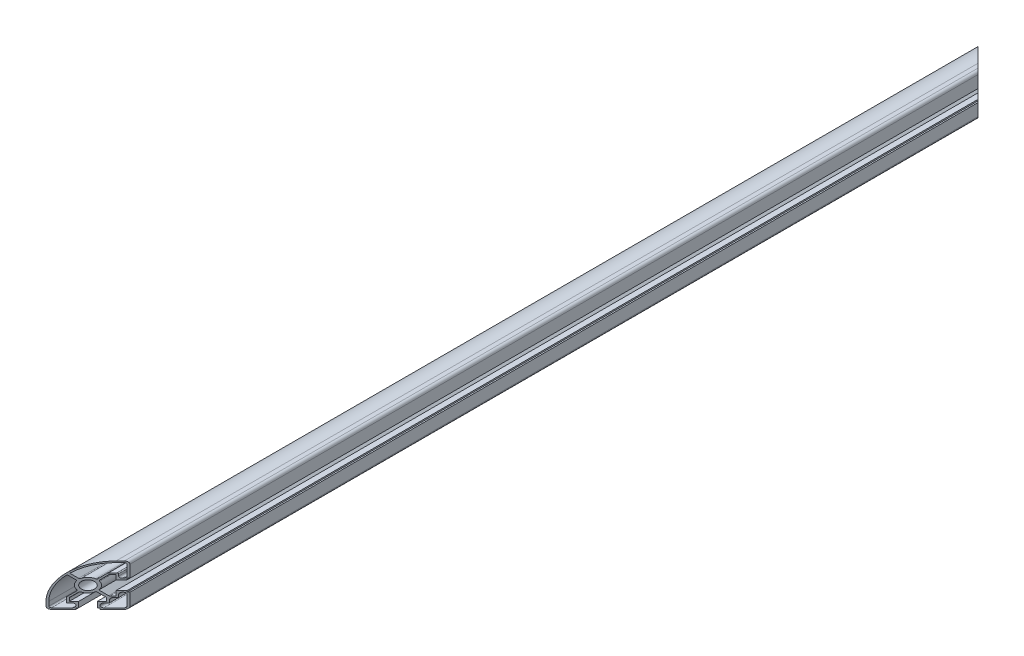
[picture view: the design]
ISO-10303-21;
HEADER;
FILE_DESCRIPTION(('STEP AP214'),'2;1');
FILE_NAME('part.step','',(''),(''),'','','');
FILE_SCHEMA(('AUTOMOTIVE_DESIGN { 1 0 10303 214 1 1 1 1 }'));
ENDSEC;
DATA;
#1=APPLICATION_CONTEXT('core data for automotive mechanical design processes');
#2=APPLICATION_PROTOCOL_DEFINITION('international standard','automotive_design',2000,#1);
#3=PRODUCT_CONTEXT('',#1,'mechanical');
#4=PRODUCT('Part','Part','',(#3));
#5=PRODUCT_RELATED_PRODUCT_CATEGORY('part','',(#4));
#6=PRODUCT_DEFINITION_FORMATION('','',#4);
#7=PRODUCT_DEFINITION_CONTEXT('part definition',#1,'design');
#8=PRODUCT_DEFINITION('design','',#6,#7);
#9=PRODUCT_DEFINITION_SHAPE('','',#8);
#10=(LENGTH_UNIT() NAMED_UNIT(*) SI_UNIT(.MILLI.,.METRE.));
#11=(NAMED_UNIT(*) PLANE_ANGLE_UNIT() SI_UNIT($,.RADIAN.));
#12=(NAMED_UNIT(*) SI_UNIT($,.STERADIAN.) SOLID_ANGLE_UNIT());
#13=UNCERTAINTY_MEASURE_WITH_UNIT(LENGTH_MEASURE(1.E-05),#10,'distance_accuracy_value','');
#14=(GEOMETRIC_REPRESENTATION_CONTEXT(3) GLOBAL_UNCERTAINTY_ASSIGNED_CONTEXT((#13)) GLOBAL_UNIT_ASSIGNED_CONTEXT((#10,
#11,#12)) REPRESENTATION_CONTEXT('',''));
#15=CARTESIAN_POINT('',(0.,0.,0.));
#16=DIRECTION('',(0.,0.,1.));
#17=DIRECTION('',(1.,0.,0.));
#18=AXIS2_PLACEMENT_3D('',#15,#16,#17);
#19=CARTESIAN_POINT('',(-11.2928932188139,32.9999999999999,-55.0352282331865));
#20=DIRECTION('',(0.,0.,-1.));
#21=DIRECTION('',(-1.,0.,0.));
#22=AXIS2_PLACEMENT_3D('',#19,#20,#21);
#23=CYLINDRICAL_SURFACE('',#22,1.);
#24=CARTESIAN_POINT('',(-11.2928932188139,32.9999999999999,-88.7423350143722));
#25=DIRECTION('',(-0.707106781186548,0.,-0.707106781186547));
#26=DIRECTION('',(0.707106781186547,0.,-0.707106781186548));
#27=AXIS2_PLACEMENT_3D('',#24,#25,#26);
#28=ELLIPSE('',#27,1.4142135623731,1.);
#29=CARTESIAN_POINT('',(-11.2928932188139,33.9999999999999,-88.7423350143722));
#30=VERTEX_POINT('',#29);
#31=CARTESIAN_POINT('',(-12.0000000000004,33.7071067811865,-88.0352282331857));
#32=VERTEX_POINT('',#31);
#33=EDGE_CURVE('E1252',#30,#32,#28,.F.);
#34=ORIENTED_EDGE('',*,*,#33,.F.);
#35=DIRECTION('',(0.,0.,-1.));
#36=VECTOR('',#35,1.);
#37=CARTESIAN_POINT('',(-11.2928932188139,33.9999999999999,-55.0352282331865));
#38=LINE('',#37,#36);
#39=CARTESIAN_POINT('',(-11.2928932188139,33.9999999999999,-1021.32812145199));
#40=VERTEX_POINT('',#39);
#41=EDGE_CURVE('E756',#30,#40,#38,.T.);
#42=ORIENTED_EDGE('',*,*,#41,.T.);
#43=CARTESIAN_POINT('',(-11.2928932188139,32.9999999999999,-1021.32812145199));
#44=DIRECTION('',(-0.707106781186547,0.,0.707106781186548));
#45=DIRECTION('',(-0.707106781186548,0.,-0.707106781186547));
#46=AXIS2_PLACEMENT_3D('',#43,#44,#45);
#47=ELLIPSE('',#46,1.41421356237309,1.);
#48=CARTESIAN_POINT('',(-12.0000000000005,33.7071067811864,-1022.03522823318));
#49=VERTEX_POINT('',#48);
#50=EDGE_CURVE('E955',#49,#40,#47,.F.);
#51=ORIENTED_EDGE('',*,*,#50,.F.);
#52=DIRECTION('',(0.,0.,-1.));
#53=VECTOR('',#52,1.);
#54=CARTESIAN_POINT('',(-12.0000000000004,33.7071067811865,-55.0352282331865));
#55=LINE('',#54,#53);
#56=EDGE_CURVE('E11',#32,#49,#55,.T.);
#57=ORIENTED_EDGE('',*,*,#56,.F.);
#58=EDGE_LOOP('',(#34,#42,#51,#57));
#59=FACE_BOUND('',#58,.T.);
#60=ADVANCED_FACE('F31',(#59),#23,.T.);
#61=CARTESIAN_POINT('',(-48.0631727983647,-2.35606601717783,-55.0352282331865));
#62=DIRECTION('',(-0.707106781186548,0.707106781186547,0.));
#63=DIRECTION('',(-0.707106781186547,-0.707106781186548,0.));
#64=AXIS2_PLACEMENT_3D('',#61,#62,#63);
#65=PLANE('',#64);
#66=DIRECTION('',(-0.577350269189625,-0.577350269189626,0.577350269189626));
#67=VECTOR('',#66,1.);
#68=CARTESIAN_POINT('',(-47.0421151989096,-1.33500841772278,-52.9931130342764));
#69=LINE('',#68,#67);
#70=CARTESIAN_POINT('',(-17.0685685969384,28.6385381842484,-82.9666596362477));
#71=VERTEX_POINT('',#70);
#72=EDGE_CURVE('E1250',#32,#71,#69,.T.);
#73=ORIENTED_EDGE('',*,*,#72,.F.);
#74=ORIENTED_EDGE('',*,*,#56,.T.);
#75=DIRECTION('',(0.577350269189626,0.577350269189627,0.577350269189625));
#76=VECTOR('',#75,1.);
#77=CARTESIAN_POINT('',(286.291218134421,331.998324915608,-723.744010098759));
#78=LINE('',#77,#76);
#79=CARTESIAN_POINT('',(-17.0685685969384,28.6385381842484,-1027.10379683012));
#80=VERTEX_POINT('',#79);
#81=EDGE_CURVE('E952',#80,#49,#78,.T.);
#82=ORIENTED_EDGE('',*,*,#81,.F.);
#83=DIRECTION('',(0.,0.,-1.));
#84=VECTOR('',#83,1.);
#85=CARTESIAN_POINT('',(-17.0685685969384,28.6385381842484,-55.0352282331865));
#86=LINE('',#85,#84);
#87=EDGE_CURVE('E40',#71,#80,#86,.T.);
#88=ORIENTED_EDGE('',*,*,#87,.F.);
#89=EDGE_LOOP('',(#73,#74,#82,#88));
#90=FACE_BOUND('',#89,.T.);
#91=ADVANCED_FACE('F1365',(#90),#65,.T.);
#92=CARTESIAN_POINT('',(-17.775675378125,29.345644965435,-55.0352282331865));
#93=DIRECTION('',(0.,0.,-1.));
#94=DIRECTION('',(-1.,0.,0.));
#95=AXIS2_PLACEMENT_3D('',#92,#93,#94);
#96=CYLINDRICAL_SURFACE('',#95,1.);
#97=CARTESIAN_POINT('',(-17.775675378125,29.345644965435,-82.2595528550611));
#98=DIRECTION('',(-0.707106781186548,0.,-0.707106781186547));
#99=DIRECTION('',(0.707106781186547,0.,-0.707106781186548));
#100=AXIS2_PLACEMENT_3D('',#97,#98,#99);
#101=ELLIPSE('',#100,1.4142135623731,1.);
#102=CARTESIAN_POINT('',(-18.3436682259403,28.5226114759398,-81.6915600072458));
#103=VERTEX_POINT('',#102);
#104=EDGE_CURVE('E1248',#71,#103,#101,.T.);
#105=ORIENTED_EDGE('',*,*,#104,.F.);
#106=ORIENTED_EDGE('',*,*,#87,.T.);
#107=CARTESIAN_POINT('',(-17.775675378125,29.345644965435,-1027.8109036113));
#108=DIRECTION('',(-0.707106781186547,0.,0.707106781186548));
#109=DIRECTION('',(-0.707106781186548,0.,-0.707106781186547));
#110=AXIS2_PLACEMENT_3D('',#107,#108,#109);
#111=ELLIPSE('',#110,1.4142135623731,1.);
#112=CARTESIAN_POINT('',(-18.3436682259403,28.5226114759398,-1028.37889645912));
#113=VERTEX_POINT('',#112);
#114=EDGE_CURVE('E949',#113,#80,#111,.T.);
#115=ORIENTED_EDGE('',*,*,#114,.F.);
#116=DIRECTION('',(0.,0.,-1.));
#117=VECTOR('',#116,1.);
#118=CARTESIAN_POINT('',(-18.3436682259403,28.5226114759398,-55.0352282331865));
#119=LINE('',#118,#117);
#120=EDGE_CURVE('E782',#103,#113,#119,.T.);
#121=ORIENTED_EDGE('',*,*,#120,.F.);
#122=EDGE_LOOP('',(#105,#106,#115,#121));
#123=FACE_BOUND('',#122,.T.);
#124=ADVANCED_FACE('F1371',(#123),#96,.F.);
#125=CARTESIAN_POINT('',(-22.5,22.5,-55.0352282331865));
#126=DIRECTION('',(0.,0.,-1.));
#127=DIRECTION('',(-1.,0.,0.));
#128=AXIS2_PLACEMENT_3D('',#125,#126,#127);
#129=CYLINDRICAL_SURFACE('',#128,7.31757765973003);
#130=DIRECTION('',(0.,0.,-1.));
#131=VECTOR('',#130,1.);
#132=CARTESIAN_POINT('',(-26.2783100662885,28.7666830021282,-55.0352282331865));
#133=LINE('',#132,#131);
#134=CARTESIAN_POINT('',(-26.2783100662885,28.7666830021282,-73.7569181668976));
#135=VERTEX_POINT('',#134);
#136=CARTESIAN_POINT('',(-26.2783100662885,28.7666830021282,-1036.31353829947));
#137=VERTEX_POINT('',#136);
#138=EDGE_CURVE('E780',#135,#137,#133,.T.);
#139=ORIENTED_EDGE('',*,*,#138,.F.);
#140=CARTESIAN_POINT('',(-22.5,22.5,-77.5352282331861));
#141=DIRECTION('',(-0.707106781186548,0.,-0.707106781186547));
#142=DIRECTION('',(0.707106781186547,0.,-0.707106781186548));
#143=AXIS2_PLACEMENT_3D('',#140,#141,#142);
#144=ELLIPSE('',#143,10.3486175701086,7.31757765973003);
#145=EDGE_CURVE('E1245',#135,#103,#144,.T.);
#146=ORIENTED_EDGE('',*,*,#145,.T.);
#147=ORIENTED_EDGE('',*,*,#120,.T.);
#148=CARTESIAN_POINT('',(-22.5,22.5,-1032.53522823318));
#149=DIRECTION('',(-0.707106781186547,0.,0.707106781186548));
#150=DIRECTION('',(-0.707106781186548,0.,-0.707106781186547));
#151=AXIS2_PLACEMENT_3D('',#148,#149,#150);
#152=ELLIPSE('',#151,10.3486175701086,7.31757765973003);
#153=EDGE_CURVE('E946',#113,#137,#152,.T.);
#154=ORIENTED_EDGE('',*,*,#153,.T.);
#155=EDGE_LOOP('',(#139,#146,#147,#154));
#156=FACE_BOUND('',#155,.T.);
#157=ADVANCED_FACE('F2133',(#156),#129,.T.);
#158=CARTESIAN_POINT('',(-26.7946435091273,29.6230706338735,-55.0352282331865));
#159=DIRECTION('',(0.,0.,-1.));
#160=DIRECTION('',(-1.,0.,0.));
#161=AXIS2_PLACEMENT_3D('',#158,#159,#160);
#162=CYLINDRICAL_SURFACE('',#161,1.);
#163=DIRECTION('',(0.,0.,-1.));
#164=VECTOR('',#163,1.);
#165=CARTESIAN_POINT('',(-27.5017502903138,28.9159638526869,-55.0352282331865));
#166=LINE('',#165,#164);
#167=CARTESIAN_POINT('',(-27.5017502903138,28.9159638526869,-72.5334779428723));
#168=VERTEX_POINT('',#167);
#169=CARTESIAN_POINT('',(-27.501750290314,28.915963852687,-1037.53697852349));
#170=VERTEX_POINT('',#169);
#171=EDGE_CURVE('E778',#168,#170,#166,.T.);
#172=ORIENTED_EDGE('',*,*,#171,.F.);
#173=CARTESIAN_POINT('',(-26.7946435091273,29.6230706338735,-73.2405847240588));
#174=DIRECTION('',(-0.707106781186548,0.,-0.707106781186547));
#175=DIRECTION('',(0.707106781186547,0.,-0.707106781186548));
#176=AXIS2_PLACEMENT_3D('',#173,#174,#175);
#177=ELLIPSE('',#176,1.4142135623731,1.);
#178=EDGE_CURVE('E1242',#168,#135,#177,.F.);
#179=ORIENTED_EDGE('',*,*,#178,.T.);
#180=ORIENTED_EDGE('',*,*,#138,.T.);
#181=CARTESIAN_POINT('',(-26.7946435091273,29.6230706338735,-1036.82987174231));
#182=DIRECTION('',(-0.707106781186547,0.,0.707106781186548));
#183=DIRECTION('',(-0.707106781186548,0.,-0.707106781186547));
#184=AXIS2_PLACEMENT_3D('',#181,#182,#183);
#185=ELLIPSE('',#184,1.41421356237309,1.);
#186=EDGE_CURVE('E943',#137,#170,#185,.F.);
#187=ORIENTED_EDGE('',*,*,#186,.T.);
#188=EDGE_LOOP('',(#172,#179,#180,#187));
#189=FACE_BOUND('',#188,.T.);
#190=ADVANCED_FACE('F2124',(#189),#162,.F.);
#191=CARTESIAN_POINT('',(3.77027957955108,-2.35606601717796,-55.0352282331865));
#192=DIRECTION('',(-0.707106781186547,-0.707106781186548,0.));
#193=DIRECTION('',(0.707106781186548,-0.707106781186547,0.));
#194=AXIS2_PLACEMENT_3D('',#191,#192,#193);
#195=PLANE('',#194);
#196=DIRECTION('',(0.,0.,-1.));
#197=VECTOR('',#196,1.);
#198=CARTESIAN_POINT('',(-32.2389145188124,33.6531280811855,-55.0352282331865));
#199=LINE('',#198,#197);
#200=CARTESIAN_POINT('',(-32.2389145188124,33.6531280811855,-67.7963137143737));
#201=VERTEX_POINT('',#200);
#202=CARTESIAN_POINT('',(-32.2389145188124,33.6531280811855,-1042.27414275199));
#203=VERTEX_POINT('',#202);
#204=EDGE_CURVE('E776',#201,#203,#199,.T.);
#205=ORIENTED_EDGE('',*,*,#204,.F.);
#206=DIRECTION('',(0.577350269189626,-0.577350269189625,-0.577350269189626));
#207=VECTOR('',#206,1.);
#208=CARTESIAN_POINT('',(-12.4864802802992,13.9006938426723,-87.5487479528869));
#209=LINE('',#208,#207);
#210=EDGE_CURVE('E1239',#201,#168,#209,.T.);
#211=ORIENTED_EDGE('',*,*,#210,.T.);
#212=ORIENTED_EDGE('',*,*,#171,.T.);
#213=DIRECTION('',(-0.577350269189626,0.577350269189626,-0.577350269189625));
#214=VECTOR('',#213,1.);
#215=CARTESIAN_POINT('',(320.846853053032,-319.432639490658,-689.188375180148));
#216=LINE('',#215,#214);
#217=EDGE_CURVE('E940',#170,#203,#216,.T.);
#218=ORIENTED_EDGE('',*,*,#217,.T.);
#219=EDGE_LOOP('',(#205,#211,#212,#218));
#220=FACE_BOUND('',#219,.T.);
#221=ADVANCED_FACE('F2115',(#220),#195,.F.);
#222=CARTESIAN_POINT('',(-7.5,7.5,-55.0352282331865));
#223=DIRECTION('',(0.,0.,-1.));
#224=DIRECTION('',(-1.,0.,0.));
#225=AXIS2_PLACEMENT_3D('',#222,#223,#224);
#226=CYLINDRICAL_SURFACE('',#225,36.);
#227=CARTESIAN_POINT('',(-7.5,7.5,-92.5352282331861));
#228=DIRECTION('',(-0.707106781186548,0.,-0.707106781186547));
#229=DIRECTION('',(0.707106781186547,0.,-0.707106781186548));
#230=AXIS2_PLACEMENT_3D('',#227,#228,#229);
#231=ELLIPSE('',#230,50.9116882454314,36.);
#232=CARTESIAN_POINT('',(-7.5,43.5,-92.5352282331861));
#233=VERTEX_POINT('',#232);
#234=EDGE_CURVE('E1237',#201,#233,#231,.T.);
#235=ORIENTED_EDGE('',*,*,#234,.F.);
#236=ORIENTED_EDGE('',*,*,#204,.T.);
#237=CARTESIAN_POINT('',(-7.5,7.5,-1017.53522823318));
#238=DIRECTION('',(-0.707106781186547,0.,0.707106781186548));
#239=DIRECTION('',(-0.707106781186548,0.,-0.707106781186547));
#240=AXIS2_PLACEMENT_3D('',#237,#238,#239);
#241=ELLIPSE('',#240,50.9116882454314,36.);
#242=CARTESIAN_POINT('',(-7.49999999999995,43.5,-1017.53522823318));
#243=VERTEX_POINT('',#242);
#244=EDGE_CURVE('E937',#243,#203,#241,.T.);
#245=ORIENTED_EDGE('',*,*,#244,.F.);
#246=DIRECTION('',(0.,0.,-1.));
#247=VECTOR('',#246,1.);
#248=CARTESIAN_POINT('',(-7.5,43.5,-55.0352282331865));
#249=LINE('',#248,#247);
#250=EDGE_CURVE('E774',#233,#243,#249,.T.);
#251=ORIENTED_EDGE('',*,*,#250,.F.);
#252=EDGE_LOOP('',(#235,#236,#245,#251));
#253=FACE_BOUND('',#252,.T.);
#254=ADVANCED_FACE('F2106',(#253),#226,.F.);
#255=CARTESIAN_POINT('',(-22.1464466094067,43.5,-55.0352282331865));
#256=DIRECTION('',(0.,-1.,0.));
#257=DIRECTION('',(0.,0.,-1.));
#258=AXIS2_PLACEMENT_3D('',#255,#256,#257);
#259=PLANE('',#258);
#260=DIRECTION('',(0.707106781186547,0.,-0.707106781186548));
#261=VECTOR('',#260,1.);
#262=CARTESIAN_POINT('',(-33.5732233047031,43.5,-66.4620049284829));
#263=LINE('',#262,#261);
#264=CARTESIAN_POINT('',(-3.00000000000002,43.5,-97.0352282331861));
#265=VERTEX_POINT('',#264);
#266=EDGE_CURVE('E1235',#233,#265,#263,.T.);
#267=ORIENTED_EDGE('',*,*,#266,.F.);
#268=ORIENTED_EDGE('',*,*,#250,.T.);
#269=DIRECTION('',(-0.707106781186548,0.,-0.707106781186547));
#270=VECTOR('',#269,1.);
#271=CARTESIAN_POINT('',(466.426776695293,43.5,-543.608451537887));
#272=LINE('',#271,#270);
#273=CARTESIAN_POINT('',(-3.00000000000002,43.5,-1013.03522823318));
#274=VERTEX_POINT('',#273);
#275=EDGE_CURVE('E934',#274,#243,#272,.T.);
#276=ORIENTED_EDGE('',*,*,#275,.F.);
#277=DIRECTION('',(0.,0.,-1.));
#278=VECTOR('',#277,1.);
#279=CARTESIAN_POINT('',(-3.00000000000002,43.5,-55.0352282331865));
#280=LINE('',#279,#278);
#281=EDGE_CURVE('E772',#265,#274,#280,.T.);
#282=ORIENTED_EDGE('',*,*,#281,.F.);
#283=EDGE_LOOP('',(#267,#268,#276,#282));
#284=FACE_BOUND('',#283,.T.);
#285=ADVANCED_FACE('F2097',(#284),#259,.T.);
#286=CARTESIAN_POINT('',(-3.,42.,-55.0352282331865));
#287=DIRECTION('',(0.,0.,-1.));
#288=DIRECTION('',(-1.,0.,0.));
#289=AXIS2_PLACEMENT_3D('',#286,#287,#288);
#290=CYLINDRICAL_SURFACE('',#289,1.5);
#291=CARTESIAN_POINT('',(-3.,42.,-97.0352282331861));
#292=DIRECTION('',(-0.707106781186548,0.,-0.707106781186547));
#293=DIRECTION('',(0.707106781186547,0.,-0.707106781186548));
#294=AXIS2_PLACEMENT_3D('',#291,#292,#293);
#295=ELLIPSE('',#294,2.12132034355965,1.5);
#296=CARTESIAN_POINT('',(-1.5,42.,-98.5352282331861));
#297=VERTEX_POINT('',#296);
#298=EDGE_CURVE('E1233',#265,#297,#295,.T.);
#299=ORIENTED_EDGE('',*,*,#298,.F.);
#300=ORIENTED_EDGE('',*,*,#281,.T.);
#301=CARTESIAN_POINT('',(-3.,42.,-1013.03522823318));
#302=DIRECTION('',(-0.707106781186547,0.,0.707106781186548));
#303=DIRECTION('',(-0.707106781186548,0.,-0.707106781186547));
#304=AXIS2_PLACEMENT_3D('',#301,#302,#303);
#305=ELLIPSE('',#304,2.12132034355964,1.5);
#306=CARTESIAN_POINT('',(-1.5,42.,-1011.53522823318));
#307=VERTEX_POINT('',#306);
#308=EDGE_CURVE('E931',#307,#274,#305,.T.);
#309=ORIENTED_EDGE('',*,*,#308,.F.);
#310=DIRECTION('',(0.,0.,-1.));
#311=VECTOR('',#310,1.);
#312=CARTESIAN_POINT('',(-1.5,42.,-55.0352282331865));
#313=LINE('',#312,#311);
#314=EDGE_CURVE('E770',#297,#307,#313,.T.);
#315=ORIENTED_EDGE('',*,*,#314,.F.);
#316=EDGE_LOOP('',(#299,#300,#309,#315));
#317=FACE_BOUND('',#316,.T.);
#318=ADVANCED_FACE('F2088',(#317),#290,.F.);
#319=CARTESIAN_POINT('',(-1.5,-28.2727922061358,-55.0352282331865));
#320=DIRECTION('',(1.,0.,0.));
#321=DIRECTION('',(0.,1.,0.));
#322=AXIS2_PLACEMENT_3D('',#319,#320,#321);
#323=PLANE('',#322);
#324=DIRECTION('',(0.,0.,-1.));
#325=VECTOR('',#324,1.);
#326=CARTESIAN_POINT('',(-1.5,31.,-55.0352282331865));
#327=LINE('',#326,#325);
#328=CARTESIAN_POINT('',(-1.5,31.,-98.5352282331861));
#329=VERTEX_POINT('',#328);
#330=CARTESIAN_POINT('',(-1.5,31.,-1011.53522823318));
#331=VERTEX_POINT('',#330);
#332=EDGE_CURVE('E768',#329,#331,#327,.T.);
#333=ORIENTED_EDGE('',*,*,#332,.F.);
#334=DIRECTION('',(0.,1.,0.));
#335=VECTOR('',#334,1.);
#336=CARTESIAN_POINT('',(-1.5,-28.2727922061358,-98.5352282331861));
#337=LINE('',#336,#335);
#338=EDGE_CURVE('E1230',#329,#297,#337,.T.);
#339=ORIENTED_EDGE('',*,*,#338,.T.);
#340=ORIENTED_EDGE('',*,*,#314,.T.);
#341=DIRECTION('',(0.,-1.,0.));
#342=VECTOR('',#341,1.);
#343=CARTESIAN_POINT('',(-1.5,-28.2727922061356,-1011.53522823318));
#344=LINE('',#343,#342);
#345=EDGE_CURVE('E928',#307,#331,#344,.T.);
#346=ORIENTED_EDGE('',*,*,#345,.T.);
#347=EDGE_LOOP('',(#333,#339,#340,#346));
#348=FACE_BOUND('',#347,.T.);
#349=ADVANCED_FACE('F2079',(#348),#323,.F.);
#350=CARTESIAN_POINT('',(-3.5,31.,-55.0352282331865));
#351=DIRECTION('',(0.,0.,-1.));
#352=DIRECTION('',(-1.,0.,0.));
#353=AXIS2_PLACEMENT_3D('',#350,#351,#352);
#354=CYLINDRICAL_SURFACE('',#353,2.);
#355=CARTESIAN_POINT('',(-3.5,31.,-96.5352282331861));
#356=DIRECTION('',(-0.707106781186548,0.,-0.707106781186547));
#357=DIRECTION('',(0.707106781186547,0.,-0.707106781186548));
#358=AXIS2_PLACEMENT_3D('',#355,#356,#357);
#359=ELLIPSE('',#358,2.82842712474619,2.);
#360=CARTESIAN_POINT('',(-3.50000000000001,29.,-96.5352282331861));
#361=VERTEX_POINT('',#360);
#362=EDGE_CURVE('E1228',#329,#361,#359,.T.);
#363=ORIENTED_EDGE('',*,*,#362,.F.);
#364=ORIENTED_EDGE('',*,*,#332,.T.);
#365=CARTESIAN_POINT('',(-3.5,31.,-1013.53522823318));
#366=DIRECTION('',(-0.707106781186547,0.,0.707106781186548));
#367=DIRECTION('',(-0.707106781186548,0.,-0.707106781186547));
#368=AXIS2_PLACEMENT_3D('',#365,#366,#367);
#369=ELLIPSE('',#368,2.82842712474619,2.);
#370=CARTESIAN_POINT('',(-3.5,29.,-1013.53522823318));
#371=VERTEX_POINT('',#370);
#372=EDGE_CURVE('E925',#371,#331,#369,.T.);
#373=ORIENTED_EDGE('',*,*,#372,.F.);
#374=DIRECTION('',(0.,0.,-1.));
#375=VECTOR('',#374,1.);
#376=CARTESIAN_POINT('',(-3.50000000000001,29.,-55.0352282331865));
#377=LINE('',#376,#375);
#378=EDGE_CURVE('E766',#361,#371,#377,.T.);
#379=ORIENTED_EDGE('',*,*,#378,.F.);
#380=EDGE_LOOP('',(#363,#364,#373,#379));
#381=FACE_BOUND('',#380,.T.);
#382=ADVANCED_FACE('F2070',(#381),#354,.F.);
#383=CARTESIAN_POINT('',(-22.1464466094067,29.,-55.0352282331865));
#384=DIRECTION('',(0.,-1.,0.));
#385=DIRECTION('',(0.,0.,-1.));
#386=AXIS2_PLACEMENT_3D('',#383,#384,#385);
#387=PLANE('',#386);
#388=DIRECTION('',(0.,0.,-1.));
#389=VECTOR('',#388,1.);
#390=CARTESIAN_POINT('',(-4.00000000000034,29.,-55.0352282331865));
#391=LINE('',#390,#389);
#392=CARTESIAN_POINT('',(-4.00000000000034,29.,-96.0352282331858));
#393=VERTEX_POINT('',#392);
#394=CARTESIAN_POINT('',(-4.00000000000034,29.,-1014.03522823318));
#395=VERTEX_POINT('',#394);
#396=EDGE_CURVE('E764',#393,#395,#391,.T.);
#397=ORIENTED_EDGE('',*,*,#396,.F.);
#398=DIRECTION('',(0.707106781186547,0.,-0.707106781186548));
#399=VECTOR('',#398,1.);
#400=CARTESIAN_POINT('',(-33.5732233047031,29.,-66.4620049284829));
#401=LINE('',#400,#399);
#402=EDGE_CURVE('E1225',#393,#361,#401,.T.);
#403=ORIENTED_EDGE('',*,*,#402,.T.);
#404=ORIENTED_EDGE('',*,*,#378,.T.);
#405=DIRECTION('',(-0.707106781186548,0.,-0.707106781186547));
#406=VECTOR('',#405,1.);
#407=CARTESIAN_POINT('',(466.426776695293,29.,-543.608451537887));
#408=LINE('',#407,#406);
#409=EDGE_CURVE('E922',#371,#395,#408,.T.);
#410=ORIENTED_EDGE('',*,*,#409,.T.);
#411=EDGE_LOOP('',(#397,#403,#404,#410));
#412=FACE_BOUND('',#411,.T.);
#413=ADVANCED_FACE('F2061',(#412),#387,.F.);
#414=CARTESIAN_POINT('',(-4.00000000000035,31.,-55.0352282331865));
#415=DIRECTION('',(0.,0.,-1.));
#416=DIRECTION('',(-1.,0.,0.));
#417=AXIS2_PLACEMENT_3D('',#414,#415,#416);
#418=CYLINDRICAL_SURFACE('',#417,2.);
#419=DIRECTION('',(0.,0.,-1.));
#420=VECTOR('',#419,1.);
#421=CARTESIAN_POINT('',(-6.00000000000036,31.,-55.0352282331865));
#422=LINE('',#421,#420);
#423=CARTESIAN_POINT('',(-6.00000000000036,31.,-94.0352282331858));
#424=VERTEX_POINT('',#423);
#425=CARTESIAN_POINT('',(-6.00000000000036,31.,-1016.03522823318));
#426=VERTEX_POINT('',#425);
#427=EDGE_CURVE('E762',#424,#426,#422,.T.);
#428=ORIENTED_EDGE('',*,*,#427,.F.);
#429=CARTESIAN_POINT('',(-4.00000000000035,31.,-96.0352282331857));
#430=DIRECTION('',(-0.707106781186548,0.,-0.707106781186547));
#431=DIRECTION('',(0.707106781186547,0.,-0.707106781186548));
#432=AXIS2_PLACEMENT_3D('',#429,#430,#431);
#433=ELLIPSE('',#432,2.82842712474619,2.);
#434=EDGE_CURVE('E1222',#424,#393,#433,.F.);
#435=ORIENTED_EDGE('',*,*,#434,.T.);
#436=ORIENTED_EDGE('',*,*,#396,.T.);
#437=CARTESIAN_POINT('',(-4.00000000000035,31.,-1014.03522823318));
#438=DIRECTION('',(-0.707106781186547,0.,0.707106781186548));
#439=DIRECTION('',(-0.707106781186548,0.,-0.707106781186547));
#440=AXIS2_PLACEMENT_3D('',#437,#438,#439);
#441=ELLIPSE('',#440,2.82842712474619,2.);
#442=EDGE_CURVE('E919',#395,#426,#441,.F.);
#443=ORIENTED_EDGE('',*,*,#442,.T.);
#444=EDGE_LOOP('',(#428,#435,#436,#443));
#445=FACE_BOUND('',#444,.T.);
#446=ADVANCED_FACE('F2052',(#445),#418,.F.);
#447=CARTESIAN_POINT('',(-6.00000000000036,-28.2727922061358,-55.0352282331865));
#448=DIRECTION('',(1.,0.,0.));
#449=DIRECTION('',(0.,0.,-1.));
#450=AXIS2_PLACEMENT_3D('',#447,#448,#449);
#451=PLANE('',#450);
#452=DIRECTION('',(0.,1.,0.));
#453=VECTOR('',#452,1.);
#454=CARTESIAN_POINT('',(-6.00000000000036,-28.2727922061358,-94.0352282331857));
#455=LINE('',#454,#453);
#456=CARTESIAN_POINT('',(-6.00000000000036,32.9999999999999,-94.0352282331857));
#457=VERTEX_POINT('',#456);
#458=EDGE_CURVE('E1220',#424,#457,#455,.T.);
#459=ORIENTED_EDGE('',*,*,#458,.F.);
#460=ORIENTED_EDGE('',*,*,#427,.T.);
#461=DIRECTION('',(0.,-1.,0.));
#462=VECTOR('',#461,1.);
#463=CARTESIAN_POINT('',(-6.00000000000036,-28.2727922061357,-1016.03522823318));
#464=LINE('',#463,#462);
#465=CARTESIAN_POINT('',(-6.00000000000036,32.9999999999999,-1016.03522823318));
#466=VERTEX_POINT('',#465);
#467=EDGE_CURVE('E916',#466,#426,#464,.T.);
#468=ORIENTED_EDGE('',*,*,#467,.F.);
#469=DIRECTION('',(0.,0.,-1.));
#470=VECTOR('',#469,1.);
#471=CARTESIAN_POINT('',(-6.00000000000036,32.9999999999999,-55.0352282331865));
#472=LINE('',#471,#470);
#473=EDGE_CURVE('E760',#457,#466,#472,.T.);
#474=ORIENTED_EDGE('',*,*,#473,.F.);
#475=EDGE_LOOP('',(#459,#460,#468,#474));
#476=FACE_BOUND('',#475,.T.);
#477=ADVANCED_FACE('F2043',(#476),#451,.T.);
#478=CARTESIAN_POINT('',(-7.00000000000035,32.9999999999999,-55.0352282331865));
#479=DIRECTION('',(0.,0.,-1.));
#480=DIRECTION('',(-1.,0.,0.));
#481=AXIS2_PLACEMENT_3D('',#478,#479,#480);
#482=CYLINDRICAL_SURFACE('',#481,1.);
#483=DIRECTION('',(0.,0.,-1.));
#484=VECTOR('',#483,1.);
#485=CARTESIAN_POINT('',(-7.00000000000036,33.9999999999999,-55.0352282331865));
#486=LINE('',#485,#484);
#487=CARTESIAN_POINT('',(-7.00000000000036,33.9999999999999,-93.0352282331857));
#488=VERTEX_POINT('',#487);
#489=CARTESIAN_POINT('',(-7.00000000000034,33.9999999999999,-1017.03522823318));
#490=VERTEX_POINT('',#489);
#491=EDGE_CURVE('E758',#488,#490,#486,.T.);
#492=ORIENTED_EDGE('',*,*,#491,.F.);
#493=CARTESIAN_POINT('',(-7.00000000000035,32.9999999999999,-93.0352282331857));
#494=DIRECTION('',(-0.707106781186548,0.,-0.707106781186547));
#495=DIRECTION('',(0.707106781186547,0.,-0.707106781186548));
#496=AXIS2_PLACEMENT_3D('',#493,#494,#495);
#497=ELLIPSE('',#496,1.4142135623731,1.);
#498=EDGE_CURVE('E1217',#488,#457,#497,.T.);
#499=ORIENTED_EDGE('',*,*,#498,.T.);
#500=ORIENTED_EDGE('',*,*,#473,.T.);
#501=CARTESIAN_POINT('',(-7.00000000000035,32.9999999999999,-1017.03522823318));
#502=DIRECTION('',(-0.707106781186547,0.,0.707106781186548));
#503=DIRECTION('',(-0.707106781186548,0.,-0.707106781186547));
#504=AXIS2_PLACEMENT_3D('',#501,#502,#503);
#505=ELLIPSE('',#504,1.41421356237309,1.);
#506=EDGE_CURVE('E913',#466,#490,#505,.T.);
#507=ORIENTED_EDGE('',*,*,#506,.T.);
#508=EDGE_LOOP('',(#492,#499,#500,#507));
#509=FACE_BOUND('',#508,.T.);
#510=ADVANCED_FACE('F2035',(#509),#482,.T.);
#511=CARTESIAN_POINT('',(-29.6230706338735,26.7946435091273,-55.0352282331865));
#512=DIRECTION('',(0.,0.,-1.));
#513=DIRECTION('',(-1.,0.,0.));
#514=AXIS2_PLACEMENT_3D('',#511,#512,#513);
#515=CYLINDRICAL_SURFACE('',#514,1.);
#516=CARTESIAN_POINT('',(-29.6230706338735,26.7946435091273,-70.4121575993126));
#517=DIRECTION('',(-0.707106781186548,0.,-0.707106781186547));
#518=DIRECTION('',(0.707106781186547,0.,-0.707106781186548));
#519=AXIS2_PLACEMENT_3D('',#516,#517,#518);
#520=ELLIPSE('',#519,1.4142135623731,1.);
#521=CARTESIAN_POINT('',(-28.915963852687,27.5017502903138,-71.1192643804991));
#522=VERTEX_POINT('',#521);
#523=CARTESIAN_POINT('',(-28.7666830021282,26.2783100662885,-71.2685452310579));
#524=VERTEX_POINT('',#523);
#525=EDGE_CURVE('E1101',#522,#524,#520,.T.);
#526=ORIENTED_EDGE('',*,*,#525,.F.);
#527=DIRECTION('',(0.,0.,-1.));
#528=VECTOR('',#527,1.);
#529=CARTESIAN_POINT('',(-28.9159638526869,27.5017502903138,-55.0352282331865));
#530=LINE('',#529,#528);
#531=CARTESIAN_POINT('',(-28.915963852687,27.5017502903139,-1038.95119208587));
#532=VERTEX_POINT('',#531);
#533=EDGE_CURVE('E631',#522,#532,#530,.T.);
#534=ORIENTED_EDGE('',*,*,#533,.T.);
#535=CARTESIAN_POINT('',(-29.6230706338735,26.7946435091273,-1039.65829886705));
#536=DIRECTION('',(-0.707106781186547,0.,0.707106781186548));
#537=DIRECTION('',(-0.707106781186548,0.,-0.707106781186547));
#538=AXIS2_PLACEMENT_3D('',#535,#536,#537);
#539=ELLIPSE('',#538,1.41421356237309,1.);
#540=CARTESIAN_POINT('',(-28.7666830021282,26.2783100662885,-1038.80191123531));
#541=VERTEX_POINT('',#540);
#542=EDGE_CURVE('E828',#541,#532,#539,.T.);
#543=ORIENTED_EDGE('',*,*,#542,.F.);
#544=DIRECTION('',(0.,0.,-1.));
#545=VECTOR('',#544,1.);
#546=CARTESIAN_POINT('',(-28.7666830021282,26.2783100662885,-55.0352282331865));
#547=LINE('',#546,#545);
#548=EDGE_CURVE('E677',#524,#541,#547,.T.);
#549=ORIENTED_EDGE('',*,*,#548,.F.);
#550=EDGE_LOOP('',(#526,#534,#543,#549));
#551=FACE_BOUND('',#550,.T.);
#552=ADVANCED_FACE('F833',(#551),#515,.F.);
#553=CARTESIAN_POINT('',(-22.5,22.5,-55.0352282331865));
#554=DIRECTION('',(0.,0.,-1.));
#555=DIRECTION('',(-1.,0.,0.));
#556=AXIS2_PLACEMENT_3D('',#553,#554,#555);
#557=CYLINDRICAL_SURFACE('',#556,7.31757765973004);
#558=DIRECTION('',(0.,0.,-1.));
#559=VECTOR('',#558,1.);
#560=CARTESIAN_POINT('',(-28.5226114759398,18.3436682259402,-55.0352282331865));
#561=LINE('',#560,#559);
#562=CARTESIAN_POINT('',(-28.5226114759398,18.3436682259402,-71.5126167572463));
#563=VERTEX_POINT('',#562);
#564=CARTESIAN_POINT('',(-28.5226114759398,18.3436682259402,-1038.55783970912));
#565=VERTEX_POINT('',#564);
#566=EDGE_CURVE('E807',#563,#565,#561,.T.);
#567=ORIENTED_EDGE('',*,*,#566,.F.);
#568=CARTESIAN_POINT('',(-22.5,22.5,-77.5352282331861));
#569=DIRECTION('',(-0.707106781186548,0.,-0.707106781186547));
#570=DIRECTION('',(0.707106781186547,0.,-0.707106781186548));
#571=AXIS2_PLACEMENT_3D('',#568,#569,#570);
#572=ELLIPSE('',#571,10.3486175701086,7.31757765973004);
#573=EDGE_CURVE('E820',#563,#524,#572,.T.);
#574=ORIENTED_EDGE('',*,*,#573,.T.);
#575=ORIENTED_EDGE('',*,*,#548,.T.);
#576=CARTESIAN_POINT('',(-22.5,22.5,-1032.53522823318));
#577=DIRECTION('',(-0.707106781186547,0.,0.707106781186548));
#578=DIRECTION('',(-0.707106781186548,0.,-0.707106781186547));
#579=AXIS2_PLACEMENT_3D('',#576,#577,#578);
#580=ELLIPSE('',#579,10.3486175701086,7.31757765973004);
#581=EDGE_CURVE('E819',#541,#565,#580,.T.);
#582=ORIENTED_EDGE('',*,*,#581,.T.);
#583=EDGE_LOOP('',(#567,#574,#575,#582));
#584=FACE_BOUND('',#583,.T.);
#585=ADVANCED_FACE('F818',(#584),#557,.T.);
#586=CARTESIAN_POINT('',(-29.345644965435,17.7756753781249,-55.0352282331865));
#587=DIRECTION('',(0.,0.,-1.));
#588=DIRECTION('',(-1.,0.,0.));
#589=AXIS2_PLACEMENT_3D('',#586,#587,#588);
#590=CYLINDRICAL_SURFACE('',#589,1.);
#591=DIRECTION('',(0.,0.,-1.));
#592=VECTOR('',#591,1.);
#593=CARTESIAN_POINT('',(-28.6385381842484,17.0685685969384,-55.0352282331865));
#594=LINE('',#593,#592);
#595=CARTESIAN_POINT('',(-28.6385381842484,17.0685685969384,-71.3966900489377));
#596=VERTEX_POINT('',#595);
#597=CARTESIAN_POINT('',(-28.6385381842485,17.0685685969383,-1038.67376641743));
#598=VERTEX_POINT('',#597);
#599=EDGE_CURVE('E806',#596,#598,#594,.T.);
#600=ORIENTED_EDGE('',*,*,#599,.F.);
#601=CARTESIAN_POINT('',(-29.345644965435,17.7756753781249,-70.6895832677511));
#602=DIRECTION('',(-0.707106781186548,0.,-0.707106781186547));
#603=DIRECTION('',(0.707106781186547,0.,-0.707106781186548));
#604=AXIS2_PLACEMENT_3D('',#601,#602,#603);
#605=ELLIPSE('',#604,1.4142135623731,1.);
#606=EDGE_CURVE('E1078',#596,#563,#605,.F.);
#607=ORIENTED_EDGE('',*,*,#606,.T.);
#608=ORIENTED_EDGE('',*,*,#566,.T.);
#609=CARTESIAN_POINT('',(-29.345644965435,17.7756753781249,-1039.38087319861));
#610=DIRECTION('',(-0.707106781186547,0.,0.707106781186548));
#611=DIRECTION('',(-0.707106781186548,0.,-0.707106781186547));
#612=AXIS2_PLACEMENT_3D('',#609,#610,#611);
#613=ELLIPSE('',#612,1.41421356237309,1.);
#614=EDGE_CURVE('E831',#565,#598,#613,.F.);
#615=ORIENTED_EDGE('',*,*,#614,.T.);
#616=EDGE_LOOP('',(#600,#607,#608,#615));
#617=FACE_BOUND('',#616,.T.);
#618=ADVANCED_FACE('F1077',(#617),#590,.F.);
#619=CARTESIAN_POINT('',(-48.0631727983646,-2.35606601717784,-55.0352282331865));
#620=DIRECTION('',(0.707106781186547,-0.707106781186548,0.));
#621=DIRECTION('',(0.707106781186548,0.707106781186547,0.));
#622=AXIS2_PLACEMENT_3D('',#619,#620,#621);
#623=PLANE('',#622);
#624=DIRECTION('',(0.,0.,-1.));
#625=VECTOR('',#624,1.);
#626=CARTESIAN_POINT('',(-34.,11.7071067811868,-55.0352282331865));
#627=LINE('',#626,#625);
#628=CARTESIAN_POINT('',(-34.,11.7071067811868,-66.0352282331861));
#629=VERTEX_POINT('',#628);
#630=CARTESIAN_POINT('',(-34.,11.7071067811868,-1044.03522823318));
#631=VERTEX_POINT('',#630);
#632=EDGE_CURVE('E804',#629,#631,#627,.T.);
#633=ORIENTED_EDGE('',*,*,#632,.F.);
#634=DIRECTION('',(0.577350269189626,0.577350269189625,-0.577350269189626));
#635=VECTOR('',#634,1.);
#636=CARTESIAN_POINT('',(-47.0421151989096,-1.33500841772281,-52.9931130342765));
#637=LINE('',#636,#635);
#638=EDGE_CURVE('E1083',#629,#596,#637,.T.);
#639=ORIENTED_EDGE('',*,*,#638,.T.);
#640=ORIENTED_EDGE('',*,*,#599,.T.);
#641=DIRECTION('',(-0.577350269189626,-0.577350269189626,-0.577350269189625));
#642=VECTOR('',#641,1.);
#643=CARTESIAN_POINT('',(286.291218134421,331.998324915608,-723.744010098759));
#644=LINE('',#643,#642);
#645=EDGE_CURVE('E1074',#598,#631,#644,.T.);
#646=ORIENTED_EDGE('',*,*,#645,.T.);
#647=EDGE_LOOP('',(#633,#639,#640,#646));
#648=FACE_BOUND('',#647,.T.);
#649=ADVANCED_FACE('F1082',(#648),#623,.F.);
#650=CARTESIAN_POINT('',(-34.,-28.2727922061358,-55.0352282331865));
#651=DIRECTION('',(-1.,0.,0.));
#652=DIRECTION('',(0.,0.,1.));
#653=AXIS2_PLACEMENT_3D('',#650,#651,#652);
#654=PLANE('',#653);
#655=DIRECTION('',(0.,-1.,0.));
#656=VECTOR('',#655,1.);
#657=CARTESIAN_POINT('',(-34.,-28.2727922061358,-66.0352282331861));
#658=LINE('',#657,#656);
#659=CARTESIAN_POINT('',(-34.,6.,-66.0352282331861));
#660=VERTEX_POINT('',#659);
#661=EDGE_CURVE('E1090',#629,#660,#658,.T.);
#662=ORIENTED_EDGE('',*,*,#661,.F.);
#663=ORIENTED_EDGE('',*,*,#632,.T.);
#664=DIRECTION('',(0.,1.,0.));
#665=VECTOR('',#664,1.);
#666=CARTESIAN_POINT('',(-34.,-28.2727922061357,-1044.03522823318));
#667=LINE('',#666,#665);
#668=CARTESIAN_POINT('',(-34.,6.,-1044.03522823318));
#669=VERTEX_POINT('',#668);
#670=EDGE_CURVE('E1071',#669,#631,#667,.T.);
#671=ORIENTED_EDGE('',*,*,#670,.F.);
#672=DIRECTION('',(0.,0.,-1.));
#673=VECTOR('',#672,1.);
#674=CARTESIAN_POINT('',(-34.,6.,-55.0352282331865));
#675=LINE('',#674,#673);
#676=EDGE_CURVE('E802',#660,#669,#675,.T.);
#677=ORIENTED_EDGE('',*,*,#676,.F.);
#678=EDGE_LOOP('',(#662,#663,#671,#677));
#679=FACE_BOUND('',#678,.T.);
#680=ADVANCED_FACE('F1089',(#679),#654,.T.);
#681=CARTESIAN_POINT('',(-22.1464466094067,6.,-55.0352282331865));
#682=DIRECTION('',(0.,1.,0.));
#683=DIRECTION('',(0.,0.,1.));
#684=AXIS2_PLACEMENT_3D('',#681,#682,#683);
#685=PLANE('',#684);
#686=DIRECTION('',(0.,0.,-1.));
#687=VECTOR('',#686,1.);
#688=CARTESIAN_POINT('',(-31.,6.,-55.0352282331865));
#689=LINE('',#688,#687);
#690=CARTESIAN_POINT('',(-31.,6.,-69.0352282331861));
#691=VERTEX_POINT('',#690);
#692=CARTESIAN_POINT('',(-31.,6.,-1041.03522823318));
#693=VERTEX_POINT('',#692);
#694=EDGE_CURVE('E800',#691,#693,#689,.T.);
#695=ORIENTED_EDGE('',*,*,#694,.F.);
#696=DIRECTION('',(-0.707106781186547,0.,0.707106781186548));
#697=VECTOR('',#696,1.);
#698=CARTESIAN_POINT('',(-33.5732233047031,6.,-66.4620049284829));
#699=LINE('',#698,#697);
#700=EDGE_CURVE('E1092',#691,#660,#699,.T.);
#701=ORIENTED_EDGE('',*,*,#700,.T.);
#702=ORIENTED_EDGE('',*,*,#676,.T.);
#703=DIRECTION('',(0.707106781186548,0.,0.707106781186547));
#704=VECTOR('',#703,1.);
#705=CARTESIAN_POINT('',(466.426776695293,6.,-543.608451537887));
#706=LINE('',#705,#704);
#707=EDGE_CURVE('E1068',#669,#693,#706,.T.);
#708=ORIENTED_EDGE('',*,*,#707,.T.);
#709=EDGE_LOOP('',(#695,#701,#702,#708));
#710=FACE_BOUND('',#709,.T.);
#711=ADVANCED_FACE('F1355',(#710),#685,.F.);
#712=CARTESIAN_POINT('',(-31.,4.,-55.0352282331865));
#713=DIRECTION('',(0.,0.,-1.));
#714=DIRECTION('',(-1.,0.,0.));
#715=AXIS2_PLACEMENT_3D('',#712,#713,#714);
#716=CYLINDRICAL_SURFACE('',#715,2.);
#717=CARTESIAN_POINT('',(-31.,4.,-69.0352282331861));
#718=DIRECTION('',(-0.707106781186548,0.,-0.707106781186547));
#719=DIRECTION('',(0.707106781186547,0.,-0.707106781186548));
#720=AXIS2_PLACEMENT_3D('',#717,#718,#719);
#721=ELLIPSE('',#720,2.82842712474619,2.);
#722=CARTESIAN_POINT('',(-29.,3.99999999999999,-71.0352282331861));
#723=VERTEX_POINT('',#722);
#724=EDGE_CURVE('E1095',#691,#723,#721,.T.);
#725=ORIENTED_EDGE('',*,*,#724,.F.);
#726=ORIENTED_EDGE('',*,*,#694,.T.);
#727=CARTESIAN_POINT('',(-31.,4.,-1041.03522823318));
#728=DIRECTION('',(-0.707106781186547,0.,0.707106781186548));
#729=DIRECTION('',(-0.707106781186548,0.,-0.707106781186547));
#730=AXIS2_PLACEMENT_3D('',#727,#728,#729);
#731=ELLIPSE('',#730,2.82842712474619,2.);
#732=CARTESIAN_POINT('',(-29.,3.99999999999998,-1039.03522823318));
#733=VERTEX_POINT('',#732);
#734=EDGE_CURVE('E1065',#733,#693,#731,.T.);
#735=ORIENTED_EDGE('',*,*,#734,.F.);
#736=DIRECTION('',(0.,0.,-1.));
#737=VECTOR('',#736,1.);
#738=CARTESIAN_POINT('',(-29.,3.99999999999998,-55.0352282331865));
#739=LINE('',#738,#737);
#740=EDGE_CURVE('E798',#723,#733,#739,.T.);
#741=ORIENTED_EDGE('',*,*,#740,.F.);
#742=EDGE_LOOP('',(#725,#726,#735,#741));
#743=FACE_BOUND('',#742,.T.);
#744=ADVANCED_FACE('F1352',(#743),#716,.F.);
#745=CARTESIAN_POINT('',(-29.,-28.2727922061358,-55.0352282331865));
#746=DIRECTION('',(-1.,0.,0.));
#747=DIRECTION('',(0.,0.,1.));
#748=AXIS2_PLACEMENT_3D('',#745,#746,#747);
#749=PLANE('',#748);
#750=DIRECTION('',(0.,-1.,0.));
#751=VECTOR('',#750,1.);
#752=CARTESIAN_POINT('',(-29.,-28.2727922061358,-71.0352282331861));
#753=LINE('',#752,#751);
#754=CARTESIAN_POINT('',(-29.,3.50000000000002,-71.0352282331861));
#755=VERTEX_POINT('',#754);
#756=EDGE_CURVE('E1340',#723,#755,#753,.T.);
#757=ORIENTED_EDGE('',*,*,#756,.F.);
#758=ORIENTED_EDGE('',*,*,#740,.T.);
#759=DIRECTION('',(0.,1.,0.));
#760=VECTOR('',#759,1.);
#761=CARTESIAN_POINT('',(-29.,-28.2727922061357,-1039.03522823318));
#762=LINE('',#761,#760);
#763=CARTESIAN_POINT('',(-29.,3.50000000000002,-1039.03522823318));
#764=VERTEX_POINT('',#763);
#765=EDGE_CURVE('E1062',#764,#733,#762,.T.);
#766=ORIENTED_EDGE('',*,*,#765,.F.);
#767=DIRECTION('',(0.,0.,-1.));
#768=VECTOR('',#767,1.);
#769=CARTESIAN_POINT('',(-29.,3.50000000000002,-55.0352282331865));
#770=LINE('',#769,#768);
#771=EDGE_CURVE('E796',#755,#764,#770,.T.);
#772=ORIENTED_EDGE('',*,*,#771,.F.);
#773=EDGE_LOOP('',(#757,#758,#766,#772));
#774=FACE_BOUND('',#773,.T.);
#775=ADVANCED_FACE('F1349',(#774),#749,.T.);
#776=CARTESIAN_POINT('',(-31.,3.5,-55.0352282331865));
#777=DIRECTION('',(0.,0.,-1.));
#778=DIRECTION('',(-1.,0.,0.));
#779=AXIS2_PLACEMENT_3D('',#776,#777,#778);
#780=CYLINDRICAL_SURFACE('',#779,2.);
#781=DIRECTION('',(0.,0.,-1.));
#782=VECTOR('',#781,1.);
#783=CARTESIAN_POINT('',(-31.,1.5,-55.0352282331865));
#784=LINE('',#783,#782);
#785=CARTESIAN_POINT('',(-31.,1.5,-69.0352282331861));
#786=VERTEX_POINT('',#785);
#787=CARTESIAN_POINT('',(-31.,1.5,-1041.03522823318));
#788=VERTEX_POINT('',#787);
#789=EDGE_CURVE('E794',#786,#788,#784,.T.);
#790=ORIENTED_EDGE('',*,*,#789,.F.);
#791=CARTESIAN_POINT('',(-31.,3.5,-69.0352282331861));
#792=DIRECTION('',(-0.707106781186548,0.,-0.707106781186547));
#793=DIRECTION('',(0.707106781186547,0.,-0.707106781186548));
#794=AXIS2_PLACEMENT_3D('',#791,#792,#793);
#795=ELLIPSE('',#794,2.82842712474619,2.);
#796=EDGE_CURVE('E1337',#786,#755,#795,.F.);
#797=ORIENTED_EDGE('',*,*,#796,.T.);
#798=ORIENTED_EDGE('',*,*,#771,.T.);
#799=CARTESIAN_POINT('',(-31.,3.5,-1041.03522823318));
#800=DIRECTION('',(-0.707106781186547,0.,0.707106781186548));
#801=DIRECTION('',(-0.707106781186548,0.,-0.707106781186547));
#802=AXIS2_PLACEMENT_3D('',#799,#800,#801);
#803=ELLIPSE('',#802,2.82842712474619,2.);
#804=EDGE_CURVE('E1059',#764,#788,#803,.F.);
#805=ORIENTED_EDGE('',*,*,#804,.T.);
#806=EDGE_LOOP('',(#790,#797,#798,#805));
#807=FACE_BOUND('',#806,.T.);
#808=ADVANCED_FACE('F1403',(#807),#780,.F.);
#809=CARTESIAN_POINT('',(-22.1464466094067,1.5,-55.0352282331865));
#810=DIRECTION('',(0.,1.,0.));
#811=DIRECTION('',(0.,0.,1.));
#812=AXIS2_PLACEMENT_3D('',#809,#810,#811);
#813=PLANE('',#812);
#814=DIRECTION('',(-0.707106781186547,0.,0.707106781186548));
#815=VECTOR('',#814,1.);
#816=CARTESIAN_POINT('',(-33.5732233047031,1.5,-66.4620049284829));
#817=LINE('',#816,#815);
#818=CARTESIAN_POINT('',(-42.,1.5,-58.0352282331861));
#819=VERTEX_POINT('',#818);
#820=EDGE_CURVE('E1335',#786,#819,#817,.T.);
#821=ORIENTED_EDGE('',*,*,#820,.F.);
#822=ORIENTED_EDGE('',*,*,#789,.T.);
#823=DIRECTION('',(0.707106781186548,0.,0.707106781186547));
#824=VECTOR('',#823,1.);
#825=CARTESIAN_POINT('',(466.426776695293,1.5,-543.608451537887));
#826=LINE('',#825,#824);
#827=CARTESIAN_POINT('',(-42.,1.5,-1052.03522823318));
#828=VERTEX_POINT('',#827);
#829=EDGE_CURVE('E1056',#828,#788,#826,.T.);
#830=ORIENTED_EDGE('',*,*,#829,.F.);
#831=DIRECTION('',(0.,0.,-1.));
#832=VECTOR('',#831,1.);
#833=CARTESIAN_POINT('',(-42.,1.5,-55.0352282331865));
#834=LINE('',#833,#832);
#835=EDGE_CURVE('E792',#819,#828,#834,.T.);
#836=ORIENTED_EDGE('',*,*,#835,.F.);
#837=EDGE_LOOP('',(#821,#822,#830,#836));
#838=FACE_BOUND('',#837,.T.);
#839=ADVANCED_FACE('F1399',(#838),#813,.T.);
#840=CARTESIAN_POINT('',(-42.,2.99999999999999,-55.0352282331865));
#841=DIRECTION('',(0.,0.,-1.));
#842=DIRECTION('',(-1.,0.,0.));
#843=AXIS2_PLACEMENT_3D('',#840,#841,#842);
#844=CYLINDRICAL_SURFACE('',#843,1.5);
#845=CARTESIAN_POINT('',(-42.,2.99999999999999,-58.0352282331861));
#846=DIRECTION('',(-0.707106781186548,0.,-0.707106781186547));
#847=DIRECTION('',(0.707106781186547,0.,-0.707106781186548));
#848=AXIS2_PLACEMENT_3D('',#845,#846,#847);
#849=ELLIPSE('',#848,2.12132034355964,1.5);
#850=CARTESIAN_POINT('',(-43.5,3.,-56.5352282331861));
#851=VERTEX_POINT('',#850);
#852=EDGE_CURVE('E1333',#819,#851,#849,.T.);
#853=ORIENTED_EDGE('',*,*,#852,.F.);
#854=ORIENTED_EDGE('',*,*,#835,.T.);
#855=CARTESIAN_POINT('',(-42.,2.99999999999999,-1052.03522823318));
#856=DIRECTION('',(-0.707106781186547,0.,0.707106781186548));
#857=DIRECTION('',(-0.707106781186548,0.,-0.707106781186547));
#858=AXIS2_PLACEMENT_3D('',#855,#856,#857);
#859=ELLIPSE('',#858,2.12132034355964,1.5);
#860=CARTESIAN_POINT('',(-43.5,3.,-1053.53522823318));
#861=VERTEX_POINT('',#860);
#862=EDGE_CURVE('E1053',#861,#828,#859,.T.);
#863=ORIENTED_EDGE('',*,*,#862,.F.);
#864=DIRECTION('',(0.,0.,-1.));
#865=VECTOR('',#864,1.);
#866=CARTESIAN_POINT('',(-43.5,3.,-55.0352282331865));
#867=LINE('',#866,#865);
#868=EDGE_CURVE('E790',#851,#861,#867,.T.);
#869=ORIENTED_EDGE('',*,*,#868,.F.);
#870=EDGE_LOOP('',(#853,#854,#863,#869));
#871=FACE_BOUND('',#870,.T.);
#872=ADVANCED_FACE('F1395',(#871),#844,.F.);
#873=CARTESIAN_POINT('',(-43.5,-28.2727922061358,-55.0352282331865));
#874=DIRECTION('',(-1.,0.,0.));
#875=DIRECTION('',(0.,0.,1.));
#876=AXIS2_PLACEMENT_3D('',#873,#874,#875);
#877=PLANE('',#876);
#878=DIRECTION('',(0.,0.,-1.));
#879=VECTOR('',#878,1.);
#880=CARTESIAN_POINT('',(-43.5,7.5,-55.0352282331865));
#881=LINE('',#880,#879);
#882=CARTESIAN_POINT('',(-43.5,7.5,-56.5352282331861));
#883=VERTEX_POINT('',#882);
#884=CARTESIAN_POINT('',(-43.5,7.5,-1053.53522823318));
#885=VERTEX_POINT('',#884);
#886=EDGE_CURVE('E788',#883,#885,#881,.T.);
#887=ORIENTED_EDGE('',*,*,#886,.F.);
#888=DIRECTION('',(0.,-1.,0.));
#889=VECTOR('',#888,1.);
#890=CARTESIAN_POINT('',(-43.5,-28.2727922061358,-56.5352282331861));
#891=LINE('',#890,#889);
#892=EDGE_CURVE('E1330',#883,#851,#891,.T.);
#893=ORIENTED_EDGE('',*,*,#892,.T.);
#894=ORIENTED_EDGE('',*,*,#868,.T.);
#895=DIRECTION('',(0.,1.,0.));
#896=VECTOR('',#895,1.);
#897=CARTESIAN_POINT('',(-43.5,-28.2727922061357,-1053.53522823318));
#898=LINE('',#897,#896);
#899=EDGE_CURVE('E1050',#861,#885,#898,.T.);
#900=ORIENTED_EDGE('',*,*,#899,.T.);
#901=EDGE_LOOP('',(#887,#893,#894,#900));
#902=FACE_BOUND('',#901,.T.);
#903=ADVANCED_FACE('F1391',(#902),#877,.F.);
#904=CARTESIAN_POINT('',(-7.5,7.5,-55.0352282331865));
#905=DIRECTION('',(0.,0.,-1.));
#906=DIRECTION('',(-1.,0.,0.));
#907=AXIS2_PLACEMENT_3D('',#904,#905,#906);
#908=CYLINDRICAL_SURFACE('',#907,36.);
#909=CARTESIAN_POINT('',(-7.5,7.5,-92.5352282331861));
#910=DIRECTION('',(-0.707106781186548,0.,-0.707106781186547));
#911=DIRECTION('',(0.707106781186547,0.,-0.707106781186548));
#912=AXIS2_PLACEMENT_3D('',#909,#910,#911);
#913=ELLIPSE('',#912,50.9116882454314,36.);
#914=CARTESIAN_POINT('',(-33.6531280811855,32.2389145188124,-66.3821001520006));
#915=VERTEX_POINT('',#914);
#916=EDGE_CURVE('E48',#883,#915,#913,.T.);
#917=ORIENTED_EDGE('',*,*,#916,.F.);
#918=ORIENTED_EDGE('',*,*,#886,.T.);
#919=CARTESIAN_POINT('',(-7.5,7.5,-1017.53522823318));
#920=DIRECTION('',(-0.707106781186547,0.,0.707106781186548));
#921=DIRECTION('',(-0.707106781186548,0.,-0.707106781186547));
#922=AXIS2_PLACEMENT_3D('',#919,#920,#921);
#923=ELLIPSE('',#922,50.9116882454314,36.);
#924=CARTESIAN_POINT('',(-33.6531280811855,32.2389145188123,-1043.68835631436));
#925=VERTEX_POINT('',#924);
#926=EDGE_CURVE('E1047',#925,#885,#923,.T.);
#927=ORIENTED_EDGE('',*,*,#926,.F.);
#928=DIRECTION('',(0.,0.,-1.));
#929=VECTOR('',#928,1.);
#930=CARTESIAN_POINT('',(-33.6531280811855,32.2389145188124,-55.0352282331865));
#931=LINE('',#930,#929);
#932=EDGE_CURVE('E786',#915,#925,#931,.T.);
#933=ORIENTED_EDGE('',*,*,#932,.F.);
#934=EDGE_LOOP('',(#917,#918,#927,#933));
#935=FACE_BOUND('',#934,.T.);
#936=ADVANCED_FACE('F1387',(#935),#908,.F.);
#937=CARTESIAN_POINT('',(-22.1464466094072,12.4999999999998,-55.0352282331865));
#938=DIRECTION('',(0.,-1.,0.));
#939=DIRECTION('',(1.,0.,0.));
#940=AXIS2_PLACEMENT_3D('',#937,#938,#939);
#941=PLANE('',#940);
#942=DIRECTION('',(0.,0.,-1.));
#943=VECTOR('',#942,1.);
#944=CARTESIAN_POINT('',(-10.6715728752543,12.4999999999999,-55.0352282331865));
#945=LINE('',#944,#943);
#946=CARTESIAN_POINT('',(-10.6715728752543,12.4999999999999,-89.3636553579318));
#947=VERTEX_POINT('',#946);
#948=CARTESIAN_POINT('',(-10.6715728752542,12.4999999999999,-1020.70680110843));
#949=VERTEX_POINT('',#948);
#950=EDGE_CURVE('E629',#947,#949,#945,.T.);
#951=ORIENTED_EDGE('',*,*,#950,.F.);
#952=DIRECTION('',(0.707106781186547,0.,-0.707106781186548));
#953=VECTOR('',#952,1.);
#954=CARTESIAN_POINT('',(-33.5732233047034,12.4999999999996,-66.4620049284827));
#955=LINE('',#954,#953);
#956=CARTESIAN_POINT('',(-7.50000000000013,12.4999999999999,-92.535228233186));
#957=VERTEX_POINT('',#956);
#958=EDGE_CURVE('E1297',#947,#957,#955,.T.);
#959=ORIENTED_EDGE('',*,*,#958,.T.);
#960=DIRECTION('',(0.,0.,-1.));
#961=VECTOR('',#960,1.);
#962=CARTESIAN_POINT('',(-7.50000000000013,12.4999999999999,-55.0352282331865));
#963=LINE('',#962,#961);
#964=CARTESIAN_POINT('',(-7.50000000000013,12.4999999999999,-1017.53522823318));
#965=VERTEX_POINT('',#964);
#966=EDGE_CURVE('E661',#957,#965,#963,.T.);
#967=ORIENTED_EDGE('',*,*,#966,.T.);
#968=DIRECTION('',(-0.707106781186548,0.,-0.707106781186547));
#969=VECTOR('',#968,1.);
#970=CARTESIAN_POINT('',(466.426776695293,12.5000000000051,-543.608451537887));
#971=LINE('',#970,#969);
#972=EDGE_CURVE('E1010',#965,#949,#971,.T.);
#973=ORIENTED_EDGE('',*,*,#972,.T.);
#974=EDGE_LOOP('',(#951,#959,#967,#973));
#975=FACE_BOUND('',#974,.T.);
#976=ADVANCED_FACE('F1390',(#975),#941,.F.);
#977=CARTESIAN_POINT('',(-10.6715728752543,13.4999999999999,-55.0352282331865));
#978=DIRECTION('',(0.,0.,-1.));
#979=DIRECTION('',(-1.,0.,0.));
#980=AXIS2_PLACEMENT_3D('',#977,#978,#979);
#981=CYLINDRICAL_SURFACE('',#980,1.);
#982=DIRECTION('',(0.,0.,-1.));
#983=VECTOR('',#982,1.);
#984=CARTESIAN_POINT('',(-11.3786796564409,12.7928932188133,-55.0352282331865));
#985=LINE('',#984,#983);
#986=CARTESIAN_POINT('',(-11.3786796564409,12.7928932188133,-88.6565485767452));
#987=VERTEX_POINT('',#986);
#988=CARTESIAN_POINT('',(-11.3786796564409,12.7928932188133,-1021.41390788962));
#989=VERTEX_POINT('',#988);
#990=EDGE_CURVE('E627',#987,#989,#985,.T.);
#991=ORIENTED_EDGE('',*,*,#990,.F.);
#992=CARTESIAN_POINT('',(-10.6715728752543,13.4999999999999,-89.3636553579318));
#993=DIRECTION('',(-0.707106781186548,0.,-0.707106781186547));
#994=DIRECTION('',(0.707106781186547,0.,-0.707106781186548));
#995=AXIS2_PLACEMENT_3D('',#992,#993,#994);
#996=ELLIPSE('',#995,1.4142135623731,1.);
#997=EDGE_CURVE('E1299',#987,#947,#996,.F.);
#998=ORIENTED_EDGE('',*,*,#997,.T.);
#999=ORIENTED_EDGE('',*,*,#950,.T.);
#1000=CARTESIAN_POINT('',(-10.6715728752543,13.4999999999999,-1020.70680110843));
#1001=DIRECTION('',(-0.707106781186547,0.,0.707106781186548));
#1002=DIRECTION('',(-0.707106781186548,0.,-0.707106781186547));
#1003=AXIS2_PLACEMENT_3D('',#1000,#1001,#1002);
#1004=ELLIPSE('',#1003,1.41421356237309,1.);
#1005=EDGE_CURVE('E1012',#949,#989,#1004,.F.);
#1006=ORIENTED_EDGE('',*,*,#1005,.T.);
#1007=EDGE_LOOP('',(#991,#998,#999,#1006));
#1008=FACE_BOUND('',#1007,.T.);
#1009=ADVANCED_FACE('F1439',(#1008),#981,.F.);
#1010=CARTESIAN_POINT('',(3.77027957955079,-2.35606601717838,-55.0352282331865));
#1011=DIRECTION('',(0.707106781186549,0.707106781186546,0.));
#1012=DIRECTION('',(-0.707106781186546,0.707106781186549,0.));
#1013=AXIS2_PLACEMENT_3D('',#1010,#1011,#1012);
#1014=PLANE('',#1013);
#1015=DIRECTION('',(-0.577350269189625,0.577350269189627,0.577350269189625));
#1016=VECTOR('',#1015,1.);
#1017=CARTESIAN_POINT('',(-12.4864802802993,13.9006938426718,-87.5487479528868));
#1018=LINE('',#1017,#1016);
#1019=CARTESIAN_POINT('',(-16.6671277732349,18.0813413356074,-83.3681004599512));
#1020=VERTEX_POINT('',#1019);
#1021=EDGE_CURVE('E1302',#987,#1020,#1018,.T.);
#1022=ORIENTED_EDGE('',*,*,#1021,.F.);
#1023=ORIENTED_EDGE('',*,*,#990,.T.);
#1024=DIRECTION('',(0.577350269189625,-0.577350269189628,0.577350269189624));
#1025=VECTOR('',#1024,1.);
#1026=CARTESIAN_POINT('',(320.84685305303,-319.432639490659,-689.188375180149));
#1027=LINE('',#1026,#1025);
#1028=CARTESIAN_POINT('',(-16.6671277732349,18.0813413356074,-1026.70235600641));
#1029=VERTEX_POINT('',#1028);
#1030=EDGE_CURVE('E1015',#1029,#989,#1027,.T.);
#1031=ORIENTED_EDGE('',*,*,#1030,.F.);
#1032=DIRECTION('',(0.,0.,-1.));
#1033=VECTOR('',#1032,1.);
#1034=CARTESIAN_POINT('',(-16.6671277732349,18.0813413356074,-55.0352282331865));
#1035=LINE('',#1034,#1033);
#1036=EDGE_CURVE('E625',#1020,#1029,#1035,.T.);
#1037=ORIENTED_EDGE('',*,*,#1036,.F.);
#1038=EDGE_LOOP('',(#1022,#1023,#1031,#1037));
#1039=FACE_BOUND('',#1038,.T.);
#1040=ADVANCED_FACE('F1446',(#1039),#1014,.T.);
#1041=CARTESIAN_POINT('',(-22.5,22.5,-55.0352282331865));
#1042=DIRECTION('',(0.,0.,-1.));
#1043=DIRECTION('',(-1.,0.,0.));
#1044=AXIS2_PLACEMENT_3D('',#1041,#1042,#1043);
#1045=CYLINDRICAL_SURFACE('',#1044,7.31757765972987);
#1046=DIRECTION('',(0.,0.,-1.));
#1047=VECTOR('',#1046,1.);
#1048=CARTESIAN_POINT('',(-16.233316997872,26.2783100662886,-55.0352282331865));
#1049=LINE('',#1048,#1047);
#1050=CARTESIAN_POINT('',(-16.233316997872,26.2783100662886,-83.8019112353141));
#1051=VERTEX_POINT('',#1050);
#1052=CARTESIAN_POINT('',(-16.233316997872,26.2783100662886,-1026.26854523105));
#1053=VERTEX_POINT('',#1052);
#1054=EDGE_CURVE('E623',#1051,#1053,#1049,.T.);
#1055=ORIENTED_EDGE('',*,*,#1054,.F.);
#1056=CARTESIAN_POINT('',(-22.5,22.5,-77.5352282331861));
#1057=DIRECTION('',(-0.707106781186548,0.,-0.707106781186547));
#1058=DIRECTION('',(0.707106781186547,0.,-0.707106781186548));
#1059=AXIS2_PLACEMENT_3D('',#1056,#1057,#1058);
#1060=ELLIPSE('',#1059,10.3486175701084,7.31757765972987);
#1061=EDGE_CURVE('E1304',#1051,#1020,#1060,.T.);
#1062=ORIENTED_EDGE('',*,*,#1061,.T.);
#1063=ORIENTED_EDGE('',*,*,#1036,.T.);
#1064=CARTESIAN_POINT('',(-22.5,22.5,-1032.53522823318));
#1065=DIRECTION('',(-0.707106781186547,0.,0.707106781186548));
#1066=DIRECTION('',(-0.707106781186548,0.,-0.707106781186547));
#1067=AXIS2_PLACEMENT_3D('',#1064,#1065,#1066);
#1068=ELLIPSE('',#1067,10.3486175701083,7.31757765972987);
#1069=EDGE_CURVE('E1018',#1029,#1053,#1068,.T.);
#1070=ORIENTED_EDGE('',*,*,#1069,.T.);
#1071=EDGE_LOOP('',(#1055,#1062,#1063,#1070));
#1072=FACE_BOUND('',#1071,.T.);
#1073=ADVANCED_FACE('F1454',(#1072),#1045,.T.);
#1074=CARTESIAN_POINT('',(-15.3769293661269,26.7946435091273,-55.0352282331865));
#1075=DIRECTION('',(0.,0.,-1.));
#1076=DIRECTION('',(-1.,0.,0.));
#1077=AXIS2_PLACEMENT_3D('',#1074,#1075,#1076);
#1078=CYLINDRICAL_SURFACE('',#1077,1.);
#1079=DIRECTION('',(0.,0.,-1.));
#1080=VECTOR('',#1079,1.);
#1081=CARTESIAN_POINT('',(-16.0840361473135,27.5017502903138,-55.0352282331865));
#1082=LINE('',#1081,#1080);
#1083=CARTESIAN_POINT('',(-16.0840361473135,27.5017502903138,-83.9511920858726));
#1084=VERTEX_POINT('',#1083);
#1085=CARTESIAN_POINT('',(-16.0840361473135,27.5017502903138,-1026.11926438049));
#1086=VERTEX_POINT('',#1085);
#1087=EDGE_CURVE('E621',#1084,#1086,#1082,.T.);
#1088=ORIENTED_EDGE('',*,*,#1087,.F.);
#1089=CARTESIAN_POINT('',(-15.3769293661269,26.7946435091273,-84.6582988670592));
#1090=DIRECTION('',(-0.707106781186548,0.,-0.707106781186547));
#1091=DIRECTION('',(0.707106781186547,0.,-0.707106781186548));
#1092=AXIS2_PLACEMENT_3D('',#1089,#1090,#1091);
#1093=ELLIPSE('',#1092,1.4142135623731,1.);
#1094=EDGE_CURVE('E1307',#1084,#1051,#1093,.F.);
#1095=ORIENTED_EDGE('',*,*,#1094,.T.);
#1096=ORIENTED_EDGE('',*,*,#1054,.T.);
#1097=CARTESIAN_POINT('',(-15.3769293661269,26.7946435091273,-1025.41215759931));
#1098=DIRECTION('',(-0.707106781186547,0.,0.707106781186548));
#1099=DIRECTION('',(-0.707106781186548,0.,-0.707106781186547));
#1100=AXIS2_PLACEMENT_3D('',#1097,#1098,#1099);
#1101=ELLIPSE('',#1100,1.41421356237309,1.);
#1102=EDGE_CURVE('E1021',#1053,#1086,#1101,.F.);
#1103=ORIENTED_EDGE('',*,*,#1102,.T.);
#1104=EDGE_LOOP('',(#1088,#1095,#1096,#1103));
#1105=FACE_BOUND('',#1104,.T.);
#1106=ADVANCED_FACE('F1462',(#1105),#1078,.F.);
#1107=CARTESIAN_POINT('',(-47.0025126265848,-3.41672618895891,-55.0352282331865));
#1108=DIRECTION('',(-0.707106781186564,0.707106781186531,0.));
#1109=DIRECTION('',(-0.707106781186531,-0.707106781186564,0.));
#1110=AXIS2_PLACEMENT_3D('',#1107,#1108,#1109);
#1111=PLANE('',#1110);
#1112=DIRECTION('',(0.,0.,-1.));
#1113=VECTOR('',#1112,1.);
#1114=CARTESIAN_POINT('',(-11.3786796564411,32.2071067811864,-55.0352282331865));
#1115=LINE('',#1114,#1113);
#1116=CARTESIAN_POINT('',(-11.3786796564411,32.2071067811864,-88.656548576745));
#1117=VERTEX_POINT('',#1116);
#1118=CARTESIAN_POINT('',(-11.3786796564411,32.2071067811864,-1021.41390788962));
#1119=VERTEX_POINT('',#1118);
#1120=EDGE_CURVE('E619',#1117,#1119,#1115,.T.);
#1121=ORIENTED_EDGE('',*,*,#1120,.F.);
#1122=DIRECTION('',(-0.577350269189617,-0.577350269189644,0.577350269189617));
#1123=VECTOR('',#1122,1.);
#1124=CARTESIAN_POINT('',(-46.335008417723,-2.74922198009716,-53.700219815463));
#1125=LINE('',#1124,#1123);
#1126=EDGE_CURVE('E1310',#1117,#1084,#1125,.T.);
#1127=ORIENTED_EDGE('',*,*,#1126,.T.);
#1128=ORIENTED_EDGE('',*,*,#1087,.T.);
#1129=DIRECTION('',(0.577350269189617,0.577350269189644,0.577350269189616));
#1130=VECTOR('',#1129,1.);
#1131=CARTESIAN_POINT('',(286.998324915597,330.584111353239,-723.036903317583));
#1132=LINE('',#1131,#1130);
#1133=EDGE_CURVE('E1024',#1086,#1119,#1132,.T.);
#1134=ORIENTED_EDGE('',*,*,#1133,.T.);
#1135=EDGE_LOOP('',(#1121,#1127,#1128,#1134));
#1136=FACE_BOUND('',#1135,.T.);
#1137=ADVANCED_FACE('F1470',(#1136),#1111,.F.);
#1138=CARTESIAN_POINT('',(-10.6715728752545,31.4999999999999,-55.0352282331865));
#1139=DIRECTION('',(0.,0.,-1.));
#1140=DIRECTION('',(-1.,0.,0.));
#1141=AXIS2_PLACEMENT_3D('',#1138,#1139,#1140);
#1142=CYLINDRICAL_SURFACE('',#1141,0.999999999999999);
#1143=CARTESIAN_POINT('',(-10.6715728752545,31.4999999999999,-89.3636553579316));
#1144=DIRECTION('',(-0.707106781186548,0.,-0.707106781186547));
#1145=DIRECTION('',(0.707106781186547,0.,-0.707106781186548));
#1146=AXIS2_PLACEMENT_3D('',#1143,#1144,#1145);
#1147=ELLIPSE('',#1146,1.41421356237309,0.999999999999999);
#1148=CARTESIAN_POINT('',(-10.6715728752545,32.4999999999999,-89.3636553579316));
#1149=VERTEX_POINT('',#1148);
#1150=EDGE_CURVE('E1313',#1117,#1149,#1147,.T.);
#1151=ORIENTED_EDGE('',*,*,#1150,.F.);
#1152=ORIENTED_EDGE('',*,*,#1120,.T.);
#1153=CARTESIAN_POINT('',(-10.6715728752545,31.4999999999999,-1020.70680110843));
#1154=DIRECTION('',(-0.707106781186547,0.,0.707106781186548));
#1155=DIRECTION('',(-0.707106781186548,0.,-0.707106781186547));
#1156=AXIS2_PLACEMENT_3D('',#1153,#1154,#1155);
#1157=ELLIPSE('',#1156,1.41421356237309,0.999999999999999);
#1158=CARTESIAN_POINT('',(-10.6715728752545,32.4999999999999,-1020.70680110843));
#1159=VERTEX_POINT('',#1158);
#1160=EDGE_CURVE('E1027',#1159,#1119,#1157,.T.);
#1161=ORIENTED_EDGE('',*,*,#1160,.F.);
#1162=DIRECTION('',(0.,0.,-1.));
#1163=VECTOR('',#1162,1.);
#1164=CARTESIAN_POINT('',(-10.6715728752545,32.4999999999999,-55.0352282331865));
#1165=LINE('',#1164,#1163);
#1166=EDGE_CURVE('E617',#1149,#1159,#1165,.T.);
#1167=ORIENTED_EDGE('',*,*,#1166,.F.);
#1168=EDGE_LOOP('',(#1151,#1152,#1161,#1167));
#1169=FACE_BOUND('',#1168,.T.);
#1170=ADVANCED_FACE('F1478',(#1169),#1142,.F.);
#1171=CARTESIAN_POINT('',(-22.1464466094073,32.4999999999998,-55.0352282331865));
#1172=DIRECTION('',(0.,-1.,0.));
#1173=DIRECTION('',(1.,0.,0.));
#1174=AXIS2_PLACEMENT_3D('',#1171,#1172,#1173);
#1175=PLANE('',#1174);
#1176=DIRECTION('',(0.707106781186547,0.,-0.707106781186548));
#1177=VECTOR('',#1176,1.);
#1178=CARTESIAN_POINT('',(-33.5732233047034,32.4999999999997,-66.4620049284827));
#1179=LINE('',#1178,#1177);
#1180=CARTESIAN_POINT('',(-7.50000000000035,32.4999999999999,-92.5352282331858));
#1181=VERTEX_POINT('',#1180);
#1182=EDGE_CURVE('E1315',#1149,#1181,#1179,.T.);
#1183=ORIENTED_EDGE('',*,*,#1182,.F.);
#1184=ORIENTED_EDGE('',*,*,#1166,.T.);
#1185=DIRECTION('',(-0.707106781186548,0.,-0.707106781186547));
#1186=VECTOR('',#1185,1.);
#1187=CARTESIAN_POINT('',(466.426776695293,32.5000000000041,-543.608451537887));
#1188=LINE('',#1187,#1186);
#1189=CARTESIAN_POINT('',(-7.50000000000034,32.4999999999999,-1017.53522823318));
#1190=VERTEX_POINT('',#1189);
#1191=EDGE_CURVE('E1030',#1190,#1159,#1188,.T.);
#1192=ORIENTED_EDGE('',*,*,#1191,.F.);
#1193=DIRECTION('',(0.,0.,-1.));
#1194=VECTOR('',#1193,1.);
#1195=CARTESIAN_POINT('',(-7.50000000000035,32.4999999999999,-55.0352282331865));
#1196=LINE('',#1195,#1194);
#1197=EDGE_CURVE('E615',#1181,#1190,#1196,.T.);
#1198=ORIENTED_EDGE('',*,*,#1197,.F.);
#1199=EDGE_LOOP('',(#1183,#1184,#1192,#1198));
#1200=FACE_BOUND('',#1199,.T.);
#1201=ADVANCED_FACE('F1486',(#1200),#1175,.T.);
#1202=CARTESIAN_POINT('',(-7.49999999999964,-28.2727922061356,-55.0352282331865));
#1203=DIRECTION('',(1.,0.,0.));
#1204=DIRECTION('',(0.,1.,0.));
#1205=AXIS2_PLACEMENT_3D('',#1202,#1203,#1204);
#1206=PLANE('',#1205);
#1207=DIRECTION('',(0.,0.,-1.));
#1208=VECTOR('',#1207,1.);
#1209=CARTESIAN_POINT('',(-7.5000000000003,27.4999999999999,-55.0352282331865));
#1210=LINE('',#1209,#1208);
#1211=CARTESIAN_POINT('',(-7.5000000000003,27.4999999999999,-92.5352282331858));
#1212=VERTEX_POINT('',#1211);
#1213=CARTESIAN_POINT('',(-7.5000000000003,27.4999999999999,-1017.53522823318));
#1214=VERTEX_POINT('',#1213);
#1215=EDGE_CURVE('E613',#1212,#1214,#1210,.T.);
#1216=ORIENTED_EDGE('',*,*,#1215,.F.);
#1217=DIRECTION('',(0.,1.,0.));
#1218=VECTOR('',#1217,1.);
#1219=CARTESIAN_POINT('',(-7.49999999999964,-28.2727922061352,-92.5352282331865));
#1220=LINE('',#1219,#1218);
#1221=EDGE_CURVE('E1317',#1212,#1181,#1220,.T.);
#1222=ORIENTED_EDGE('',*,*,#1221,.T.);
#1223=ORIENTED_EDGE('',*,*,#1197,.T.);
#1224=DIRECTION('',(0.,-1.,0.));
#1225=VECTOR('',#1224,1.);
#1226=CARTESIAN_POINT('',(-7.49999999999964,-28.2727922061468,-1017.53522823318));
#1227=LINE('',#1226,#1225);
#1228=EDGE_CURVE('E1033',#1190,#1214,#1227,.T.);
#1229=ORIENTED_EDGE('',*,*,#1228,.T.);
#1230=EDGE_LOOP('',(#1216,#1222,#1223,#1229));
#1231=FACE_BOUND('',#1230,.T.);
#1232=ADVANCED_FACE('F1494',(#1231),#1206,.F.);
#1233=CARTESIAN_POINT('',(-22.1464466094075,27.4999999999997,-55.0352282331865));
#1234=DIRECTION('',(0.,-1.,0.));
#1235=DIRECTION('',(1.,0.,0.));
#1236=AXIS2_PLACEMENT_3D('',#1233,#1234,#1235);
#1237=PLANE('',#1236);
#1238=DIRECTION('',(0.707106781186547,0.,-0.707106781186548));
#1239=VECTOR('',#1238,1.);
#1240=CARTESIAN_POINT('',(-33.5732233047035,27.4999999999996,-66.4620049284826));
#1241=LINE('',#1240,#1239);
#1242=CARTESIAN_POINT('',(-1.49999999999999,27.5,-98.5352282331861));
#1243=VERTEX_POINT('',#1242);
#1244=EDGE_CURVE('E1320',#1212,#1243,#1241,.T.);
#1245=ORIENTED_EDGE('',*,*,#1244,.F.);
#1246=ORIENTED_EDGE('',*,*,#1215,.T.);
#1247=DIRECTION('',(-0.707106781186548,0.,-0.707106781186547));
#1248=VECTOR('',#1247,1.);
#1249=CARTESIAN_POINT('',(466.426776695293,27.5000000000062,-543.608451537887));
#1250=LINE('',#1249,#1248);
#1251=CARTESIAN_POINT('',(-1.50000000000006,27.5,-1011.53522823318));
#1252=VERTEX_POINT('',#1251);
#1253=EDGE_CURVE('E1036',#1252,#1214,#1250,.T.);
#1254=ORIENTED_EDGE('',*,*,#1253,.F.);
#1255=DIRECTION('',(0.,0.,-1.));
#1256=VECTOR('',#1255,1.);
#1257=CARTESIAN_POINT('',(-1.5,27.5,-55.0352282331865));
#1258=LINE('',#1257,#1256);
#1259=EDGE_CURVE('E611',#1243,#1252,#1258,.T.);
#1260=ORIENTED_EDGE('',*,*,#1259,.F.);
#1261=EDGE_LOOP('',(#1245,#1246,#1254,#1260));
#1262=FACE_BOUND('',#1261,.T.);
#1263=ADVANCED_FACE('F1502',(#1262),#1237,.T.);
#1264=CARTESIAN_POINT('',(-1.5,-28.2727922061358,-55.0352282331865));
#1265=DIRECTION('',(-1.,0.,0.));
#1266=DIRECTION('',(0.,0.,1.));
#1267=AXIS2_PLACEMENT_3D('',#1264,#1265,#1266);
#1268=PLANE('',#1267);
#1269=DIRECTION('',(0.,0.,-1.));
#1270=VECTOR('',#1269,1.);
#1271=CARTESIAN_POINT('',(-1.5,29.,-55.0352282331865));
#1272=LINE('',#1271,#1270);
#1273=CARTESIAN_POINT('',(-1.5,29.,-98.5352282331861));
#1274=VERTEX_POINT('',#1273);
#1275=CARTESIAN_POINT('',(-1.5,29.,-1011.53522823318));
#1276=VERTEX_POINT('',#1275);
#1277=EDGE_CURVE('E609',#1274,#1276,#1272,.T.);
#1278=ORIENTED_EDGE('',*,*,#1277,.F.);
#1279=DIRECTION('',(0.,-1.,0.));
#1280=VECTOR('',#1279,1.);
#1281=CARTESIAN_POINT('',(-1.5,-28.2727922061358,-98.5352282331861));
#1282=LINE('',#1281,#1280);
#1283=EDGE_CURVE('E1322',#1274,#1243,#1282,.T.);
#1284=ORIENTED_EDGE('',*,*,#1283,.T.);
#1285=ORIENTED_EDGE('',*,*,#1259,.T.);
#1286=DIRECTION('',(0.,1.,0.));
#1287=VECTOR('',#1286,1.);
#1288=CARTESIAN_POINT('',(-1.5,-28.2727922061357,-1011.53522823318));
#1289=LINE('',#1288,#1287);
#1290=EDGE_CURVE('E1039',#1252,#1276,#1289,.T.);
#1291=ORIENTED_EDGE('',*,*,#1290,.T.);
#1292=EDGE_LOOP('',(#1278,#1284,#1285,#1291));
#1293=FACE_BOUND('',#1292,.T.);
#1294=ADVANCED_FACE('F1510',(#1293),#1268,.F.);
#1295=CARTESIAN_POINT('',(-22.1464466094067,29.,-55.0352282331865));
#1296=DIRECTION('',(0.,-1.,0.));
#1297=DIRECTION('',(0.,0.,-1.));
#1298=AXIS2_PLACEMENT_3D('',#1295,#1296,#1297);
#1299=PLANE('',#1298);
#1300=DIRECTION('',(0.707106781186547,0.,-0.707106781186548));
#1301=VECTOR('',#1300,1.);
#1302=CARTESIAN_POINT('',(-33.5732233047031,29.,-66.4620049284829));
#1303=LINE('',#1302,#1301);
#1304=CARTESIAN_POINT('',(0.,29.,-100.035228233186));
#1305=VERTEX_POINT('',#1304);
#1306=EDGE_CURVE('E1325',#1274,#1305,#1303,.T.);
#1307=ORIENTED_EDGE('',*,*,#1306,.F.);
#1308=ORIENTED_EDGE('',*,*,#1277,.T.);
#1309=DIRECTION('',(-0.707106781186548,0.,-0.707106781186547));
#1310=VECTOR('',#1309,1.);
#1311=CARTESIAN_POINT('',(466.426776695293,29.,-543.608451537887));
#1312=LINE('',#1311,#1310);
#1313=CARTESIAN_POINT('',(0.,29.,-1010.03522823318));
#1314=VERTEX_POINT('',#1313);
#1315=EDGE_CURVE('E1042',#1314,#1276,#1312,.T.);
#1316=ORIENTED_EDGE('',*,*,#1315,.F.);
#1317=DIRECTION('',(0.,0.,-1.));
#1318=VECTOR('',#1317,1.);
#1319=CARTESIAN_POINT('',(-2.91189469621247E-13,29.,-55.0352282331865));
#1320=LINE('',#1319,#1318);
#1321=EDGE_CURVE('E607',#1305,#1314,#1320,.T.);
#1322=ORIENTED_EDGE('',*,*,#1321,.F.);
#1323=EDGE_LOOP('',(#1307,#1308,#1316,#1322));
#1324=FACE_BOUND('',#1323,.T.);
#1325=ADVANCED_FACE('F1518',(#1324),#1299,.T.);
#1326=CARTESIAN_POINT('',(-1.57512891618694E-12,-28.2727922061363,-55.0352282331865));
#1327=DIRECTION('',(-1.,0.,0.));
#1328=DIRECTION('',(0.,-1.,0.));
#1329=AXIS2_PLACEMENT_3D('',#1326,#1327,#1328);
#1330=PLANE('',#1329);
#1331=DIRECTION('',(0.,0.,-1.));
#1332=VECTOR('',#1331,1.);
#1333=CARTESIAN_POINT('',(0.,42.,-55.0352282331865));
#1334=LINE('',#1333,#1332);
#1335=CARTESIAN_POINT('',(0.,42.,-100.035228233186));
#1336=VERTEX_POINT('',#1335);
#1337=CARTESIAN_POINT('',(0.,42.,-1010.03522823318));
#1338=VERTEX_POINT('',#1337);
#1339=EDGE_CURVE('E605',#1336,#1338,#1334,.T.);
#1340=ORIENTED_EDGE('',*,*,#1339,.F.);
#1341=DIRECTION('',(0.,-1.,0.));
#1342=VECTOR('',#1341,1.);
#1343=CARTESIAN_POINT('',(0.,74.3573124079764,-100.035228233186));
#1344=LINE('',#1343,#1342);
#1345=EDGE_CURVE('E1210',#1336,#1305,#1344,.T.);
#1346=ORIENTED_EDGE('',*,*,#1345,.T.);
#1347=ORIENTED_EDGE('',*,*,#1321,.T.);
#1348=DIRECTION('',(0.,-1.,0.));
#1349=VECTOR('',#1348,1.);
#1350=CARTESIAN_POINT('',(0.,74.3573124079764,-1010.03522823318));
#1351=LINE('',#1350,#1349);
#1352=EDGE_CURVE('E909',#1338,#1314,#1351,.T.);
#1353=ORIENTED_EDGE('',*,*,#1352,.F.);
#1354=EDGE_LOOP('',(#1340,#1346,#1347,#1353));
#1355=FACE_BOUND('',#1354,.T.);
#1356=ADVANCED_FACE('F1526',(#1355),#1330,.F.);
#1357=CARTESIAN_POINT('',(-3.,42.,-55.0352282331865));
#1358=DIRECTION('',(0.,0.,-1.));
#1359=DIRECTION('',(-1.,0.,0.));
#1360=AXIS2_PLACEMENT_3D('',#1357,#1358,#1359);
#1361=CYLINDRICAL_SURFACE('',#1360,3.);
#1362=DIRECTION('',(0.,0.,-1.));
#1363=VECTOR('',#1362,1.);
#1364=CARTESIAN_POINT('',(-3.00000000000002,45.,-55.0352282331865));
#1365=LINE('',#1364,#1363);
#1366=CARTESIAN_POINT('',(-3.00000000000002,45.,-97.0352282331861));
#1367=VERTEX_POINT('',#1366);
#1368=CARTESIAN_POINT('',(-2.99999999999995,45.,-1013.03522823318));
#1369=VERTEX_POINT('',#1368);
#1370=EDGE_CURVE('E603',#1367,#1369,#1365,.T.);
#1371=ORIENTED_EDGE('',*,*,#1370,.F.);
#1372=CARTESIAN_POINT('',(-3.,42.,-97.0352282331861));
#1373=DIRECTION('',(-0.707106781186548,0.,-0.707106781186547));
#1374=DIRECTION('',(0.707106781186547,0.,-0.707106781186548));
#1375=AXIS2_PLACEMENT_3D('',#1372,#1373,#1374);
#1376=ELLIPSE('',#1375,4.24264068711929,3.);
#1377=EDGE_CURVE('E900',#1367,#1336,#1376,.T.);
#1378=ORIENTED_EDGE('',*,*,#1377,.T.);
#1379=ORIENTED_EDGE('',*,*,#1339,.T.);
#1380=CARTESIAN_POINT('',(-3.,42.,-1013.03522823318));
#1381=DIRECTION('',(-0.707106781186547,0.,0.707106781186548));
#1382=DIRECTION('',(-0.707106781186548,0.,-0.707106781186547));
#1383=AXIS2_PLACEMENT_3D('',#1380,#1381,#1382);
#1384=ELLIPSE('',#1383,4.24264068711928,3.);
#1385=EDGE_CURVE('E750',#1338,#1369,#1384,.T.);
#1386=ORIENTED_EDGE('',*,*,#1385,.T.);
#1387=EDGE_LOOP('',(#1371,#1378,#1379,#1386));
#1388=FACE_BOUND('',#1387,.T.);
#1389=ADVANCED_FACE('F1534',(#1388),#1361,.T.);
#1390=CARTESIAN_POINT('',(-22.1464466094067,45.,-55.0352282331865));
#1391=DIRECTION('',(0.,-1.,0.));
#1392=DIRECTION('',(0.,0.,-1.));
#1393=AXIS2_PLACEMENT_3D('',#1390,#1391,#1392);
#1394=PLANE('',#1393);
#1395=DIRECTION('',(0.,0.,-1.));
#1396=VECTOR('',#1395,1.);
#1397=CARTESIAN_POINT('',(-7.5,45.,-55.0352282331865));
#1398=LINE('',#1397,#1396);
#1399=CARTESIAN_POINT('',(-7.5,45.,-92.5352282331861));
#1400=VERTEX_POINT('',#1399);
#1401=CARTESIAN_POINT('',(-7.5,45.,-1017.53522823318));
#1402=VERTEX_POINT('',#1401);
#1403=EDGE_CURVE('E601',#1400,#1402,#1398,.T.);
#1404=ORIENTED_EDGE('',*,*,#1403,.F.);
#1405=DIRECTION('',(0.707106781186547,0.,-0.707106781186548));
#1406=VECTOR('',#1405,1.);
#1407=CARTESIAN_POINT('',(-33.5732233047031,45.,-66.4620049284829));
#1408=LINE('',#1407,#1406);
#1409=EDGE_CURVE('E897',#1400,#1367,#1408,.T.);
#1410=ORIENTED_EDGE('',*,*,#1409,.T.);
#1411=ORIENTED_EDGE('',*,*,#1370,.T.);
#1412=DIRECTION('',(-0.707106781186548,0.,-0.707106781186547));
#1413=VECTOR('',#1412,1.);
#1414=CARTESIAN_POINT('',(466.426776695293,45.,-543.608451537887));
#1415=LINE('',#1414,#1413);
#1416=EDGE_CURVE('E747',#1369,#1402,#1415,.T.);
#1417=ORIENTED_EDGE('',*,*,#1416,.T.);
#1418=EDGE_LOOP('',(#1404,#1410,#1411,#1417));
#1419=FACE_BOUND('',#1418,.T.);
#1420=ADVANCED_FACE('F1542',(#1419),#1394,.F.);
#1421=CARTESIAN_POINT('',(-7.5,7.5,-55.0352282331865));
#1422=DIRECTION('',(0.,0.,-1.));
#1423=DIRECTION('',(-1.,0.,0.));
#1424=AXIS2_PLACEMENT_3D('',#1421,#1422,#1423);
#1425=CYLINDRICAL_SURFACE('',#1424,37.5);
#1426=DIRECTION('',(0.,0.,-1.));
#1427=VECTOR('',#1426,1.);
#1428=CARTESIAN_POINT('',(-45.,7.5,-55.0352282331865));
#1429=LINE('',#1428,#1427);
#1430=CARTESIAN_POINT('',(-45.,7.5,-55.0352282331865));
#1431=VERTEX_POINT('',#1430);
#1432=CARTESIAN_POINT('',(-45.,7.50000000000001,-1055.03522823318));
#1433=VERTEX_POINT('',#1432);
#1434=EDGE_CURVE('E593',#1431,#1433,#1429,.T.);
#1435=ORIENTED_EDGE('',*,*,#1434,.F.);
#1436=CARTESIAN_POINT('',(-7.5,7.5,-92.5352282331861));
#1437=DIRECTION('',(-0.707106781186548,0.,-0.707106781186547));
#1438=DIRECTION('',(0.707106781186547,0.,-0.707106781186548));
#1439=AXIS2_PLACEMENT_3D('',#1436,#1437,#1438);
#1440=ELLIPSE('',#1439,53.0330085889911,37.5);
#1441=EDGE_CURVE('E575',#1431,#1400,#1440,.T.);
#1442=ORIENTED_EDGE('',*,*,#1441,.T.);
#1443=ORIENTED_EDGE('',*,*,#1403,.T.);
#1444=CARTESIAN_POINT('',(-7.5,7.5,-1017.53522823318));
#1445=DIRECTION('',(-0.707106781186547,0.,0.707106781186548));
#1446=DIRECTION('',(-0.707106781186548,0.,-0.707106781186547));
#1447=AXIS2_PLACEMENT_3D('',#1444,#1445,#1446);
#1448=ELLIPSE('',#1447,53.033008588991,37.5);
#1449=EDGE_CURVE('E741',#1402,#1433,#1448,.T.);
#1450=ORIENTED_EDGE('',*,*,#1449,.T.);
#1451=EDGE_LOOP('',(#1435,#1442,#1443,#1450));
#1452=FACE_BOUND('',#1451,.T.);
#1453=ADVANCED_FACE('F1550',(#1452),#1425,.T.);
#1454=CARTESIAN_POINT('',(-45.,-28.2727922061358,-55.0352282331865));
#1455=DIRECTION('',(-1.,0.,0.));
#1456=DIRECTION('',(0.,0.,1.));
#1457=AXIS2_PLACEMENT_3D('',#1454,#1455,#1456);
#1458=PLANE('',#1457);
#1459=DIRECTION('',(0.,1.,0.));
#1460=VECTOR('',#1459,1.);
#1461=CARTESIAN_POINT('',(-45.,-28.2727922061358,-1055.03522823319));
#1462=LINE('',#1461,#1460);
#1463=CARTESIAN_POINT('',(-45.,3.00000000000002,-1055.03522823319));
#1464=VERTEX_POINT('',#1463);
#1465=EDGE_CURVE('E753',#1464,#1433,#1462,.T.);
#1466=ORIENTED_EDGE('',*,*,#1465,.F.);
#1467=DIRECTION('',(0.,0.,-1.));
#1468=VECTOR('',#1467,1.);
#1469=CARTESIAN_POINT('',(-45.,3.00000000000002,-55.0352282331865));
#1470=LINE('',#1469,#1468);
#1471=CARTESIAN_POINT('',(-45.,3.00000000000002,-55.0352282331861));
#1472=VERTEX_POINT('',#1471);
#1473=EDGE_CURVE('E591',#1472,#1464,#1470,.T.);
#1474=ORIENTED_EDGE('',*,*,#1473,.F.);
#1475=DIRECTION('',(0.,1.,0.));
#1476=VECTOR('',#1475,1.);
#1477=CARTESIAN_POINT('',(-45.,-28.2727922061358,-55.0352282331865));
#1478=LINE('',#1477,#1476);
#1479=EDGE_CURVE('E570',#1472,#1431,#1478,.T.);
#1480=ORIENTED_EDGE('',*,*,#1479,.T.);
#1481=ORIENTED_EDGE('',*,*,#1434,.T.);
#1482=EDGE_LOOP('',(#1466,#1474,#1480,#1481));
#1483=FACE_BOUND('',#1482,.T.);
#1484=ADVANCED_FACE('F1558',(#1483),#1458,.T.);
#1485=CARTESIAN_POINT('',(-42.,2.99999999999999,-55.0352282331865));
#1486=DIRECTION('',(0.,0.,-1.));
#1487=DIRECTION('',(-1.,0.,0.));
#1488=AXIS2_PLACEMENT_3D('',#1485,#1486,#1487);
#1489=CYLINDRICAL_SURFACE('',#1488,3.);
#1490=DIRECTION('',(0.,0.,-1.));
#1491=VECTOR('',#1490,1.);
#1492=CARTESIAN_POINT('',(-42.,0.,-55.0352282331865));
#1493=LINE('',#1492,#1491);
#1494=CARTESIAN_POINT('',(-42.,0.,-58.0352282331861));
#1495=VERTEX_POINT('',#1494);
#1496=CARTESIAN_POINT('',(-41.9999999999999,0.,-1052.03522823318));
#1497=VERTEX_POINT('',#1496);
#1498=EDGE_CURVE('E582',#1495,#1497,#1493,.T.);
#1499=ORIENTED_EDGE('',*,*,#1498,.F.);
#1500=CARTESIAN_POINT('',(-42.,2.99999999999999,-58.0352282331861));
#1501=DIRECTION('',(-0.707106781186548,0.,-0.707106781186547));
#1502=DIRECTION('',(0.707106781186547,0.,-0.707106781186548));
#1503=AXIS2_PLACEMENT_3D('',#1500,#1501,#1502);
#1504=ELLIPSE('',#1503,4.24264068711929,3.);
#1505=EDGE_CURVE('E564',#1495,#1472,#1504,.T.);
#1506=ORIENTED_EDGE('',*,*,#1505,.T.);
#1507=ORIENTED_EDGE('',*,*,#1473,.T.);
#1508=CARTESIAN_POINT('',(-42.,2.99999999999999,-1052.03522823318));
#1509=DIRECTION('',(-0.707106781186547,0.,0.707106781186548));
#1510=DIRECTION('',(-0.707106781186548,0.,-0.707106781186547));
#1511=AXIS2_PLACEMENT_3D('',#1508,#1509,#1510);
#1512=ELLIPSE('',#1511,4.24264068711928,3.);
#1513=EDGE_CURVE('E590',#1464,#1497,#1512,.T.);
#1514=ORIENTED_EDGE('',*,*,#1513,.T.);
#1515=EDGE_LOOP('',(#1499,#1506,#1507,#1514));
#1516=FACE_BOUND('',#1515,.T.);
#1517=ADVANCED_FACE('F589',(#1516),#1489,.T.);
#1518=CARTESIAN_POINT('',(-22.1464466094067,0.,-55.0352282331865));
#1519=DIRECTION('',(0.,-1.,0.));
#1520=DIRECTION('',(1.,0.,0.));
#1521=AXIS2_PLACEMENT_3D('',#1518,#1519,#1520);
#1522=PLANE('',#1521);
#1523=DIRECTION('',(0.707106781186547,0.,-0.707106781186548));
#1524=VECTOR('',#1523,1.);
#1525=CARTESIAN_POINT('',(-45.,0.,-55.0352282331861));
#1526=LINE('',#1525,#1524);
#1527=CARTESIAN_POINT('',(-29.,0.,-71.0352282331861));
#1528=VERTEX_POINT('',#1527);
#1529=EDGE_CURVE('E567',#1495,#1528,#1526,.T.);
#1530=ORIENTED_EDGE('',*,*,#1529,.F.);
#1531=ORIENTED_EDGE('',*,*,#1498,.T.);
#1532=DIRECTION('',(-0.707106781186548,0.,-0.707106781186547));
#1533=VECTOR('',#1532,1.);
#1534=CARTESIAN_POINT('',(-45.,0.,-1055.03522823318));
#1535=LINE('',#1534,#1533);
#1536=CARTESIAN_POINT('',(-29.,0.,-1039.03522823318));
#1537=VERTEX_POINT('',#1536);
#1538=EDGE_CURVE('E903',#1537,#1497,#1535,.T.);
#1539=ORIENTED_EDGE('',*,*,#1538,.F.);
#1540=DIRECTION('',(0.,0.,-1.));
#1541=VECTOR('',#1540,1.);
#1542=CARTESIAN_POINT('',(-29.,0.,-55.0352282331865));
#1543=LINE('',#1542,#1541);
#1544=EDGE_CURVE('E584',#1528,#1537,#1543,.T.);
#1545=ORIENTED_EDGE('',*,*,#1544,.F.);
#1546=EDGE_LOOP('',(#1530,#1531,#1539,#1545));
#1547=FACE_BOUND('',#1546,.T.);
#1548=ADVANCED_FACE('F580',(#1547),#1522,.T.);
#1549=CARTESIAN_POINT('',(-29.,-28.2727922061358,-55.0352282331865));
#1550=DIRECTION('',(1.,0.,0.));
#1551=DIRECTION('',(0.,0.,-1.));
#1552=AXIS2_PLACEMENT_3D('',#1549,#1550,#1551);
#1553=PLANE('',#1552);
#1554=DIRECTION('',(0.,1.,0.));
#1555=VECTOR('',#1554,1.);
#1556=CARTESIAN_POINT('',(-29.,-28.2727922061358,-71.0352282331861));
#1557=LINE('',#1556,#1555);
#1558=CARTESIAN_POINT('',(-29.,1.5,-71.0352282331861));
#1559=VERTEX_POINT('',#1558);
#1560=EDGE_CURVE('E576',#1528,#1559,#1557,.T.);
#1561=ORIENTED_EDGE('',*,*,#1560,.F.);
#1562=ORIENTED_EDGE('',*,*,#1544,.T.);
#1563=DIRECTION('',(0.,-1.,0.));
#1564=VECTOR('',#1563,1.);
#1565=CARTESIAN_POINT('',(-29.,-28.2727922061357,-1039.03522823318));
#1566=LINE('',#1565,#1564);
#1567=CARTESIAN_POINT('',(-29.,1.5,-1039.03522823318));
#1568=VERTEX_POINT('',#1567);
#1569=EDGE_CURVE('E734',#1568,#1537,#1566,.T.);
#1570=ORIENTED_EDGE('',*,*,#1569,.F.);
#1571=DIRECTION('',(0.,0.,-1.));
#1572=VECTOR('',#1571,1.);
#1573=CARTESIAN_POINT('',(-29.,1.5,-55.0352282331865));
#1574=LINE('',#1573,#1572);
#1575=EDGE_CURVE('E595',#1559,#1568,#1574,.T.);
#1576=ORIENTED_EDGE('',*,*,#1575,.F.);
#1577=EDGE_LOOP('',(#1561,#1562,#1570,#1576));
#1578=FACE_BOUND('',#1577,.T.);
#1579=ADVANCED_FACE('F739',(#1578),#1553,.T.);
#1580=CARTESIAN_POINT('',(-22.1464466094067,1.5,-55.0352282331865));
#1581=DIRECTION('',(0.,-1.,0.));
#1582=DIRECTION('',(0.,0.,-1.));
#1583=AXIS2_PLACEMENT_3D('',#1580,#1581,#1582);
#1584=PLANE('',#1583);
#1585=DIRECTION('',(0.707106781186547,0.,-0.707106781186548));
#1586=VECTOR('',#1585,1.);
#1587=CARTESIAN_POINT('',(-33.5732233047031,1.5,-66.4620049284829));
#1588=LINE('',#1587,#1586);
#1589=CARTESIAN_POINT('',(-27.5,1.5,-72.5352282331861));
#1590=VERTEX_POINT('',#1589);
#1591=EDGE_CURVE('E726',#1559,#1590,#1588,.T.);
#1592=ORIENTED_EDGE('',*,*,#1591,.F.);
#1593=ORIENTED_EDGE('',*,*,#1575,.T.);
#1594=DIRECTION('',(-0.707106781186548,0.,-0.707106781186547));
#1595=VECTOR('',#1594,1.);
#1596=CARTESIAN_POINT('',(466.426776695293,1.5,-543.608451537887));
#1597=LINE('',#1596,#1595);
#1598=CARTESIAN_POINT('',(-27.5,1.5,-1037.53522823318));
#1599=VERTEX_POINT('',#1598);
#1600=EDGE_CURVE('E725',#1599,#1568,#1597,.T.);
#1601=ORIENTED_EDGE('',*,*,#1600,.F.);
#1602=DIRECTION('',(0.,0.,-1.));
#1603=VECTOR('',#1602,1.);
#1604=CARTESIAN_POINT('',(-27.5,1.5,-55.0352282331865));
#1605=LINE('',#1604,#1603);
#1606=EDGE_CURVE('E717',#1590,#1599,#1605,.T.);
#1607=ORIENTED_EDGE('',*,*,#1606,.F.);
#1608=EDGE_LOOP('',(#1592,#1593,#1601,#1607));
#1609=FACE_BOUND('',#1608,.T.);
#1610=ADVANCED_FACE('F723',(#1609),#1584,.T.);
#1611=CARTESIAN_POINT('',(-27.5,-28.2727922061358,-55.0352282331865));
#1612=DIRECTION('',(-1.,0.,0.));
#1613=DIRECTION('',(0.,0.,1.));
#1614=AXIS2_PLACEMENT_3D('',#1611,#1612,#1613);
#1615=PLANE('',#1614);
#1616=DIRECTION('',(0.,0.,-1.));
#1617=VECTOR('',#1616,1.);
#1618=CARTESIAN_POINT('',(-27.5,7.5,-55.0352282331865));
#1619=LINE('',#1618,#1617);
#1620=CARTESIAN_POINT('',(-27.5,7.5,-72.5352282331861));
#1621=VERTEX_POINT('',#1620);
#1622=CARTESIAN_POINT('',(-27.5,7.5,-1037.53522823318));
#1623=VERTEX_POINT('',#1622);
#1624=EDGE_CURVE('E715',#1621,#1623,#1619,.T.);
#1625=ORIENTED_EDGE('',*,*,#1624,.F.);
#1626=DIRECTION('',(0.,-1.,0.));
#1627=VECTOR('',#1626,1.);
#1628=CARTESIAN_POINT('',(-27.5,-28.2727922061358,-72.5352282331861));
#1629=LINE('',#1628,#1627);
#1630=EDGE_CURVE('E885',#1621,#1590,#1629,.T.);
#1631=ORIENTED_EDGE('',*,*,#1630,.T.);
#1632=ORIENTED_EDGE('',*,*,#1606,.T.);
#1633=DIRECTION('',(0.,1.,0.));
#1634=VECTOR('',#1633,1.);
#1635=CARTESIAN_POINT('',(-27.5,-28.2727922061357,-1037.53522823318));
#1636=LINE('',#1635,#1634);
#1637=EDGE_CURVE('E737',#1599,#1623,#1636,.T.);
#1638=ORIENTED_EDGE('',*,*,#1637,.T.);
#1639=EDGE_LOOP('',(#1625,#1631,#1632,#1638));
#1640=FACE_BOUND('',#1639,.T.);
#1641=ADVANCED_FACE('F883',(#1640),#1615,.F.);
#1642=CARTESIAN_POINT('',(-22.1464466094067,7.5,-55.0352282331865));
#1643=DIRECTION('',(0.,1.,0.));
#1644=DIRECTION('',(0.,0.,1.));
#1645=AXIS2_PLACEMENT_3D('',#1642,#1643,#1644);
#1646=PLANE('',#1645);
#1647=DIRECTION('',(-0.707106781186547,0.,0.707106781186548));
#1648=VECTOR('',#1647,1.);
#1649=CARTESIAN_POINT('',(-33.5732233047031,7.5,-66.4620049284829));
#1650=LINE('',#1649,#1648);
#1651=CARTESIAN_POINT('',(-32.5,7.5,-67.5352282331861));
#1652=VERTEX_POINT('',#1651);
#1653=EDGE_CURVE('E887',#1621,#1652,#1650,.T.);
#1654=ORIENTED_EDGE('',*,*,#1653,.F.);
#1655=ORIENTED_EDGE('',*,*,#1624,.T.);
#1656=DIRECTION('',(0.707106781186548,0.,0.707106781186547));
#1657=VECTOR('',#1656,1.);
#1658=CARTESIAN_POINT('',(466.426776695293,7.5,-543.608451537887));
#1659=LINE('',#1658,#1657);
#1660=CARTESIAN_POINT('',(-32.5,7.5,-1042.53522823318));
#1661=VERTEX_POINT('',#1660);
#1662=EDGE_CURVE('E880',#1661,#1623,#1659,.T.);
#1663=ORIENTED_EDGE('',*,*,#1662,.F.);
#1664=DIRECTION('',(0.,0.,-1.));
#1665=VECTOR('',#1664,1.);
#1666=CARTESIAN_POINT('',(-32.5,7.5,-55.0352282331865));
#1667=LINE('',#1666,#1665);
#1668=EDGE_CURVE('E713',#1652,#1661,#1667,.T.);
#1669=ORIENTED_EDGE('',*,*,#1668,.F.);
#1670=EDGE_LOOP('',(#1654,#1655,#1663,#1669));
#1671=FACE_BOUND('',#1670,.T.);
#1672=ADVANCED_FACE('F1144',(#1671),#1646,.T.);
#1673=CARTESIAN_POINT('',(-32.5,-28.2727922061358,-55.0352282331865));
#1674=DIRECTION('',(-1.,0.,0.));
#1675=DIRECTION('',(0.,0.,1.));
#1676=AXIS2_PLACEMENT_3D('',#1673,#1674,#1675);
#1677=PLANE('',#1676);
#1678=DIRECTION('',(0.,0.,-1.));
#1679=VECTOR('',#1678,1.);
#1680=CARTESIAN_POINT('',(-32.5,10.6715728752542,-55.0352282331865));
#1681=LINE('',#1680,#1679);
#1682=CARTESIAN_POINT('',(-32.5,10.6715728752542,-67.5352282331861));
#1683=VERTEX_POINT('',#1682);
#1684=CARTESIAN_POINT('',(-32.5,10.6715728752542,-1042.53522823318));
#1685=VERTEX_POINT('',#1684);
#1686=EDGE_CURVE('E711',#1683,#1685,#1681,.T.);
#1687=ORIENTED_EDGE('',*,*,#1686,.F.);
#1688=DIRECTION('',(0.,-1.,0.));
#1689=VECTOR('',#1688,1.);
#1690=CARTESIAN_POINT('',(-32.5,-28.2727922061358,-67.5352282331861));
#1691=LINE('',#1690,#1689);
#1692=EDGE_CURVE('E890',#1683,#1652,#1691,.T.);
#1693=ORIENTED_EDGE('',*,*,#1692,.T.);
#1694=ORIENTED_EDGE('',*,*,#1668,.T.);
#1695=DIRECTION('',(0.,1.,0.));
#1696=VECTOR('',#1695,1.);
#1697=CARTESIAN_POINT('',(-32.5,-28.2727922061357,-1042.53522823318));
#1698=LINE('',#1697,#1696);
#1699=EDGE_CURVE('E877',#1661,#1685,#1698,.T.);
#1700=ORIENTED_EDGE('',*,*,#1699,.T.);
#1701=EDGE_LOOP('',(#1687,#1693,#1694,#1700));
#1702=FACE_BOUND('',#1701,.T.);
#1703=ADVANCED_FACE('F1140',(#1702),#1677,.F.);
#1704=CARTESIAN_POINT('',(-31.5,10.6715728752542,-55.0352282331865));
#1705=DIRECTION('',(0.,0.,-1.));
#1706=DIRECTION('',(-1.,0.,0.));
#1707=AXIS2_PLACEMENT_3D('',#1704,#1705,#1706);
#1708=CYLINDRICAL_SURFACE('',#1707,1.);
#1709=DIRECTION('',(0.,0.,-1.));
#1710=VECTOR('',#1709,1.);
#1711=CARTESIAN_POINT('',(-32.2071067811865,11.3786796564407,-55.0352282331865));
#1712=LINE('',#1711,#1710);
#1713=CARTESIAN_POINT('',(-32.2071067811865,11.3786796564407,-67.8281214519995));
#1714=VERTEX_POINT('',#1713);
#1715=CARTESIAN_POINT('',(-32.2071067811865,11.3786796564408,-1042.24233501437));
#1716=VERTEX_POINT('',#1715);
#1717=EDGE_CURVE('E709',#1714,#1716,#1712,.T.);
#1718=ORIENTED_EDGE('',*,*,#1717,.F.);
#1719=CARTESIAN_POINT('',(-31.5,10.6715728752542,-68.5352282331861));
#1720=DIRECTION('',(-0.707106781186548,0.,-0.707106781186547));
#1721=DIRECTION('',(0.707106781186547,0.,-0.707106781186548));
#1722=AXIS2_PLACEMENT_3D('',#1719,#1720,#1721);
#1723=ELLIPSE('',#1722,1.4142135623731,1.);
#1724=EDGE_CURVE('E1134',#1714,#1683,#1723,.F.);
#1725=ORIENTED_EDGE('',*,*,#1724,.T.);
#1726=ORIENTED_EDGE('',*,*,#1686,.T.);
#1727=CARTESIAN_POINT('',(-31.5,10.6715728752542,-1041.53522823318));
#1728=DIRECTION('',(-0.707106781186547,0.,0.707106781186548));
#1729=DIRECTION('',(-0.707106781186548,0.,-0.707106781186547));
#1730=AXIS2_PLACEMENT_3D('',#1727,#1728,#1729);
#1731=ELLIPSE('',#1730,1.4142135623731,1.);
#1732=EDGE_CURVE('E874',#1685,#1716,#1731,.F.);
#1733=ORIENTED_EDGE('',*,*,#1732,.T.);
#1734=EDGE_LOOP('',(#1718,#1725,#1726,#1733));
#1735=FACE_BOUND('',#1734,.T.);
#1736=ADVANCED_FACE('F1150',(#1735),#1708,.F.);
#1737=CARTESIAN_POINT('',(-47.0025126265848,-3.41672618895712,-55.0352282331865));
#1738=DIRECTION('',(0.707106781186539,-0.707106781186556,0.));
#1739=DIRECTION('',(0.707106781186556,0.707106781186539,0.));
#1740=AXIS2_PLACEMENT_3D('',#1737,#1738,#1739);
#1741=PLANE('',#1740);
#1742=DIRECTION('',(0.57735026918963,0.577350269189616,-0.577350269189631));
#1743=VECTOR('',#1742,1.);
#1744=CARTESIAN_POINT('',(-46.335008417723,-2.74922198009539,-53.7002198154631));
#1745=LINE('',#1744,#1743);
#1746=CARTESIAN_POINT('',(-27.501750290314,16.0840361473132,-72.5334779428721));
#1747=VERTEX_POINT('',#1746);
#1748=EDGE_CURVE('E1132',#1714,#1747,#1745,.T.);
#1749=ORIENTED_EDGE('',*,*,#1748,.F.);
#1750=ORIENTED_EDGE('',*,*,#1717,.T.);
#1751=DIRECTION('',(-0.577350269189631,-0.577350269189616,-0.57735026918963));
#1752=VECTOR('',#1751,1.);
#1753=CARTESIAN_POINT('',(286.998324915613,330.584111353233,-723.036903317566));
#1754=LINE('',#1753,#1752);
#1755=CARTESIAN_POINT('',(-27.501750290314,16.0840361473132,-1037.53697852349));
#1756=VERTEX_POINT('',#1755);
#1757=EDGE_CURVE('E871',#1756,#1716,#1754,.T.);
#1758=ORIENTED_EDGE('',*,*,#1757,.F.);
#1759=DIRECTION('',(0.,0.,-1.));
#1760=VECTOR('',#1759,1.);
#1761=CARTESIAN_POINT('',(-27.501750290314,16.0840361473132,-55.0352282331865));
#1762=LINE('',#1761,#1760);
#1763=EDGE_CURVE('E707',#1747,#1756,#1762,.T.);
#1764=ORIENTED_EDGE('',*,*,#1763,.F.);
#1765=EDGE_LOOP('',(#1749,#1750,#1758,#1764));
#1766=FACE_BOUND('',#1765,.T.);
#1767=ADVANCED_FACE('F1154',(#1766),#1741,.T.);
#1768=CARTESIAN_POINT('',(-26.7946435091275,15.3769293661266,-55.0352282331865));
#1769=DIRECTION('',(0.,0.,-1.));
#1770=DIRECTION('',(-1.,0.,0.));
#1771=AXIS2_PLACEMENT_3D('',#1768,#1769,#1770);
#1772=CYLINDRICAL_SURFACE('',#1771,1.);
#1773=DIRECTION('',(0.,0.,-1.));
#1774=VECTOR('',#1773,1.);
#1775=CARTESIAN_POINT('',(-26.2783100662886,16.233316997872,-55.0352282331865));
#1776=LINE('',#1775,#1774);
#1777=CARTESIAN_POINT('',(-26.2783100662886,16.233316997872,-73.7569181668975));
#1778=VERTEX_POINT('',#1777);
#1779=CARTESIAN_POINT('',(-26.2783100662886,16.233316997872,-1036.31353829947));
#1780=VERTEX_POINT('',#1779);
#1781=EDGE_CURVE('E705',#1778,#1780,#1776,.T.);
#1782=ORIENTED_EDGE('',*,*,#1781,.F.);
#1783=CARTESIAN_POINT('',(-26.7946435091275,15.3769293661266,-73.2405847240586));
#1784=DIRECTION('',(-0.707106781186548,0.,-0.707106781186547));
#1785=DIRECTION('',(0.707106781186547,0.,-0.707106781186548));
#1786=AXIS2_PLACEMENT_3D('',#1783,#1784,#1785);
#1787=ELLIPSE('',#1786,1.4142135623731,1.);
#1788=EDGE_CURVE('E1129',#1778,#1747,#1787,.F.);
#1789=ORIENTED_EDGE('',*,*,#1788,.T.);
#1790=ORIENTED_EDGE('',*,*,#1763,.T.);
#1791=CARTESIAN_POINT('',(-26.7946435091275,15.3769293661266,-1036.82987174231));
#1792=DIRECTION('',(-0.707106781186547,0.,0.707106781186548));
#1793=DIRECTION('',(-0.707106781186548,0.,-0.707106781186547));
#1794=AXIS2_PLACEMENT_3D('',#1791,#1792,#1793);
#1795=ELLIPSE('',#1794,1.4142135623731,1.);
#1796=EDGE_CURVE('E868',#1756,#1780,#1795,.F.);
#1797=ORIENTED_EDGE('',*,*,#1796,.T.);
#1798=EDGE_LOOP('',(#1782,#1789,#1790,#1797));
#1799=FACE_BOUND('',#1798,.T.);
#1800=ADVANCED_FACE('F1157',(#1799),#1772,.F.);
#1801=DIRECTION('',(0.,0.,-1.));
#1802=VECTOR('',#1801,1.);
#1803=CARTESIAN_POINT('',(-18.0813413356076,16.6671277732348,-55.0352282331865));
#1804=LINE('',#1803,#1802);
#1805=CARTESIAN_POINT('',(-18.0813413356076,16.6671277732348,-81.9538868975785));
#1806=VERTEX_POINT('',#1805);
#1807=CARTESIAN_POINT('',(-18.0813413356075,16.6671277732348,-1028.11656956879));
#1808=VERTEX_POINT('',#1807);
#1809=EDGE_CURVE('E703',#1806,#1808,#1804,.T.);
#1810=ORIENTED_EDGE('',*,*,#1809,.F.);
#1811=CARTESIAN_POINT('',(-22.5,22.5,-77.5352282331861));
#1812=DIRECTION('',(-0.707106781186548,0.,-0.707106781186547));
#1813=DIRECTION('',(0.707106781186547,0.,-0.707106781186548));
#1814=AXIS2_PLACEMENT_3D('',#1811,#1812,#1813);
#1815=ELLIPSE('',#1814,10.3486175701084,7.31757765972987);
#1816=EDGE_CURVE('E1126',#1806,#1778,#1815,.T.);
#1817=ORIENTED_EDGE('',*,*,#1816,.T.);
#1818=ORIENTED_EDGE('',*,*,#1781,.T.);
#1819=CARTESIAN_POINT('',(-22.5,22.5,-1032.53522823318));
#1820=DIRECTION('',(-0.707106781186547,0.,0.707106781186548));
#1821=DIRECTION('',(-0.707106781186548,0.,-0.707106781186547));
#1822=AXIS2_PLACEMENT_3D('',#1819,#1820,#1821);
#1823=ELLIPSE('',#1822,10.3486175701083,7.31757765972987);
#1824=EDGE_CURVE('E865',#1780,#1808,#1823,.T.);
#1825=ORIENTED_EDGE('',*,*,#1824,.T.);
#1826=EDGE_LOOP('',(#1810,#1817,#1818,#1825));
#1827=FACE_BOUND('',#1826,.T.);
#1828=ADVANCED_FACE('F1162',(#1827),#1045,.T.);
#1829=CARTESIAN_POINT('',(2.35606601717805,-3.77027957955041,-55.0352282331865));
#1830=DIRECTION('',(0.707106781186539,0.707106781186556,0.));
#1831=DIRECTION('',(-0.707106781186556,0.707106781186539,0.));
#1832=AXIS2_PLACEMENT_3D('',#1829,#1830,#1831);
#1833=PLANE('',#1832);
#1834=DIRECTION('',(0.,0.,-1.));
#1835=VECTOR('',#1834,1.);
#1836=CARTESIAN_POINT('',(-12.7928932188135,11.3786796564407,-55.0352282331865));
#1837=LINE('',#1836,#1835);
#1838=CARTESIAN_POINT('',(-12.7928932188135,11.3786796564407,-87.2423350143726));
#1839=VERTEX_POINT('',#1838);
#1840=CARTESIAN_POINT('',(-12.7928932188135,11.3786796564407,-1022.82812145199));
#1841=VERTEX_POINT('',#1840);
#1842=EDGE_CURVE('E701',#1839,#1841,#1837,.T.);
#1843=ORIENTED_EDGE('',*,*,#1842,.F.);
#1844=DIRECTION('',(-0.57735026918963,0.577350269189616,0.577350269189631));
#1845=VECTOR('',#1844,1.);
#1846=CARTESIAN_POINT('',(-13.4292893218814,12.0150757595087,-86.6059389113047));
#1847=LINE('',#1846,#1845);
#1848=EDGE_CURVE('E1123',#1839,#1806,#1847,.T.);
#1849=ORIENTED_EDGE('',*,*,#1848,.T.);
#1850=ORIENTED_EDGE('',*,*,#1809,.T.);
#1851=DIRECTION('',(0.577350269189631,-0.577350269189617,0.57735026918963));
#1852=VECTOR('',#1851,1.);
#1853=CARTESIAN_POINT('',(319.904044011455,-321.318257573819,-690.131184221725));
#1854=LINE('',#1853,#1852);
#1855=EDGE_CURVE('E862',#1808,#1841,#1854,.T.);
#1856=ORIENTED_EDGE('',*,*,#1855,.T.);
#1857=EDGE_LOOP('',(#1843,#1849,#1850,#1856));
#1858=FACE_BOUND('',#1857,.T.);
#1859=ADVANCED_FACE('F1166',(#1858),#1833,.F.);
#1860=CARTESIAN_POINT('',(-13.5,10.6715728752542,-55.0352282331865));
#1861=DIRECTION('',(0.,0.,-1.));
#1862=DIRECTION('',(-1.,0.,0.));
#1863=AXIS2_PLACEMENT_3D('',#1860,#1861,#1862);
#1864=CYLINDRICAL_SURFACE('',#1863,1.);
#1865=CARTESIAN_POINT('',(-13.5,10.6715728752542,-86.5352282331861));
#1866=DIRECTION('',(-0.707106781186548,0.,-0.707106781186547));
#1867=DIRECTION('',(0.707106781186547,0.,-0.707106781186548));
#1868=AXIS2_PLACEMENT_3D('',#1865,#1866,#1867);
#1869=ELLIPSE('',#1868,1.4142135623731,1.);
#1870=CARTESIAN_POINT('',(-12.5,10.6715728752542,-87.5352282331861));
#1871=VERTEX_POINT('',#1870);
#1872=EDGE_CURVE('E1121',#1839,#1871,#1869,.T.);
#1873=ORIENTED_EDGE('',*,*,#1872,.F.);
#1874=ORIENTED_EDGE('',*,*,#1842,.T.);
#1875=CARTESIAN_POINT('',(-13.5,10.6715728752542,-1023.53522823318));
#1876=DIRECTION('',(-0.707106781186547,0.,0.707106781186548));
#1877=DIRECTION('',(-0.707106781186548,0.,-0.707106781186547));
#1878=AXIS2_PLACEMENT_3D('',#1875,#1876,#1877);
#1879=ELLIPSE('',#1878,1.41421356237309,1.);
#1880=CARTESIAN_POINT('',(-12.5,10.6715728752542,-1022.53522823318));
#1881=VERTEX_POINT('',#1880);
#1882=EDGE_CURVE('E859',#1881,#1841,#1879,.T.);
#1883=ORIENTED_EDGE('',*,*,#1882,.F.);
#1884=DIRECTION('',(0.,0.,-1.));
#1885=VECTOR('',#1884,1.);
#1886=CARTESIAN_POINT('',(-12.5,10.6715728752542,-55.0352282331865));
#1887=LINE('',#1886,#1885);
#1888=EDGE_CURVE('E699',#1871,#1881,#1887,.T.);
#1889=ORIENTED_EDGE('',*,*,#1888,.F.);
#1890=EDGE_LOOP('',(#1873,#1874,#1883,#1889));
#1891=FACE_BOUND('',#1890,.T.);
#1892=ADVANCED_FACE('F1169',(#1891),#1864,.F.);
#1893=CARTESIAN_POINT('',(-12.5,-28.2727922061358,-55.0352282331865));
#1894=DIRECTION('',(-1.,0.,0.));
#1895=DIRECTION('',(0.,0.,1.));
#1896=AXIS2_PLACEMENT_3D('',#1893,#1894,#1895);
#1897=PLANE('',#1896);
#1898=DIRECTION('',(0.,-1.,0.));
#1899=VECTOR('',#1898,1.);
#1900=CARTESIAN_POINT('',(-12.5,-28.2727922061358,-87.5352282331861));
#1901=LINE('',#1900,#1899);
#1902=CARTESIAN_POINT('',(-12.5,7.5,-87.5352282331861));
#1903=VERTEX_POINT('',#1902);
#1904=EDGE_CURVE('E1119',#1871,#1903,#1901,.T.);
#1905=ORIENTED_EDGE('',*,*,#1904,.F.);
#1906=ORIENTED_EDGE('',*,*,#1888,.T.);
#1907=DIRECTION('',(0.,1.,0.));
#1908=VECTOR('',#1907,1.);
#1909=CARTESIAN_POINT('',(-12.5,-28.2727922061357,-1022.53522823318));
#1910=LINE('',#1909,#1908);
#1911=CARTESIAN_POINT('',(-12.5,7.5,-1022.53522823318));
#1912=VERTEX_POINT('',#1911);
#1913=EDGE_CURVE('E856',#1912,#1881,#1910,.T.);
#1914=ORIENTED_EDGE('',*,*,#1913,.F.);
#1915=DIRECTION('',(0.,0.,-1.));
#1916=VECTOR('',#1915,1.);
#1917=CARTESIAN_POINT('',(-12.5,7.5,-55.0352282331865));
#1918=LINE('',#1917,#1916);
#1919=EDGE_CURVE('E697',#1903,#1912,#1918,.T.);
#1920=ORIENTED_EDGE('',*,*,#1919,.F.);
#1921=EDGE_LOOP('',(#1905,#1906,#1914,#1920));
#1922=FACE_BOUND('',#1921,.T.);
#1923=ADVANCED_FACE('F1176',(#1922),#1897,.T.);
#1924=CARTESIAN_POINT('',(-22.1464466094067,7.5,-55.0352282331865));
#1925=DIRECTION('',(0.,-1.,0.));
#1926=DIRECTION('',(0.,0.,-1.));
#1927=AXIS2_PLACEMENT_3D('',#1924,#1925,#1926);
#1928=PLANE('',#1927);
#1929=DIRECTION('',(0.,0.,-1.));
#1930=VECTOR('',#1929,1.);
#1931=CARTESIAN_POINT('',(-17.5,7.5,-55.0352282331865));
#1932=LINE('',#1931,#1930);
#1933=CARTESIAN_POINT('',(-17.5,7.5,-82.5352282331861));
#1934=VERTEX_POINT('',#1933);
#1935=CARTESIAN_POINT('',(-17.5,7.5,-1027.53522823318));
#1936=VERTEX_POINT('',#1935);
#1937=EDGE_CURVE('E695',#1934,#1936,#1932,.T.);
#1938=ORIENTED_EDGE('',*,*,#1937,.F.);
#1939=DIRECTION('',(0.707106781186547,0.,-0.707106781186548));
#1940=VECTOR('',#1939,1.);
#1941=CARTESIAN_POINT('',(-33.5732233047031,7.5,-66.4620049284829));
#1942=LINE('',#1941,#1940);
#1943=EDGE_CURVE('E1116',#1934,#1903,#1942,.T.);
#1944=ORIENTED_EDGE('',*,*,#1943,.T.);
#1945=ORIENTED_EDGE('',*,*,#1919,.T.);
#1946=DIRECTION('',(-0.707106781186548,0.,-0.707106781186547));
#1947=VECTOR('',#1946,1.);
#1948=CARTESIAN_POINT('',(466.426776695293,7.5,-543.608451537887));
#1949=LINE('',#1948,#1947);
#1950=EDGE_CURVE('E853',#1912,#1936,#1949,.T.);
#1951=ORIENTED_EDGE('',*,*,#1950,.T.);
#1952=EDGE_LOOP('',(#1938,#1944,#1945,#1951));
#1953=FACE_BOUND('',#1952,.T.);
#1954=ADVANCED_FACE('F1180',(#1953),#1928,.F.);
#1955=CARTESIAN_POINT('',(-17.5,-28.2727922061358,-55.0352282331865));
#1956=DIRECTION('',(-1.,0.,0.));
#1957=DIRECTION('',(0.,0.,1.));
#1958=AXIS2_PLACEMENT_3D('',#1955,#1956,#1957);
#1959=PLANE('',#1958);
#1960=DIRECTION('',(0.,-1.,0.));
#1961=VECTOR('',#1960,1.);
#1962=CARTESIAN_POINT('',(-17.5,-28.2727922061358,-82.5352282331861));
#1963=LINE('',#1962,#1961);
#1964=CARTESIAN_POINT('',(-17.5,1.5,-82.5352282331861));
#1965=VERTEX_POINT('',#1964);
#1966=EDGE_CURVE('E1114',#1934,#1965,#1963,.T.);
#1967=ORIENTED_EDGE('',*,*,#1966,.F.);
#1968=ORIENTED_EDGE('',*,*,#1937,.T.);
#1969=DIRECTION('',(0.,1.,0.));
#1970=VECTOR('',#1969,1.);
#1971=CARTESIAN_POINT('',(-17.5,-28.2727922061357,-1027.53522823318));
#1972=LINE('',#1971,#1970);
#1973=CARTESIAN_POINT('',(-17.5,1.5,-1027.53522823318));
#1974=VERTEX_POINT('',#1973);
#1975=EDGE_CURVE('E850',#1974,#1936,#1972,.T.);
#1976=ORIENTED_EDGE('',*,*,#1975,.F.);
#1977=DIRECTION('',(0.,0.,-1.));
#1978=VECTOR('',#1977,1.);
#1979=CARTESIAN_POINT('',(-17.5,1.5,-55.0352282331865));
#1980=LINE('',#1979,#1978);
#1981=EDGE_CURVE('E693',#1965,#1974,#1980,.T.);
#1982=ORIENTED_EDGE('',*,*,#1981,.F.);
#1983=EDGE_LOOP('',(#1967,#1968,#1976,#1982));
#1984=FACE_BOUND('',#1983,.T.);
#1985=ADVANCED_FACE('F1183',(#1984),#1959,.T.);
#1986=CARTESIAN_POINT('',(-22.1464466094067,1.5,-55.0352282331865));
#1987=DIRECTION('',(0.,1.,0.));
#1988=DIRECTION('',(0.,0.,1.));
#1989=AXIS2_PLACEMENT_3D('',#1986,#1987,#1988);
#1990=PLANE('',#1989);
#1991=DIRECTION('',(0.,0.,-1.));
#1992=VECTOR('',#1991,1.);
#1993=CARTESIAN_POINT('',(-16.,1.5,-55.0352282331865));
#1994=LINE('',#1993,#1992);
#1995=CARTESIAN_POINT('',(-16.,1.5,-84.0352282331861));
#1996=VERTEX_POINT('',#1995);
#1997=CARTESIAN_POINT('',(-16.,1.5,-1026.03522823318));
#1998=VERTEX_POINT('',#1997);
#1999=EDGE_CURVE('E691',#1996,#1998,#1994,.T.);
#2000=ORIENTED_EDGE('',*,*,#1999,.F.);
#2001=DIRECTION('',(-0.707106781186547,0.,0.707106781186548));
#2002=VECTOR('',#2001,1.);
#2003=CARTESIAN_POINT('',(-33.5732233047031,1.5,-66.4620049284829));
#2004=LINE('',#2003,#2002);
#2005=EDGE_CURVE('E1111',#1996,#1965,#2004,.T.);
#2006=ORIENTED_EDGE('',*,*,#2005,.T.);
#2007=ORIENTED_EDGE('',*,*,#1981,.T.);
#2008=DIRECTION('',(0.707106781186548,0.,0.707106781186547));
#2009=VECTOR('',#2008,1.);
#2010=CARTESIAN_POINT('',(466.426776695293,1.5,-543.608451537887));
#2011=LINE('',#2010,#2009);
#2012=EDGE_CURVE('E847',#1974,#1998,#2011,.T.);
#2013=ORIENTED_EDGE('',*,*,#2012,.T.);
#2014=EDGE_LOOP('',(#2000,#2006,#2007,#2013));
#2015=FACE_BOUND('',#2014,.T.);
#2016=ADVANCED_FACE('F1190',(#2015),#1990,.F.);
#2017=CARTESIAN_POINT('',(-16.,-28.2727922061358,-55.0352282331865));
#2018=DIRECTION('',(1.,0.,0.));
#2019=DIRECTION('',(0.,0.,-1.));
#2020=AXIS2_PLACEMENT_3D('',#2017,#2018,#2019);
#2021=PLANE('',#2020);
#2022=DIRECTION('',(0.,0.,-1.));
#2023=VECTOR('',#2022,1.);
#2024=CARTESIAN_POINT('',(-16.,0.,-55.0352282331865));
#2025=LINE('',#2024,#2023);
#2026=CARTESIAN_POINT('',(-16.,0.,-84.0352282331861));
#2027=VERTEX_POINT('',#2026);
#2028=CARTESIAN_POINT('',(-15.9999999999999,0.,-1026.03522823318));
#2029=VERTEX_POINT('',#2028);
#2030=EDGE_CURVE('E689',#2027,#2029,#2025,.T.);
#2031=ORIENTED_EDGE('',*,*,#2030,.F.);
#2032=DIRECTION('',(0.,1.,0.));
#2033=VECTOR('',#2032,1.);
#2034=CARTESIAN_POINT('',(-16.,-28.2727922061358,-84.0352282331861));
#2035=LINE('',#2034,#2033);
#2036=EDGE_CURVE('E1108',#2027,#1996,#2035,.T.);
#2037=ORIENTED_EDGE('',*,*,#2036,.T.);
#2038=ORIENTED_EDGE('',*,*,#1999,.T.);
#2039=DIRECTION('',(0.,-1.,0.));
#2040=VECTOR('',#2039,1.);
#2041=CARTESIAN_POINT('',(-16.,-28.2727922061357,-1026.03522823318));
#2042=LINE('',#2041,#2040);
#2043=EDGE_CURVE('E844',#1998,#2029,#2042,.T.);
#2044=ORIENTED_EDGE('',*,*,#2043,.T.);
#2045=EDGE_LOOP('',(#2031,#2037,#2038,#2044));
#2046=FACE_BOUND('',#2045,.T.);
#2047=ADVANCED_FACE('F1194',(#2046),#2021,.F.);
#2048=CARTESIAN_POINT('',(-22.1464466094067,0.,-55.0352282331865));
#2049=DIRECTION('',(0.,-1.,0.));
#2050=DIRECTION('',(1.,0.,0.));
#2051=AXIS2_PLACEMENT_3D('',#2048,#2049,#2050);
#2052=PLANE('',#2051);
#2053=CARTESIAN_POINT('',(-3.,0.,-97.0352282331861));
#2054=VERTEX_POINT('',#2053);
#2055=EDGE_CURVE('E586',#2027,#2054,#1526,.T.);
#2056=ORIENTED_EDGE('',*,*,#2055,.F.);
#2057=ORIENTED_EDGE('',*,*,#2030,.T.);
#2058=CARTESIAN_POINT('',(-2.99999999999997,0.,-1013.03522823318));
#2059=VERTEX_POINT('',#2058);
#2060=EDGE_CURVE('E905',#2059,#2029,#1535,.T.);
#2061=ORIENTED_EDGE('',*,*,#2060,.F.);
#2062=DIRECTION('',(0.,0.,-1.));
#2063=VECTOR('',#2062,1.);
#2064=CARTESIAN_POINT('',(-3.00000000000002,0.,-55.0352282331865));
#2065=LINE('',#2064,#2063);
#2066=EDGE_CURVE('E687',#2054,#2059,#2065,.T.);
#2067=ORIENTED_EDGE('',*,*,#2066,.F.);
#2068=EDGE_LOOP('',(#2056,#2057,#2061,#2067));
#2069=FACE_BOUND('',#2068,.T.);
#2070=ADVANCED_FACE('F1197',(#2069),#2052,.T.);
#2071=CARTESIAN_POINT('',(-3.,3.,-55.0352282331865));
#2072=DIRECTION('',(0.,0.,-1.));
#2073=DIRECTION('',(-1.,0.,0.));
#2074=AXIS2_PLACEMENT_3D('',#2071,#2072,#2073);
#2075=CYLINDRICAL_SURFACE('',#2074,3.);
#2076=CARTESIAN_POINT('',(-3.,3.,-97.0352282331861));
#2077=DIRECTION('',(-0.707106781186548,0.,-0.707106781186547));
#2078=DIRECTION('',(0.707106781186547,0.,-0.707106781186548));
#2079=AXIS2_PLACEMENT_3D('',#2076,#2077,#2078);
#2080=ELLIPSE('',#2079,4.24264068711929,3.);
#2081=CARTESIAN_POINT('',(0.,3.00000000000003,-100.035228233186));
#2082=VERTEX_POINT('',#2081);
#2083=EDGE_CURVE('E1106',#2054,#2082,#2080,.F.);
#2084=ORIENTED_EDGE('',*,*,#2083,.F.);
#2085=ORIENTED_EDGE('',*,*,#2066,.T.);
#2086=CARTESIAN_POINT('',(-3.,3.,-1013.03522823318));
#2087=DIRECTION('',(-0.707106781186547,0.,0.707106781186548));
#2088=DIRECTION('',(-0.707106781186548,0.,-0.707106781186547));
#2089=AXIS2_PLACEMENT_3D('',#2086,#2087,#2088);
#2090=ELLIPSE('',#2089,4.24264068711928,3.);
#2091=CARTESIAN_POINT('',(0.,3.00000000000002,-1010.03522823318));
#2092=VERTEX_POINT('',#2091);
#2093=EDGE_CURVE('E838',#2092,#2059,#2090,.F.);
#2094=ORIENTED_EDGE('',*,*,#2093,.F.);
#2095=DIRECTION('',(0.,0.,-1.));
#2096=VECTOR('',#2095,1.);
#2097=CARTESIAN_POINT('',(0.,3.00000000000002,-55.0352282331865));
#2098=LINE('',#2097,#2096);
#2099=EDGE_CURVE('E685',#2082,#2092,#2098,.T.);
#2100=ORIENTED_EDGE('',*,*,#2099,.F.);
#2101=EDGE_LOOP('',(#2084,#2085,#2094,#2100));
#2102=FACE_BOUND('',#2101,.T.);
#2103=ADVANCED_FACE('F1204',(#2102),#2075,.T.);
#2104=CARTESIAN_POINT('',(0.,-28.2727922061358,-55.0352282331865));
#2105=DIRECTION('',(-1.,0.,0.));
#2106=DIRECTION('',(0.,-1.,0.));
#2107=AXIS2_PLACEMENT_3D('',#2104,#2105,#2106);
#2108=PLANE('',#2107);
#2109=DIRECTION('',(0.,0.,-1.));
#2110=VECTOR('',#2109,1.);
#2111=CARTESIAN_POINT('',(0.,16.,-55.0352282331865));
#2112=LINE('',#2111,#2110);
#2113=CARTESIAN_POINT('',(0.,16.,-100.035228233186));
#2114=VERTEX_POINT('',#2113);
#2115=CARTESIAN_POINT('',(0.,16.,-1010.03522823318));
#2116=VERTEX_POINT('',#2115);
#2117=EDGE_CURVE('E683',#2114,#2116,#2112,.T.);
#2118=ORIENTED_EDGE('',*,*,#2117,.F.);
#2119=EDGE_CURVE('E585',#2114,#2082,#1344,.T.);
#2120=ORIENTED_EDGE('',*,*,#2119,.T.);
#2121=ORIENTED_EDGE('',*,*,#2099,.T.);
#2122=EDGE_CURVE('E906',#2116,#2092,#1351,.T.);
#2123=ORIENTED_EDGE('',*,*,#2122,.F.);
#2124=EDGE_LOOP('',(#2118,#2120,#2121,#2123));
#2125=FACE_BOUND('',#2124,.T.);
#2126=ADVANCED_FACE('F1209',(#2125),#2108,.F.);
#2127=CARTESIAN_POINT('',(-22.1464466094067,16.,-55.0352282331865));
#2128=DIRECTION('',(0.,1.,0.));
#2129=DIRECTION('',(0.,0.,1.));
#2130=AXIS2_PLACEMENT_3D('',#2127,#2128,#2129);
#2131=PLANE('',#2130);
#2132=DIRECTION('',(-0.707106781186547,0.,0.707106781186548));
#2133=VECTOR('',#2132,1.);
#2134=CARTESIAN_POINT('',(-33.5732233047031,16.,-66.4620049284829));
#2135=LINE('',#2134,#2133);
#2136=CARTESIAN_POINT('',(-1.5,16.,-98.5352282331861));
#2137=VERTEX_POINT('',#2136);
#2138=EDGE_CURVE('E1295',#2114,#2137,#2135,.T.);
#2139=ORIENTED_EDGE('',*,*,#2138,.F.);
#2140=ORIENTED_EDGE('',*,*,#2117,.T.);
#2141=DIRECTION('',(0.707106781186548,0.,0.707106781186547));
#2142=VECTOR('',#2141,1.);
#2143=CARTESIAN_POINT('',(466.426776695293,16.,-543.608451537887));
#2144=LINE('',#2143,#2142);
#2145=CARTESIAN_POINT('',(-1.5,16.,-1011.53522823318));
#2146=VERTEX_POINT('',#2145);
#2147=EDGE_CURVE('E1007',#2146,#2116,#2144,.T.);
#2148=ORIENTED_EDGE('',*,*,#2147,.F.);
#2149=DIRECTION('',(0.,0.,-1.));
#2150=VECTOR('',#2149,1.);
#2151=CARTESIAN_POINT('',(-1.5,16.,-55.0352282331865));
#2152=LINE('',#2151,#2150);
#2153=EDGE_CURVE('E681',#2137,#2146,#2152,.T.);
#2154=ORIENTED_EDGE('',*,*,#2153,.F.);
#2155=EDGE_LOOP('',(#2139,#2140,#2148,#2154));
#2156=FACE_BOUND('',#2155,.T.);
#2157=ADVANCED_FACE('F1692',(#2156),#2131,.T.);
#2158=CARTESIAN_POINT('',(-1.5,-28.2727922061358,-55.0352282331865));
#2159=DIRECTION('',(1.,0.,0.));
#2160=DIRECTION('',(0.,0.,-1.));
#2161=AXIS2_PLACEMENT_3D('',#2158,#2159,#2160);
#2162=PLANE('',#2161);
#2163=DIRECTION('',(0.,1.,0.));
#2164=VECTOR('',#2163,1.);
#2165=CARTESIAN_POINT('',(-1.5,-28.2727922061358,-98.5352282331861));
#2166=LINE('',#2165,#2164);
#2167=CARTESIAN_POINT('',(-1.5,17.5,-98.5352282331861));
#2168=VERTEX_POINT('',#2167);
#2169=EDGE_CURVE('E1293',#2137,#2168,#2166,.T.);
#2170=ORIENTED_EDGE('',*,*,#2169,.F.);
#2171=ORIENTED_EDGE('',*,*,#2153,.T.);
#2172=DIRECTION('',(0.,-1.,0.));
#2173=VECTOR('',#2172,1.);
#2174=CARTESIAN_POINT('',(-1.5,-28.2727922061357,-1011.53522823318));
#2175=LINE('',#2174,#2173);
#2176=CARTESIAN_POINT('',(-1.5,17.5,-1011.53522823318));
#2177=VERTEX_POINT('',#2176);
#2178=EDGE_CURVE('E1004',#2177,#2146,#2175,.T.);
#2179=ORIENTED_EDGE('',*,*,#2178,.F.);
#2180=DIRECTION('',(0.,0.,-1.));
#2181=VECTOR('',#2180,1.);
#2182=CARTESIAN_POINT('',(-1.5,17.5,-55.0352282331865));
#2183=LINE('',#2182,#2181);
#2184=EDGE_CURVE('E674',#2168,#2177,#2183,.T.);
#2185=ORIENTED_EDGE('',*,*,#2184,.F.);
#2186=EDGE_LOOP('',(#2170,#2171,#2179,#2185));
#2187=FACE_BOUND('',#2186,.T.);
#2188=ADVANCED_FACE('F1699',(#2187),#2162,.T.);
#2189=CARTESIAN_POINT('',(-22.1464466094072,17.4999999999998,-55.0352282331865));
#2190=DIRECTION('',(0.,-1.,0.));
#2191=DIRECTION('',(1.,0.,0.));
#2192=AXIS2_PLACEMENT_3D('',#2189,#2190,#2191);
#2193=PLANE('',#2192);
#2194=DIRECTION('',(0.,0.,-1.));
#2195=VECTOR('',#2194,1.);
#2196=CARTESIAN_POINT('',(-7.50000000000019,17.4999999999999,-55.0352282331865));
#2197=LINE('',#2196,#2195);
#2198=CARTESIAN_POINT('',(-7.50000000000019,17.4999999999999,-92.5352282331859));
#2199=VERTEX_POINT('',#2198);
#2200=CARTESIAN_POINT('',(-7.50000000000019,17.4999999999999,-1017.53522823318));
#2201=VERTEX_POINT('',#2200);
#2202=EDGE_CURVE('E667',#2199,#2201,#2197,.T.);
#2203=ORIENTED_EDGE('',*,*,#2202,.F.);
#2204=DIRECTION('',(0.707106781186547,0.,-0.707106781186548));
#2205=VECTOR('',#2204,1.);
#2206=CARTESIAN_POINT('',(-33.5732233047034,17.4999999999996,-66.4620049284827));
#2207=LINE('',#2206,#2205);
#2208=EDGE_CURVE('E1290',#2199,#2168,#2207,.T.);
#2209=ORIENTED_EDGE('',*,*,#2208,.T.);
#2210=ORIENTED_EDGE('',*,*,#2184,.T.);
#2211=DIRECTION('',(-0.707106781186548,0.,-0.707106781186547));
#2212=VECTOR('',#2211,1.);
#2213=CARTESIAN_POINT('',(466.426776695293,17.5000000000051,-543.608451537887));
#2214=LINE('',#2213,#2212);
#2215=EDGE_CURVE('E1001',#2177,#2201,#2214,.T.);
#2216=ORIENTED_EDGE('',*,*,#2215,.T.);
#2217=EDGE_LOOP('',(#2203,#2209,#2210,#2216));
#2218=FACE_BOUND('',#2217,.T.);
#2219=ADVANCED_FACE('F1707',(#2218),#2193,.F.);
#2220=CARTESIAN_POINT('',(-6.00000000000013,-28.2727922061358,-55.0352282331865));
#2221=DIRECTION('',(-1.,0.,0.));
#2222=DIRECTION('',(0.,0.,1.));
#2223=AXIS2_PLACEMENT_3D('',#2220,#2221,#2222);
#2224=PLANE('',#2223);
#2225=DIRECTION('',(0.,0.,-1.));
#2226=VECTOR('',#2225,1.);
#2227=CARTESIAN_POINT('',(-6.00000000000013,14.,-55.0352282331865));
#2228=LINE('',#2227,#2226);
#2229=CARTESIAN_POINT('',(-6.00000000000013,14.,-94.035228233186));
#2230=VERTEX_POINT('',#2229);
#2231=CARTESIAN_POINT('',(-6.00000000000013,14.,-1016.03522823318));
#2232=VERTEX_POINT('',#2231);
#2233=EDGE_CURVE('E35',#2230,#2232,#2228,.T.);
#2234=ORIENTED_EDGE('',*,*,#2233,.F.);
#2235=DIRECTION('',(0.,-1.,0.));
#2236=VECTOR('',#2235,1.);
#2237=CARTESIAN_POINT('',(-6.00000000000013,-28.2727922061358,-94.035228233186));
#2238=LINE('',#2237,#2236);
#2239=CARTESIAN_POINT('',(-6.00000000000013,10.9999999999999,-94.035228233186));
#2240=VERTEX_POINT('',#2239);
#2241=EDGE_CURVE('E1285',#2230,#2240,#2238,.T.);
#2242=ORIENTED_EDGE('',*,*,#2241,.T.);
#2243=DIRECTION('',(0.,0.,-1.));
#2244=VECTOR('',#2243,1.);
#2245=CARTESIAN_POINT('',(-6.00000000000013,10.9999999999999,-55.0352282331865));
#2246=LINE('',#2245,#2244);
#2247=CARTESIAN_POINT('',(-6.00000000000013,10.9999999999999,-1016.03522823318));
#2248=VERTEX_POINT('',#2247);
#2249=EDGE_CURVE('E632',#2240,#2248,#2246,.T.);
#2250=ORIENTED_EDGE('',*,*,#2249,.T.);
#2251=DIRECTION('',(0.,1.,0.));
#2252=VECTOR('',#2251,1.);
#2253=CARTESIAN_POINT('',(-6.00000000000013,-28.2727922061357,-1016.03522823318));
#2254=LINE('',#2253,#2252);
#2255=EDGE_CURVE('E995',#2248,#2232,#2254,.T.);
#2256=ORIENTED_EDGE('',*,*,#2255,.T.);
#2257=EDGE_LOOP('',(#2234,#2242,#2250,#2256));
#2258=FACE_BOUND('',#2257,.T.);
#2259=ADVANCED_FACE('F33',(#2258),#2224,.F.);
#2260=CARTESIAN_POINT('',(-4.00000000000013,14.,-55.0352282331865));
#2261=DIRECTION('',(0.,0.,-1.));
#2262=DIRECTION('',(-1.,0.,0.));
#2263=AXIS2_PLACEMENT_3D('',#2260,#2261,#2262);
#2264=CYLINDRICAL_SURFACE('',#2263,2.);
#2265=DIRECTION('',(0.,0.,-1.));
#2266=VECTOR('',#2265,1.);
#2267=CARTESIAN_POINT('',(-4.00000000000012,16.,-55.0352282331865));
#2268=LINE('',#2267,#2266);
#2269=CARTESIAN_POINT('',(-4.00000000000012,16.,-96.035228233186));
#2270=VERTEX_POINT('',#2269);
#2271=CARTESIAN_POINT('',(-4.00000000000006,16.,-1014.03522823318));
#2272=VERTEX_POINT('',#2271);
#2273=EDGE_CURVE('E655',#2270,#2272,#2268,.T.);
#2274=ORIENTED_EDGE('',*,*,#2273,.F.);
#2275=CARTESIAN_POINT('',(-4.00000000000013,14.,-96.035228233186));
#2276=DIRECTION('',(-0.707106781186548,0.,-0.707106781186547));
#2277=DIRECTION('',(0.707106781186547,0.,-0.707106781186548));
#2278=AXIS2_PLACEMENT_3D('',#2275,#2276,#2277);
#2279=ELLIPSE('',#2278,2.82842712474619,2.);
#2280=EDGE_CURVE('E1283',#2270,#2230,#2279,.F.);
#2281=ORIENTED_EDGE('',*,*,#2280,.T.);
#2282=ORIENTED_EDGE('',*,*,#2233,.T.);
#2283=CARTESIAN_POINT('',(-4.00000000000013,14.,-1014.03522823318));
#2284=DIRECTION('',(-0.707106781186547,0.,0.707106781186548));
#2285=DIRECTION('',(-0.707106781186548,0.,-0.707106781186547));
#2286=AXIS2_PLACEMENT_3D('',#2283,#2284,#2285);
#2287=ELLIPSE('',#2286,2.82842712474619,2.);
#2288=EDGE_CURVE('E993',#2232,#2272,#2287,.F.);
#2289=ORIENTED_EDGE('',*,*,#2288,.T.);
#2290=EDGE_LOOP('',(#2274,#2281,#2282,#2289));
#2291=FACE_BOUND('',#2290,.T.);
#2292=ADVANCED_FACE('F1722',(#2291),#2264,.F.);
#2293=CARTESIAN_POINT('',(-22.1464466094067,16.,-55.0352282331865));
#2294=DIRECTION('',(0.,-1.,0.));
#2295=DIRECTION('',(0.,0.,-1.));
#2296=AXIS2_PLACEMENT_3D('',#2293,#2294,#2295);
#2297=PLANE('',#2296);
#2298=DIRECTION('',(0.707106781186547,0.,-0.707106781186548));
#2299=VECTOR('',#2298,1.);
#2300=CARTESIAN_POINT('',(-33.5732233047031,16.,-66.4620049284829));
#2301=LINE('',#2300,#2299);
#2302=CARTESIAN_POINT('',(-3.50000000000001,16.,-96.5352282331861));
#2303=VERTEX_POINT('',#2302);
#2304=EDGE_CURVE('E1281',#2270,#2303,#2301,.T.);
#2305=ORIENTED_EDGE('',*,*,#2304,.F.);
#2306=ORIENTED_EDGE('',*,*,#2273,.T.);
#2307=DIRECTION('',(-0.707106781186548,0.,-0.707106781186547));
#2308=VECTOR('',#2307,1.);
#2309=CARTESIAN_POINT('',(466.426776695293,16.,-543.608451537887));
#2310=LINE('',#2309,#2308);
#2311=CARTESIAN_POINT('',(-3.50000000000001,16.,-1013.53522823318));
#2312=VERTEX_POINT('',#2311);
#2313=EDGE_CURVE('E991',#2312,#2272,#2310,.T.);
#2314=ORIENTED_EDGE('',*,*,#2313,.F.);
#2315=DIRECTION('',(0.,0.,-1.));
#2316=VECTOR('',#2315,1.);
#2317=CARTESIAN_POINT('',(-3.50000000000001,16.,-55.0352282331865));
#2318=LINE('',#2317,#2316);
#2319=EDGE_CURVE('E654',#2303,#2312,#2318,.T.);
#2320=ORIENTED_EDGE('',*,*,#2319,.F.);
#2321=EDGE_LOOP('',(#2305,#2306,#2314,#2320));
#2322=FACE_BOUND('',#2321,.T.);
#2323=ADVANCED_FACE('F1729',(#2322),#2297,.T.);
#2324=CARTESIAN_POINT('',(-3.5,14.,-55.0352282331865));
#2325=DIRECTION('',(0.,0.,-1.));
#2326=DIRECTION('',(-1.,0.,0.));
#2327=AXIS2_PLACEMENT_3D('',#2324,#2325,#2326);
#2328=CYLINDRICAL_SURFACE('',#2327,2.);
#2329=CARTESIAN_POINT('',(-3.5,14.,-96.5352282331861));
#2330=DIRECTION('',(-0.707106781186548,0.,-0.707106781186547));
#2331=DIRECTION('',(0.707106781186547,0.,-0.707106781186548));
#2332=AXIS2_PLACEMENT_3D('',#2329,#2330,#2331);
#2333=ELLIPSE('',#2332,2.82842712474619,2.);
#2334=CARTESIAN_POINT('',(-1.5,14.,-98.5352282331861));
#2335=VERTEX_POINT('',#2334);
#2336=EDGE_CURVE('E1279',#2303,#2335,#2333,.T.);
#2337=ORIENTED_EDGE('',*,*,#2336,.F.);
#2338=ORIENTED_EDGE('',*,*,#2319,.T.);
#2339=CARTESIAN_POINT('',(-3.5,14.,-1013.53522823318));
#2340=DIRECTION('',(-0.707106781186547,0.,0.707106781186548));
#2341=DIRECTION('',(-0.707106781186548,0.,-0.707106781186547));
#2342=AXIS2_PLACEMENT_3D('',#2339,#2340,#2341);
#2343=ELLIPSE('',#2342,2.82842712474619,2.);
#2344=CARTESIAN_POINT('',(-1.5,14.,-1011.53522823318));
#2345=VERTEX_POINT('',#2344);
#2346=EDGE_CURVE('E988',#2345,#2312,#2343,.T.);
#2347=ORIENTED_EDGE('',*,*,#2346,.F.);
#2348=DIRECTION('',(0.,0.,-1.));
#2349=VECTOR('',#2348,1.);
#2350=CARTESIAN_POINT('',(-1.5,14.,-55.0352282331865));
#2351=LINE('',#2350,#2349);
#2352=EDGE_CURVE('E652',#2335,#2345,#2351,.T.);
#2353=ORIENTED_EDGE('',*,*,#2352,.F.);
#2354=EDGE_LOOP('',(#2337,#2338,#2347,#2353));
#2355=FACE_BOUND('',#2354,.T.);
#2356=ADVANCED_FACE('F1735',(#2355),#2328,.F.);
#2357=CARTESIAN_POINT('',(-1.5,-28.2727922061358,-55.0352282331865));
#2358=DIRECTION('',(-1.,0.,0.));
#2359=DIRECTION('',(0.,-1.,0.));
#2360=AXIS2_PLACEMENT_3D('',#2357,#2358,#2359);
#2361=PLANE('',#2360);
#2362=DIRECTION('',(0.,-1.,0.));
#2363=VECTOR('',#2362,1.);
#2364=CARTESIAN_POINT('',(-1.5,-28.2727922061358,-98.5352282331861));
#2365=LINE('',#2364,#2363);
#2366=CARTESIAN_POINT('',(-1.5,3.00000000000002,-98.5352282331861));
#2367=VERTEX_POINT('',#2366);
#2368=EDGE_CURVE('E1277',#2335,#2367,#2365,.T.);
#2369=ORIENTED_EDGE('',*,*,#2368,.F.);
#2370=ORIENTED_EDGE('',*,*,#2352,.T.);
#2371=DIRECTION('',(0.,1.,0.));
#2372=VECTOR('',#2371,1.);
#2373=CARTESIAN_POINT('',(-1.5,-28.2727922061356,-1011.53522823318));
#2374=LINE('',#2373,#2372);
#2375=CARTESIAN_POINT('',(-1.5,3.00000000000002,-1011.53522823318));
#2376=VERTEX_POINT('',#2375);
#2377=EDGE_CURVE('E985',#2376,#2345,#2374,.T.);
#2378=ORIENTED_EDGE('',*,*,#2377,.F.);
#2379=DIRECTION('',(0.,0.,-1.));
#2380=VECTOR('',#2379,1.);
#2381=CARTESIAN_POINT('',(-1.5,3.00000000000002,-55.0352282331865));
#2382=LINE('',#2381,#2380);
#2383=EDGE_CURVE('E650',#2367,#2376,#2382,.T.);
#2384=ORIENTED_EDGE('',*,*,#2383,.F.);
#2385=EDGE_LOOP('',(#2369,#2370,#2378,#2384));
#2386=FACE_BOUND('',#2385,.T.);
#2387=ADVANCED_FACE('F1742',(#2386),#2361,.T.);
#2388=CARTESIAN_POINT('',(-3.,3.,-55.0352282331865));
#2389=DIRECTION('',(0.,0.,-1.));
#2390=DIRECTION('',(-1.,0.,0.));
#2391=AXIS2_PLACEMENT_3D('',#2388,#2389,#2390);
#2392=CYLINDRICAL_SURFACE('',#2391,1.5);
#2393=DIRECTION('',(0.,0.,-1.));
#2394=VECTOR('',#2393,1.);
#2395=CARTESIAN_POINT('',(-3.00000000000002,1.5,-55.0352282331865));
#2396=LINE('',#2395,#2394);
#2397=CARTESIAN_POINT('',(-3.00000000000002,1.5,-97.0352282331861));
#2398=VERTEX_POINT('',#2397);
#2399=CARTESIAN_POINT('',(-2.99999999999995,1.5,-1013.03522823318));
#2400=VERTEX_POINT('',#2399);
#2401=EDGE_CURVE('E648',#2398,#2400,#2396,.T.);
#2402=ORIENTED_EDGE('',*,*,#2401,.F.);
#2403=CARTESIAN_POINT('',(-3.,3.,-97.0352282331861));
#2404=DIRECTION('',(-0.707106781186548,0.,-0.707106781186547));
#2405=DIRECTION('',(0.707106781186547,0.,-0.707106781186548));
#2406=AXIS2_PLACEMENT_3D('',#2403,#2404,#2405);
#2407=ELLIPSE('',#2406,2.12132034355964,1.5);
#2408=EDGE_CURVE('E1274',#2398,#2367,#2407,.F.);
#2409=ORIENTED_EDGE('',*,*,#2408,.T.);
#2410=ORIENTED_EDGE('',*,*,#2383,.T.);
#2411=CARTESIAN_POINT('',(-3.,3.,-1013.03522823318));
#2412=DIRECTION('',(-0.707106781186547,0.,0.707106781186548));
#2413=DIRECTION('',(-0.707106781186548,0.,-0.707106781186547));
#2414=AXIS2_PLACEMENT_3D('',#2411,#2412,#2413);
#2415=ELLIPSE('',#2414,2.12132034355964,1.5);
#2416=EDGE_CURVE('E982',#2376,#2400,#2415,.F.);
#2417=ORIENTED_EDGE('',*,*,#2416,.T.);
#2418=EDGE_LOOP('',(#2402,#2409,#2410,#2417));
#2419=FACE_BOUND('',#2418,.T.);
#2420=ADVANCED_FACE('F1750',(#2419),#2392,.F.);
#2421=CARTESIAN_POINT('',(-22.1464466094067,1.5,-55.0352282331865));
#2422=DIRECTION('',(0.,-1.,0.));
#2423=DIRECTION('',(0.,0.,-1.));
#2424=AXIS2_PLACEMENT_3D('',#2421,#2422,#2423);
#2425=PLANE('',#2424);
#2426=DIRECTION('',(0.,0.,-1.));
#2427=VECTOR('',#2426,1.);
#2428=CARTESIAN_POINT('',(-14.,1.5,-55.0352282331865));
#2429=LINE('',#2428,#2427);
#2430=CARTESIAN_POINT('',(-14.,1.5,-86.0352282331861));
#2431=VERTEX_POINT('',#2430);
#2432=CARTESIAN_POINT('',(-14.,1.5,-1024.03522823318));
#2433=VERTEX_POINT('',#2432);
#2434=EDGE_CURVE('E646',#2431,#2433,#2429,.T.);
#2435=ORIENTED_EDGE('',*,*,#2434,.F.);
#2436=DIRECTION('',(0.707106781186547,0.,-0.707106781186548));
#2437=VECTOR('',#2436,1.);
#2438=CARTESIAN_POINT('',(-33.5732233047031,1.5,-66.4620049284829));
#2439=LINE('',#2438,#2437);
#2440=EDGE_CURVE('E1271',#2431,#2398,#2439,.T.);
#2441=ORIENTED_EDGE('',*,*,#2440,.T.);
#2442=ORIENTED_EDGE('',*,*,#2401,.T.);
#2443=DIRECTION('',(-0.707106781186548,0.,-0.707106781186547));
#2444=VECTOR('',#2443,1.);
#2445=CARTESIAN_POINT('',(466.426776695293,1.5,-543.608451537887));
#2446=LINE('',#2445,#2444);
#2447=EDGE_CURVE('E979',#2400,#2433,#2446,.T.);
#2448=ORIENTED_EDGE('',*,*,#2447,.T.);
#2449=EDGE_LOOP('',(#2435,#2441,#2442,#2448));
#2450=FACE_BOUND('',#2449,.T.);
#2451=ADVANCED_FACE('F1758',(#2450),#2425,.F.);
#2452=CARTESIAN_POINT('',(-14.,3.5,-55.0352282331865));
#2453=DIRECTION('',(0.,0.,-1.));
#2454=DIRECTION('',(-1.,0.,0.));
#2455=AXIS2_PLACEMENT_3D('',#2452,#2453,#2454);
#2456=CYLINDRICAL_SURFACE('',#2455,2.);
#2457=DIRECTION('',(0.,0.,-1.));
#2458=VECTOR('',#2457,1.);
#2459=CARTESIAN_POINT('',(-16.,3.50000000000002,-55.0352282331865));
#2460=LINE('',#2459,#2458);
#2461=CARTESIAN_POINT('',(-16.,3.50000000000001,-84.0352282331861));
#2462=VERTEX_POINT('',#2461);
#2463=CARTESIAN_POINT('',(-16.,3.50000000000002,-1026.03522823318));
#2464=VERTEX_POINT('',#2463);
#2465=EDGE_CURVE('E644',#2462,#2464,#2460,.T.);
#2466=ORIENTED_EDGE('',*,*,#2465,.F.);
#2467=CARTESIAN_POINT('',(-14.,3.5,-86.0352282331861));
#2468=DIRECTION('',(-0.707106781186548,0.,-0.707106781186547));
#2469=DIRECTION('',(0.707106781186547,0.,-0.707106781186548));
#2470=AXIS2_PLACEMENT_3D('',#2467,#2468,#2469);
#2471=ELLIPSE('',#2470,2.82842712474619,2.);
#2472=EDGE_CURVE('E1268',#2462,#2431,#2471,.F.);
#2473=ORIENTED_EDGE('',*,*,#2472,.T.);
#2474=ORIENTED_EDGE('',*,*,#2434,.T.);
#2475=CARTESIAN_POINT('',(-14.,3.5,-1024.03522823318));
#2476=DIRECTION('',(-0.707106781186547,0.,0.707106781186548));
#2477=DIRECTION('',(-0.707106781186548,0.,-0.707106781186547));
#2478=AXIS2_PLACEMENT_3D('',#2475,#2476,#2477);
#2479=ELLIPSE('',#2478,2.82842712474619,2.);
#2480=EDGE_CURVE('E976',#2433,#2464,#2479,.F.);
#2481=ORIENTED_EDGE('',*,*,#2480,.T.);
#2482=EDGE_LOOP('',(#2466,#2473,#2474,#2481));
#2483=FACE_BOUND('',#2482,.T.);
#2484=ADVANCED_FACE('F1766',(#2483),#2456,.F.);
#2485=CARTESIAN_POINT('',(-16.,-28.2727922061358,-55.0352282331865));
#2486=DIRECTION('',(-1.,0.,0.));
#2487=DIRECTION('',(0.,0.,1.));
#2488=AXIS2_PLACEMENT_3D('',#2485,#2486,#2487);
#2489=PLANE('',#2488);
#2490=DIRECTION('',(0.,0.,-1.));
#2491=VECTOR('',#2490,1.);
#2492=CARTESIAN_POINT('',(-16.,3.99999999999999,-55.0352282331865));
#2493=LINE('',#2492,#2491);
#2494=CARTESIAN_POINT('',(-16.,3.99999999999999,-84.0352282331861));
#2495=VERTEX_POINT('',#2494);
#2496=CARTESIAN_POINT('',(-16.,3.99999999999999,-1026.03522823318));
#2497=VERTEX_POINT('',#2496);
#2498=EDGE_CURVE('E642',#2495,#2497,#2493,.T.);
#2499=ORIENTED_EDGE('',*,*,#2498,.F.);
#2500=DIRECTION('',(0.,-1.,0.));
#2501=VECTOR('',#2500,1.);
#2502=CARTESIAN_POINT('',(-16.,-28.2727922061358,-84.0352282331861));
#2503=LINE('',#2502,#2501);
#2504=EDGE_CURVE('E1265',#2495,#2462,#2503,.T.);
#2505=ORIENTED_EDGE('',*,*,#2504,.T.);
#2506=ORIENTED_EDGE('',*,*,#2465,.T.);
#2507=DIRECTION('',(0.,1.,0.));
#2508=VECTOR('',#2507,1.);
#2509=CARTESIAN_POINT('',(-16.,-28.2727922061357,-1026.03522823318));
#2510=LINE('',#2509,#2508);
#2511=EDGE_CURVE('E973',#2464,#2497,#2510,.T.);
#2512=ORIENTED_EDGE('',*,*,#2511,.T.);
#2513=EDGE_LOOP('',(#2499,#2505,#2506,#2512));
#2514=FACE_BOUND('',#2513,.T.);
#2515=ADVANCED_FACE('F1774',(#2514),#2489,.F.);
#2516=CARTESIAN_POINT('',(-14.,4.,-55.0352282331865));
#2517=DIRECTION('',(0.,0.,-1.));
#2518=DIRECTION('',(-1.,0.,0.));
#2519=AXIS2_PLACEMENT_3D('',#2516,#2517,#2518);
#2520=CYLINDRICAL_SURFACE('',#2519,2.);
#2521=DIRECTION('',(0.,0.,-1.));
#2522=VECTOR('',#2521,1.);
#2523=CARTESIAN_POINT('',(-14.,6.,-55.0352282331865));
#2524=LINE('',#2523,#2522);
#2525=CARTESIAN_POINT('',(-14.,6.,-86.0352282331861));
#2526=VERTEX_POINT('',#2525);
#2527=CARTESIAN_POINT('',(-14.,6.,-1024.03522823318));
#2528=VERTEX_POINT('',#2527);
#2529=EDGE_CURVE('E640',#2526,#2528,#2524,.T.);
#2530=ORIENTED_EDGE('',*,*,#2529,.F.);
#2531=CARTESIAN_POINT('',(-14.,4.,-86.0352282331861));
#2532=DIRECTION('',(-0.707106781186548,0.,-0.707106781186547));
#2533=DIRECTION('',(0.707106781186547,0.,-0.707106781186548));
#2534=AXIS2_PLACEMENT_3D('',#2531,#2532,#2533);
#2535=ELLIPSE('',#2534,2.82842712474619,2.);
#2536=EDGE_CURVE('E1262',#2526,#2495,#2535,.F.);
#2537=ORIENTED_EDGE('',*,*,#2536,.T.);
#2538=ORIENTED_EDGE('',*,*,#2498,.T.);
#2539=CARTESIAN_POINT('',(-14.,4.,-1024.03522823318));
#2540=DIRECTION('',(-0.707106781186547,0.,0.707106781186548));
#2541=DIRECTION('',(-0.707106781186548,0.,-0.707106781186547));
#2542=AXIS2_PLACEMENT_3D('',#2539,#2540,#2541);
#2543=ELLIPSE('',#2542,2.82842712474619,2.);
#2544=EDGE_CURVE('E970',#2497,#2528,#2543,.F.);
#2545=ORIENTED_EDGE('',*,*,#2544,.T.);
#2546=EDGE_LOOP('',(#2530,#2537,#2538,#2545));
#2547=FACE_BOUND('',#2546,.T.);
#2548=ADVANCED_FACE('F1782',(#2547),#2520,.F.);
#2549=CARTESIAN_POINT('',(-22.1464466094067,6.,-55.0352282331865));
#2550=DIRECTION('',(0.,-1.,0.));
#2551=DIRECTION('',(0.,0.,-1.));
#2552=AXIS2_PLACEMENT_3D('',#2549,#2550,#2551);
#2553=PLANE('',#2552);
#2554=DIRECTION('',(0.707106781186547,0.,-0.707106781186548));
#2555=VECTOR('',#2554,1.);
#2556=CARTESIAN_POINT('',(-33.5732233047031,6.,-66.4620049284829));
#2557=LINE('',#2556,#2555);
#2558=CARTESIAN_POINT('',(-11.,6.,-89.0352282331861));
#2559=VERTEX_POINT('',#2558);
#2560=EDGE_CURVE('E1260',#2526,#2559,#2557,.T.);
#2561=ORIENTED_EDGE('',*,*,#2560,.F.);
#2562=ORIENTED_EDGE('',*,*,#2529,.T.);
#2563=DIRECTION('',(-0.707106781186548,0.,-0.707106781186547));
#2564=VECTOR('',#2563,1.);
#2565=CARTESIAN_POINT('',(466.426776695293,6.,-543.608451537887));
#2566=LINE('',#2565,#2564);
#2567=CARTESIAN_POINT('',(-11.,6.,-1021.03522823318));
#2568=VERTEX_POINT('',#2567);
#2569=EDGE_CURVE('E967',#2568,#2528,#2566,.T.);
#2570=ORIENTED_EDGE('',*,*,#2569,.F.);
#2571=DIRECTION('',(0.,0.,-1.));
#2572=VECTOR('',#2571,1.);
#2573=CARTESIAN_POINT('',(-11.,6.,-55.0352282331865));
#2574=LINE('',#2573,#2572);
#2575=EDGE_CURVE('E638',#2559,#2568,#2574,.T.);
#2576=ORIENTED_EDGE('',*,*,#2575,.F.);
#2577=EDGE_LOOP('',(#2561,#2562,#2570,#2576));
#2578=FACE_BOUND('',#2577,.T.);
#2579=ADVANCED_FACE('F1790',(#2578),#2553,.T.);
#2580=CARTESIAN_POINT('',(-11.,-28.2727922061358,-55.0352282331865));
#2581=DIRECTION('',(-1.,0.,0.));
#2582=DIRECTION('',(0.,-1.,0.));
#2583=AXIS2_PLACEMENT_3D('',#2580,#2581,#2582);
#2584=PLANE('',#2583);
#2585=DIRECTION('',(0.,0.,-1.));
#2586=VECTOR('',#2585,1.);
#2587=CARTESIAN_POINT('',(-11.,8.99999999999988,-55.0352282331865));
#2588=LINE('',#2587,#2586);
#2589=CARTESIAN_POINT('',(-11.,8.99999999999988,-89.0352282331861));
#2590=VERTEX_POINT('',#2589);
#2591=CARTESIAN_POINT('',(-11.,8.99999999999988,-1021.03522823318));
#2592=VERTEX_POINT('',#2591);
#2593=EDGE_CURVE('E636',#2590,#2592,#2588,.T.);
#2594=ORIENTED_EDGE('',*,*,#2593,.F.);
#2595=DIRECTION('',(0.,-1.,0.));
#2596=VECTOR('',#2595,1.);
#2597=CARTESIAN_POINT('',(-11.,-28.2727922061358,-89.0352282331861));
#2598=LINE('',#2597,#2596);
#2599=EDGE_CURVE('E1257',#2590,#2559,#2598,.T.);
#2600=ORIENTED_EDGE('',*,*,#2599,.T.);
#2601=ORIENTED_EDGE('',*,*,#2575,.T.);
#2602=DIRECTION('',(0.,1.,0.));
#2603=VECTOR('',#2602,1.);
#2604=CARTESIAN_POINT('',(-11.,-28.2727922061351,-1021.03522823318));
#2605=LINE('',#2604,#2603);
#2606=EDGE_CURVE('E964',#2568,#2592,#2605,.T.);
#2607=ORIENTED_EDGE('',*,*,#2606,.T.);
#2608=EDGE_LOOP('',(#2594,#2600,#2601,#2607));
#2609=FACE_BOUND('',#2608,.T.);
#2610=ADVANCED_FACE('F1798',(#2609),#2584,.F.);
#2611=CARTESIAN_POINT('',(-9.,8.99999999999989,-55.0352282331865));
#2612=DIRECTION('',(0.,0.,-1.));
#2613=DIRECTION('',(-1.,0.,0.));
#2614=AXIS2_PLACEMENT_3D('',#2611,#2612,#2613);
#2615=CYLINDRICAL_SURFACE('',#2614,2.);
#2616=CARTESIAN_POINT('',(-9.,8.99999999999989,-91.0352282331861));
#2617=DIRECTION('',(-0.707106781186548,0.,-0.707106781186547));
#2618=DIRECTION('',(0.707106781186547,0.,-0.707106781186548));
#2619=AXIS2_PLACEMENT_3D('',#2616,#2617,#2618);
#2620=ELLIPSE('',#2619,2.82842712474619,2.);
#2621=CARTESIAN_POINT('',(-9.,10.9999999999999,-91.0352282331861));
#2622=VERTEX_POINT('',#2621);
#2623=EDGE_CURVE('E56',#2590,#2622,#2620,.T.);
#2624=ORIENTED_EDGE('',*,*,#2623,.F.);
#2625=ORIENTED_EDGE('',*,*,#2593,.T.);
#2626=CARTESIAN_POINT('',(-9.,8.99999999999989,-1019.03522823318));
#2627=DIRECTION('',(-0.707106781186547,0.,0.707106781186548));
#2628=DIRECTION('',(-0.707106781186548,0.,-0.707106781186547));
#2629=AXIS2_PLACEMENT_3D('',#2626,#2627,#2628);
#2630=ELLIPSE('',#2629,2.82842712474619,2.);
#2631=CARTESIAN_POINT('',(-8.99999999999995,10.9999999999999,-1019.03522823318));
#2632=VERTEX_POINT('',#2631);
#2633=EDGE_CURVE('E961',#2632,#2592,#2630,.T.);
#2634=ORIENTED_EDGE('',*,*,#2633,.F.);
#2635=DIRECTION('',(0.,0.,-1.));
#2636=VECTOR('',#2635,1.);
#2637=CARTESIAN_POINT('',(-9.,10.9999999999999,-55.0352282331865));
#2638=LINE('',#2637,#2636);
#2639=EDGE_CURVE('E634',#2622,#2632,#2638,.T.);
#2640=ORIENTED_EDGE('',*,*,#2639,.F.);
#2641=EDGE_LOOP('',(#2624,#2625,#2634,#2640));
#2642=FACE_BOUND('',#2641,.T.);
#2643=ADVANCED_FACE('F1381',(#2642),#2615,.F.);
#2644=CARTESIAN_POINT('',(-22.5,22.5,-55.0352282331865));
#2645=DIRECTION('',(0.,0.,-1.));
#2646=DIRECTION('',(-1.,0.,0.));
#2647=AXIS2_PLACEMENT_3D('',#2644,#2645,#2646);
#2648=CYLINDRICAL_SURFACE('',#2647,5.);
#2649=CARTESIAN_POINT('',(-22.5,22.5,-77.5352282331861));
#2650=DIRECTION('',(-0.707106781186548,0.,-0.707106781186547));
#2651=DIRECTION('',(0.707106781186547,0.,-0.707106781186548));
#2652=AXIS2_PLACEMENT_3D('',#2649,#2650,#2651);
#2653=ELLIPSE('',#2652,7.07106781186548,5.);
#2654=CARTESIAN_POINT('',(-17.5,22.5,-82.5352282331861));
#2655=VERTEX_POINT('',#2654);
#2656=EDGE_CURVE('E1103',#2655,#2655,#2653,.T.);
#2657=ORIENTED_EDGE('',*,*,#2656,.F.);
#2658=EDGE_LOOP('',(#2657));
#2659=FACE_BOUND('',#2658,.T.);
#2660=CARTESIAN_POINT('',(-22.5,22.5,-1032.53522823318));
#2661=DIRECTION('',(-0.707106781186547,0.,0.707106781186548));
#2662=DIRECTION('',(-0.707106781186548,0.,-0.707106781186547));
#2663=AXIS2_PLACEMENT_3D('',#2660,#2661,#2662);
#2664=ELLIPSE('',#2663,7.07106781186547,5.);
#2665=CARTESIAN_POINT('',(-27.5,22.5,-1037.53522823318));
#2666=VERTEX_POINT('',#2665);
#2667=EDGE_CURVE('E835',#2666,#2666,#2664,.T.);
#2668=ORIENTED_EDGE('',*,*,#2667,.F.);
#2669=EDGE_LOOP('',(#2668));
#2670=FACE_BOUND('',#2669,.T.);
#2671=ADVANCED_FACE('F1377',(#2659,#2670),#2648,.F.);
#2672=CARTESIAN_POINT('',(2.35606601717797,-3.77027957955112,-55.0352282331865));
#2673=DIRECTION('',(-0.707106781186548,-0.707106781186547,0.));
#2674=DIRECTION('',(0.707106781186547,-0.707106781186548,0.));
#2675=AXIS2_PLACEMENT_3D('',#2672,#2673,#2674);
#2676=PLANE('',#2675);
#2677=DIRECTION('',(0.577350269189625,-0.577350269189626,-0.577350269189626));
#2678=VECTOR('',#2677,1.);
#2679=CARTESIAN_POINT('',(-13.4292893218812,12.0150757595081,-86.6059389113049));
#2680=LINE('',#2679,#2678);
#2681=EDGE_CURVE('E1327',#915,#522,#2680,.T.);
#2682=ORIENTED_EDGE('',*,*,#2681,.F.);
#2683=ORIENTED_EDGE('',*,*,#932,.T.);
#2684=DIRECTION('',(-0.577350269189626,0.577350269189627,-0.577350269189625));
#2685=VECTOR('',#2684,1.);
#2686=CARTESIAN_POINT('',(319.904044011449,-321.318257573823,-690.131184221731));
#2687=LINE('',#2686,#2685);
#2688=EDGE_CURVE('E1045',#532,#925,#2687,.T.);
#2689=ORIENTED_EDGE('',*,*,#2688,.F.);
#2690=ORIENTED_EDGE('',*,*,#533,.F.);
#2691=EDGE_LOOP('',(#2682,#2683,#2689,#2690));
#2692=FACE_BOUND('',#2691,.T.);
#2693=ADVANCED_FACE('F1380',(#2692),#2676,.T.);
#2694=CARTESIAN_POINT('',(-7.49999999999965,-28.2727922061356,-55.0352282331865));
#2695=DIRECTION('',(-1.,0.,0.));
#2696=DIRECTION('',(0.,-1.,0.));
#2697=AXIS2_PLACEMENT_3D('',#2694,#2695,#2696);
#2698=PLANE('',#2697);
#2699=DIRECTION('',(0.,-1.,0.));
#2700=VECTOR('',#2699,1.);
#2701=CARTESIAN_POINT('',(-7.49999999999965,-28.2727922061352,-92.5352282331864));
#2702=LINE('',#2701,#2700);
#2703=EDGE_CURVE('E1288',#2199,#957,#2702,.T.);
#2704=ORIENTED_EDGE('',*,*,#2703,.F.);
#2705=ORIENTED_EDGE('',*,*,#2202,.T.);
#2706=DIRECTION('',(0.,1.,0.));
#2707=VECTOR('',#2706,1.);
#2708=CARTESIAN_POINT('',(-7.49999999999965,-28.2727922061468,-1017.53522823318));
#2709=LINE('',#2708,#2707);
#2710=EDGE_CURVE('E998',#965,#2201,#2709,.T.);
#2711=ORIENTED_EDGE('',*,*,#2710,.F.);
#2712=ORIENTED_EDGE('',*,*,#966,.F.);
#2713=EDGE_LOOP('',(#2704,#2705,#2711,#2712));
#2714=FACE_BOUND('',#2713,.T.);
#2715=ADVANCED_FACE('F1385',(#2714),#2698,.T.);
#2716=CARTESIAN_POINT('',(-22.146446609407,10.9999999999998,-55.0352282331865));
#2717=DIRECTION('',(0.,-1.,0.));
#2718=DIRECTION('',(1.,0.,0.));
#2719=AXIS2_PLACEMENT_3D('',#2716,#2717,#2718);
#2720=PLANE('',#2719);
#2721=DIRECTION('',(0.707106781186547,0.,-0.707106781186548));
#2722=VECTOR('',#2721,1.);
#2723=CARTESIAN_POINT('',(-33.5732233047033,10.9999999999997,-66.4620049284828));
#2724=LINE('',#2723,#2722);
#2725=EDGE_CURVE('E1254',#2622,#2240,#2724,.T.);
#2726=ORIENTED_EDGE('',*,*,#2725,.F.);
#2727=ORIENTED_EDGE('',*,*,#2639,.T.);
#2728=DIRECTION('',(-0.707106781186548,0.,-0.707106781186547));
#2729=VECTOR('',#2728,1.);
#2730=CARTESIAN_POINT('',(466.426776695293,11.0000000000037,-543.608451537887));
#2731=LINE('',#2730,#2729);
#2732=EDGE_CURVE('E958',#2248,#2632,#2731,.T.);
#2733=ORIENTED_EDGE('',*,*,#2732,.F.);
#2734=ORIENTED_EDGE('',*,*,#2249,.F.);
#2735=EDGE_LOOP('',(#2726,#2727,#2733,#2734));
#2736=FACE_BOUND('',#2735,.T.);
#2737=ADVANCED_FACE('F1828',(#2736),#2720,.T.);
#2738=CARTESIAN_POINT('',(-22.1464466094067,33.9999999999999,-55.0352282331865));
#2739=DIRECTION('',(0.,-1.,0.));
#2740=DIRECTION('',(0.,0.,-1.));
#2741=AXIS2_PLACEMENT_3D('',#2738,#2739,#2740);
#2742=PLANE('',#2741);
#2743=ORIENTED_EDGE('',*,*,#41,.F.);
#2744=DIRECTION('',(0.707106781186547,0.,-0.707106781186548));
#2745=VECTOR('',#2744,1.);
#2746=CARTESIAN_POINT('',(-33.5732233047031,33.9999999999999,-66.4620049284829));
#2747=LINE('',#2746,#2745);
#2748=EDGE_CURVE('E1213',#30,#488,#2747,.T.);
#2749=ORIENTED_EDGE('',*,*,#2748,.T.);
#2750=ORIENTED_EDGE('',*,*,#491,.T.);
#2751=DIRECTION('',(-0.707106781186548,0.,-0.707106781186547));
#2752=VECTOR('',#2751,1.);
#2753=CARTESIAN_POINT('',(466.426776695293,33.9999999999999,-543.608451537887));
#2754=LINE('',#2753,#2752);
#2755=EDGE_CURVE('E910',#490,#40,#2754,.T.);
#2756=ORIENTED_EDGE('',*,*,#2755,.T.);
#2757=EDGE_LOOP('',(#2743,#2749,#2750,#2756));
#2758=FACE_BOUND('',#2757,.T.);
#2759=ADVANCED_FACE('F1836',(#2758),#2742,.F.);
#2760=CARTESIAN_POINT('',(-45.,74.3573124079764,-1055.03522823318));
#2761=DIRECTION('',(-0.707106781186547,0.,0.707106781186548));
#2762=DIRECTION('',(0.707106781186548,0.,0.707106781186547));
#2763=AXIS2_PLACEMENT_3D('',#2760,#2761,#2762);
#2764=PLANE('',#2763);
#2765=ORIENTED_EDGE('',*,*,#2667,.T.);
#2766=EDGE_LOOP('',(#2765));
#2767=FACE_BOUND('',#2766,.T.);
#2768=ORIENTED_EDGE('',*,*,#542,.T.);
#2769=ORIENTED_EDGE('',*,*,#2688,.T.);
#2770=ORIENTED_EDGE('',*,*,#926,.T.);
#2771=ORIENTED_EDGE('',*,*,#899,.F.);
#2772=ORIENTED_EDGE('',*,*,#862,.T.);
#2773=ORIENTED_EDGE('',*,*,#829,.T.);
#2774=ORIENTED_EDGE('',*,*,#804,.F.);
#2775=ORIENTED_EDGE('',*,*,#765,.T.);
#2776=ORIENTED_EDGE('',*,*,#734,.T.);
#2777=ORIENTED_EDGE('',*,*,#707,.F.);
#2778=ORIENTED_EDGE('',*,*,#670,.T.);
#2779=ORIENTED_EDGE('',*,*,#645,.F.);
#2780=ORIENTED_EDGE('',*,*,#614,.F.);
#2781=ORIENTED_EDGE('',*,*,#581,.F.);
#2782=EDGE_LOOP('',(#2768,#2769,#2770,#2771,#2772,#2773,#2774,#2775,#2776,#2777,#2778,#2779,
#2780,#2781));
#2783=FACE_BOUND('',#2782,.T.);
#2784=ORIENTED_EDGE('',*,*,#50,.T.);
#2785=ORIENTED_EDGE('',*,*,#2755,.F.);
#2786=ORIENTED_EDGE('',*,*,#506,.F.);
#2787=ORIENTED_EDGE('',*,*,#467,.T.);
#2788=ORIENTED_EDGE('',*,*,#442,.F.);
#2789=ORIENTED_EDGE('',*,*,#409,.F.);
#2790=ORIENTED_EDGE('',*,*,#372,.T.);
#2791=ORIENTED_EDGE('',*,*,#345,.F.);
#2792=ORIENTED_EDGE('',*,*,#308,.T.);
#2793=ORIENTED_EDGE('',*,*,#275,.T.);
#2794=ORIENTED_EDGE('',*,*,#244,.T.);
#2795=ORIENTED_EDGE('',*,*,#217,.F.);
#2796=ORIENTED_EDGE('',*,*,#186,.F.);
#2797=ORIENTED_EDGE('',*,*,#153,.F.);
#2798=ORIENTED_EDGE('',*,*,#114,.T.);
#2799=ORIENTED_EDGE('',*,*,#81,.T.);
#2800=EDGE_LOOP('',(#2784,#2785,#2786,#2787,#2788,#2789,#2790,#2791,#2792,#2793,#2794,#2795,
#2796,#2797,#2798,#2799));
#2801=FACE_BOUND('',#2800,.T.);
#2802=ORIENTED_EDGE('',*,*,#2732,.T.);
#2803=ORIENTED_EDGE('',*,*,#2633,.T.);
#2804=ORIENTED_EDGE('',*,*,#2606,.F.);
#2805=ORIENTED_EDGE('',*,*,#2569,.T.);
#2806=ORIENTED_EDGE('',*,*,#2544,.F.);
#2807=ORIENTED_EDGE('',*,*,#2511,.F.);
#2808=ORIENTED_EDGE('',*,*,#2480,.F.);
#2809=ORIENTED_EDGE('',*,*,#2447,.F.);
#2810=ORIENTED_EDGE('',*,*,#2416,.F.);
#2811=ORIENTED_EDGE('',*,*,#2377,.T.);
#2812=ORIENTED_EDGE('',*,*,#2346,.T.);
#2813=ORIENTED_EDGE('',*,*,#2313,.T.);
#2814=ORIENTED_EDGE('',*,*,#2288,.F.);
#2815=ORIENTED_EDGE('',*,*,#2255,.F.);
#2816=EDGE_LOOP('',(#2802,#2803,#2804,#2805,#2806,#2807,#2808,#2809,#2810,#2811,#2812,#2813,
#2814,#2815));
#2817=FACE_BOUND('',#2816,.T.);
#2818=ORIENTED_EDGE('',*,*,#1352,.T.);
#2819=ORIENTED_EDGE('',*,*,#1315,.T.);
#2820=ORIENTED_EDGE('',*,*,#1290,.F.);
#2821=ORIENTED_EDGE('',*,*,#1253,.T.);
#2822=ORIENTED_EDGE('',*,*,#1228,.F.);
#2823=ORIENTED_EDGE('',*,*,#1191,.T.);
#2824=ORIENTED_EDGE('',*,*,#1160,.T.);
#2825=ORIENTED_EDGE('',*,*,#1133,.F.);
#2826=ORIENTED_EDGE('',*,*,#1102,.F.);
#2827=ORIENTED_EDGE('',*,*,#1069,.F.);
#2828=ORIENTED_EDGE('',*,*,#1030,.T.);
#2829=ORIENTED_EDGE('',*,*,#1005,.F.);
#2830=ORIENTED_EDGE('',*,*,#972,.F.);
#2831=ORIENTED_EDGE('',*,*,#2710,.T.);
#2832=ORIENTED_EDGE('',*,*,#2215,.F.);
#2833=ORIENTED_EDGE('',*,*,#2178,.T.);
#2834=ORIENTED_EDGE('',*,*,#2147,.T.);
#2835=ORIENTED_EDGE('',*,*,#2122,.T.);
#2836=ORIENTED_EDGE('',*,*,#2093,.T.);
#2837=ORIENTED_EDGE('',*,*,#2060,.T.);
#2838=ORIENTED_EDGE('',*,*,#2043,.F.);
#2839=ORIENTED_EDGE('',*,*,#2012,.F.);
#2840=ORIENTED_EDGE('',*,*,#1975,.T.);
#2841=ORIENTED_EDGE('',*,*,#1950,.F.);
#2842=ORIENTED_EDGE('',*,*,#1913,.T.);
#2843=ORIENTED_EDGE('',*,*,#1882,.T.);
#2844=ORIENTED_EDGE('',*,*,#1855,.F.);
#2845=ORIENTED_EDGE('',*,*,#1824,.F.);
#2846=ORIENTED_EDGE('',*,*,#1796,.F.);
#2847=ORIENTED_EDGE('',*,*,#1757,.T.);
#2848=ORIENTED_EDGE('',*,*,#1732,.F.);
#2849=ORIENTED_EDGE('',*,*,#1699,.F.);
#2850=ORIENTED_EDGE('',*,*,#1662,.T.);
#2851=ORIENTED_EDGE('',*,*,#1637,.F.);
#2852=ORIENTED_EDGE('',*,*,#1600,.T.);
#2853=ORIENTED_EDGE('',*,*,#1569,.T.);
#2854=ORIENTED_EDGE('',*,*,#1538,.T.);
#2855=ORIENTED_EDGE('',*,*,#1513,.F.);
#2856=ORIENTED_EDGE('',*,*,#1465,.T.);
#2857=ORIENTED_EDGE('',*,*,#1449,.F.);
#2858=ORIENTED_EDGE('',*,*,#1416,.F.);
#2859=ORIENTED_EDGE('',*,*,#1385,.F.);
#2860=EDGE_LOOP('',(#2818,#2819,#2820,#2821,#2822,#2823,#2824,#2825,#2826,#2827,#2828,#2829,
#2830,#2831,#2832,#2833,#2834,#2835,#2836,#2837,#2838,#2839,#2840,#2841,#2842,#2843,#2844,#2845,
#2846,#2847,#2848,#2849,#2850,#2851,#2852,#2853,#2854,#2855,#2856,#2857,#2858,#2859));
#2861=FACE_BOUND('',#2860,.T.);
#2862=ADVANCED_FACE('F733',(#2767,#2783,#2801,#2817,#2861),#2764,.F.);
#2863=CARTESIAN_POINT('',(-45.,74.3573124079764,-55.0352282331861));
#2864=DIRECTION('',(-0.707106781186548,0.,-0.707106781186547));
#2865=DIRECTION('',(-0.707106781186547,0.,0.707106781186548));
#2866=AXIS2_PLACEMENT_3D('',#2863,#2864,#2865);
#2867=PLANE('',#2866);
#2868=ORIENTED_EDGE('',*,*,#2656,.T.);
#2869=EDGE_LOOP('',(#2868));
#2870=FACE_BOUND('',#2869,.T.);
#2871=ORIENTED_EDGE('',*,*,#525,.T.);
#2872=ORIENTED_EDGE('',*,*,#573,.F.);
#2873=ORIENTED_EDGE('',*,*,#606,.F.);
#2874=ORIENTED_EDGE('',*,*,#638,.F.);
#2875=ORIENTED_EDGE('',*,*,#661,.T.);
#2876=ORIENTED_EDGE('',*,*,#700,.F.);
#2877=ORIENTED_EDGE('',*,*,#724,.T.);
#2878=ORIENTED_EDGE('',*,*,#756,.T.);
#2879=ORIENTED_EDGE('',*,*,#796,.F.);
#2880=ORIENTED_EDGE('',*,*,#820,.T.);
#2881=ORIENTED_EDGE('',*,*,#852,.T.);
#2882=ORIENTED_EDGE('',*,*,#892,.F.);
#2883=ORIENTED_EDGE('',*,*,#916,.T.);
#2884=ORIENTED_EDGE('',*,*,#2681,.T.);
#2885=EDGE_LOOP('',(#2871,#2872,#2873,#2874,#2875,#2876,#2877,#2878,#2879,#2880,#2881,#2882,
#2883,#2884));
#2886=FACE_BOUND('',#2885,.T.);
#2887=ORIENTED_EDGE('',*,*,#33,.T.);
#2888=ORIENTED_EDGE('',*,*,#72,.T.);
#2889=ORIENTED_EDGE('',*,*,#104,.T.);
#2890=ORIENTED_EDGE('',*,*,#145,.F.);
#2891=ORIENTED_EDGE('',*,*,#178,.F.);
#2892=ORIENTED_EDGE('',*,*,#210,.F.);
#2893=ORIENTED_EDGE('',*,*,#234,.T.);
#2894=ORIENTED_EDGE('',*,*,#266,.T.);
#2895=ORIENTED_EDGE('',*,*,#298,.T.);
#2896=ORIENTED_EDGE('',*,*,#338,.F.);
#2897=ORIENTED_EDGE('',*,*,#362,.T.);
#2898=ORIENTED_EDGE('',*,*,#402,.F.);
#2899=ORIENTED_EDGE('',*,*,#434,.F.);
#2900=ORIENTED_EDGE('',*,*,#458,.T.);
#2901=ORIENTED_EDGE('',*,*,#498,.F.);
#2902=ORIENTED_EDGE('',*,*,#2748,.F.);
#2903=EDGE_LOOP('',(#2887,#2888,#2889,#2890,#2891,#2892,#2893,#2894,#2895,#2896,#2897,#2898,
#2899,#2900,#2901,#2902));
#2904=FACE_BOUND('',#2903,.T.);
#2905=ORIENTED_EDGE('',*,*,#2280,.F.);
#2906=ORIENTED_EDGE('',*,*,#2304,.T.);
#2907=ORIENTED_EDGE('',*,*,#2336,.T.);
#2908=ORIENTED_EDGE('',*,*,#2368,.T.);
#2909=ORIENTED_EDGE('',*,*,#2408,.F.);
#2910=ORIENTED_EDGE('',*,*,#2440,.F.);
#2911=ORIENTED_EDGE('',*,*,#2472,.F.);
#2912=ORIENTED_EDGE('',*,*,#2504,.F.);
#2913=ORIENTED_EDGE('',*,*,#2536,.F.);
#2914=ORIENTED_EDGE('',*,*,#2560,.T.);
#2915=ORIENTED_EDGE('',*,*,#2599,.F.);
#2916=ORIENTED_EDGE('',*,*,#2623,.T.);
#2917=ORIENTED_EDGE('',*,*,#2725,.T.);
#2918=ORIENTED_EDGE('',*,*,#2241,.F.);
#2919=EDGE_LOOP('',(#2905,#2906,#2907,#2908,#2909,#2910,#2911,#2912,#2913,#2914,#2915,#2916,
#2917,#2918));
#2920=FACE_BOUND('',#2919,.T.);
#2921=ORIENTED_EDGE('',*,*,#1409,.F.);
#2922=ORIENTED_EDGE('',*,*,#1441,.F.);
#2923=ORIENTED_EDGE('',*,*,#1479,.F.);
#2924=ORIENTED_EDGE('',*,*,#1505,.F.);
#2925=ORIENTED_EDGE('',*,*,#1529,.T.);
#2926=ORIENTED_EDGE('',*,*,#1560,.T.);
#2927=ORIENTED_EDGE('',*,*,#1591,.T.);
#2928=ORIENTED_EDGE('',*,*,#1630,.F.);
#2929=ORIENTED_EDGE('',*,*,#1653,.T.);
#2930=ORIENTED_EDGE('',*,*,#1692,.F.);
#2931=ORIENTED_EDGE('',*,*,#1724,.F.);
#2932=ORIENTED_EDGE('',*,*,#1748,.T.);
#2933=ORIENTED_EDGE('',*,*,#1788,.F.);
#2934=ORIENTED_EDGE('',*,*,#1816,.F.);
#2935=ORIENTED_EDGE('',*,*,#1848,.F.);
#2936=ORIENTED_EDGE('',*,*,#1872,.T.);
#2937=ORIENTED_EDGE('',*,*,#1904,.T.);
#2938=ORIENTED_EDGE('',*,*,#1943,.F.);
#2939=ORIENTED_EDGE('',*,*,#1966,.T.);
#2940=ORIENTED_EDGE('',*,*,#2005,.F.);
#2941=ORIENTED_EDGE('',*,*,#2036,.F.);
#2942=ORIENTED_EDGE('',*,*,#2055,.T.);
#2943=ORIENTED_EDGE('',*,*,#2083,.T.);
#2944=ORIENTED_EDGE('',*,*,#2119,.F.);
#2945=ORIENTED_EDGE('',*,*,#2138,.T.);
#2946=ORIENTED_EDGE('',*,*,#2169,.T.);
#2947=ORIENTED_EDGE('',*,*,#2208,.F.);
#2948=ORIENTED_EDGE('',*,*,#2703,.T.);
#2949=ORIENTED_EDGE('',*,*,#958,.F.);
#2950=ORIENTED_EDGE('',*,*,#997,.F.);
#2951=ORIENTED_EDGE('',*,*,#1021,.T.);
#2952=ORIENTED_EDGE('',*,*,#1061,.F.);
#2953=ORIENTED_EDGE('',*,*,#1094,.F.);
#2954=ORIENTED_EDGE('',*,*,#1126,.F.);
#2955=ORIENTED_EDGE('',*,*,#1150,.T.);
#2956=ORIENTED_EDGE('',*,*,#1182,.T.);
#2957=ORIENTED_EDGE('',*,*,#1221,.F.);
#2958=ORIENTED_EDGE('',*,*,#1244,.T.);
#2959=ORIENTED_EDGE('',*,*,#1283,.F.);
#2960=ORIENTED_EDGE('',*,*,#1306,.T.);
#2961=ORIENTED_EDGE('',*,*,#1345,.F.);
#2962=ORIENTED_EDGE('',*,*,#1377,.F.);
#2963=EDGE_LOOP('',(#2921,#2922,#2923,#2924,#2925,#2926,#2927,#2928,#2929,#2930,#2931,#2932,
#2933,#2934,#2935,#2936,#2937,#2938,#2939,#2940,#2941,#2942,#2943,#2944,#2945,#2946,#2947,#2948,
#2949,#2950,#2951,#2952,#2953,#2954,#2955,#2956,#2957,#2958,#2959,#2960,#2961,#2962));
#2964=FACE_BOUND('',#2963,.T.);
#2965=ADVANCED_FACE('F566',(#2870,#2886,#2904,#2920,#2964),#2867,.F.);
#2966=CLOSED_SHELL('',(#60,#91,#124,#157,#190,#221,#254,#285,#318,#349,#382,#413,#446,#477,#510,
#552,#585,#618,#649,#680,#711,#744,#775,#808,#839,#872,#903,#936,#976,#1009,#1040,#1073,#1106,
#1137,#1170,#1201,#1232,#1263,#1294,#1325,#1356,#1389,#1420,#1453,#1484,#1517,#1548,#1579,#1610,
#1641,#1672,#1703,#1736,#1767,#1800,#1828,#1859,#1892,#1923,#1954,#1985,#2016,#2047,#2070,#2103,
#2126,#2157,#2188,#2219,#2259,#2292,#2323,#2356,#2387,#2420,#2451,#2484,#2515,#2548,#2579,#2610,
#2643,#2671,#2693,#2715,#2737,#2759,#2862,#2965));
#2967=MANIFOLD_SOLID_BREP('B2',#2966);
#2968=ADVANCED_BREP_SHAPE_REPRESENTATION('',(#18,#2967),#14);
#2969=SHAPE_DEFINITION_REPRESENTATION(#9,#2968);
ENDSEC;
END-ISO-10303-21;
